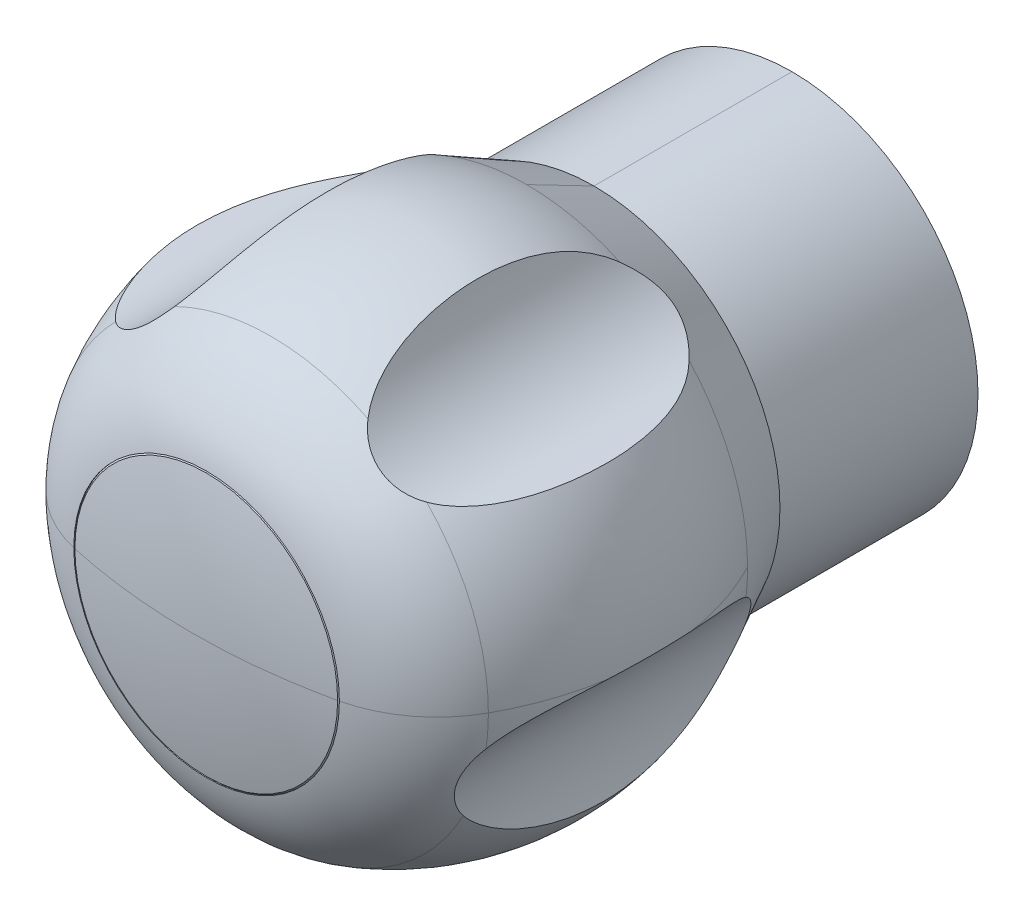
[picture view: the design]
ISO-10303-21;
HEADER;
FILE_DESCRIPTION(('STEP AP214'),'2;1');
FILE_NAME('part.step','',(''),(''),'','','');
FILE_SCHEMA(('AUTOMOTIVE_DESIGN { 1 0 10303 214 1 1 1 1 }'));
ENDSEC;
DATA;
#1=APPLICATION_CONTEXT('core data for automotive mechanical design processes');
#2=APPLICATION_PROTOCOL_DEFINITION('international standard','automotive_design',2000,#1);
#3=PRODUCT_CONTEXT('',#1,'mechanical');
#4=PRODUCT('Part','Part','',(#3));
#5=PRODUCT_RELATED_PRODUCT_CATEGORY('part','',(#4));
#6=PRODUCT_DEFINITION_FORMATION('','',#4);
#7=PRODUCT_DEFINITION_CONTEXT('part definition',#1,'design');
#8=PRODUCT_DEFINITION('design','',#6,#7);
#9=PRODUCT_DEFINITION_SHAPE('','',#8);
#10=(LENGTH_UNIT() NAMED_UNIT(*) SI_UNIT(.MILLI.,.METRE.));
#11=(NAMED_UNIT(*) PLANE_ANGLE_UNIT() SI_UNIT($,.RADIAN.));
#12=(NAMED_UNIT(*) SI_UNIT($,.STERADIAN.) SOLID_ANGLE_UNIT());
#13=UNCERTAINTY_MEASURE_WITH_UNIT(LENGTH_MEASURE(1.E-05),#10,'distance_accuracy_value','');
#14=(GEOMETRIC_REPRESENTATION_CONTEXT(3) GLOBAL_UNCERTAINTY_ASSIGNED_CONTEXT((#13)) GLOBAL_UNIT_ASSIGNED_CONTEXT((#10,
#11,#12)) REPRESENTATION_CONTEXT('',''));
#15=CARTESIAN_POINT('',(0.,0.,0.));
#16=DIRECTION('',(0.,0.,1.));
#17=DIRECTION('',(1.,0.,0.));
#18=AXIS2_PLACEMENT_3D('',#15,#16,#17);
#19=CARTESIAN_POINT('',(0.,0.,-0.499999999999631));
#20=DIRECTION('',(0.,0.,1.));
#21=DIRECTION('',(0.,1.,0.));
#22=AXIS2_PLACEMENT_3D('',#19,#20,#21);
#23=SPHERICAL_SURFACE('',#22,60.5);
#24=CARTESIAN_POINT('',(0.,0.,58.5716338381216));
#25=DIRECTION('',(0.,0.,-1.));
#26=DIRECTION('',(0.,1.,0.));
#27=AXIS2_PLACEMENT_3D('',#24,#25,#26);
#28=CIRCLE('',#27,13.068744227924);
#29=CARTESIAN_POINT('',(0.,-13.068744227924,58.5716338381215));
#30=VERTEX_POINT('',#29);
#31=CARTESIAN_POINT('',(-13.0687442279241,-5.9981704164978E-11,58.5716338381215));
#32=VERTEX_POINT('',#31);
#33=EDGE_CURVE('E421',#30,#32,#28,.T.);
#34=ORIENTED_EDGE('',*,*,#33,.F.);
#35=CARTESIAN_POINT('',(0.,0.,58.5716338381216));
#36=DIRECTION('',(0.,0.,-1.));
#37=DIRECTION('',(0.,1.,0.));
#38=AXIS2_PLACEMENT_3D('',#35,#36,#37);
#39=CIRCLE('',#38,13.068744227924);
#40=CARTESIAN_POINT('',(13.068744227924,-2.99962703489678E-11,58.5716338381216));
#41=VERTEX_POINT('',#40);
#42=EDGE_CURVE('E220',#41,#30,#39,.T.);
#43=ORIENTED_EDGE('',*,*,#42,.F.);
#44=CARTESIAN_POINT('',(0.,0.,60.0000000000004));
#45=CARTESIAN_POINT('',(0.548857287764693,-5.03823967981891E-12,60.0000019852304));
#46=CARTESIAN_POINT('',(1.09771448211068,-1.00764785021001E-11,59.9925312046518));
#47=CARTESIAN_POINT('',(2.1950223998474,-2.01492249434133E-11,59.9626583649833));
#48=CARTESIAN_POINT('',(2.74347312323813,-2.51837325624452E-11,59.9402563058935));
#49=CARTESIAN_POINT('',(3.83956181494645,-3.52452871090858E-11,59.8805351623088));
#50=CARTESIAN_POINT('',(4.38719978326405,-4.02723340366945E-11,59.8432160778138));
#51=CARTESIAN_POINT('',(5.48125736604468,-5.03152440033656E-11,59.7536891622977));
#52=CARTESIAN_POINT('',(6.0276769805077,-5.5331107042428E-11,59.7014813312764));
#53=CARTESIAN_POINT('',(7.11889312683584,-6.5347934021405E-11,59.5822153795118));
#54=CARTESIAN_POINT('',(7.66368965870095,-7.03488979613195E-11,59.5151572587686));
#55=CARTESIAN_POINT('',(8.75125615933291,-8.03322229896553E-11,59.3662406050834));
#56=CARTESIAN_POINT('',(9.29402612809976,-8.53145840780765E-11,59.2843820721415));
#57=CARTESIAN_POINT('',(10.3771373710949,-9.52570120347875E-11,59.1059245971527));
#58=CARTESIAN_POINT('',(10.9174786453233,-1.00217078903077E-10,59.0093256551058));
#59=CARTESIAN_POINT('',(11.9953327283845,-1.1011124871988E-10,58.8014612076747));
#60=CARTESIAN_POINT('',(12.5328455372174,-1.15045351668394E-10,58.6901957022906));
#61=CARTESIAN_POINT('',(13.0687442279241,-1.19964637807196E-10,58.5716338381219));
#62=B_SPLINE_CURVE_WITH_KNOTS('',3,(#44,#45,#46,#47,#48,#49,#50,#51,#52,#53,#54,#55,#56,#57,#58,
#59,#60,#61),.UNSPECIFIED.,.F.,.F.,(4,2,2,2,2,2,2,2,4),(0.,1.64652088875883,3.29304177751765,
4.93956266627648,6.5860835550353,8.23260444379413,9.87912533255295,11.5256462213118,
13.1721671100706),.UNSPECIFIED.);
#63=CARTESIAN_POINT('',(0.,0.,60.));
#64=VERTEX_POINT('',#63);
#65=EDGE_CURVE('E211',#64,#41,#62,.T.);
#66=ORIENTED_EDGE('',*,*,#65,.F.);
#67=CARTESIAN_POINT('',(0.,0.,-0.499999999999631));
#68=DIRECTION('',(9.17859660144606E-12,-1.,0.));
#69=DIRECTION('',(0.,0.,1.));
#70=AXIS2_PLACEMENT_3D('',#67,#68,#69);
#71=CIRCLE('',#70,60.5);
#72=EDGE_CURVE('E218',#32,#64,#71,.F.);
#73=ORIENTED_EDGE('',*,*,#72,.F.);
#74=EDGE_LOOP('',(#34,#43,#66,#73));
#75=FACE_BOUND('',#74,.T.);
#76=ADVANCED_FACE('F14',(#75),#23,.T.);
#77=CARTESIAN_POINT('',(0.,0.,-0.499999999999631));
#78=DIRECTION('',(0.,0.,1.));
#79=DIRECTION('',(0.,1.,0.));
#80=AXIS2_PLACEMENT_3D('',#77,#78,#79);
#81=SPHERICAL_SURFACE('',#80,60.5);
#82=CARTESIAN_POINT('',(0.,0.,58.5716338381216));
#83=DIRECTION('',(0.,0.,-1.));
#84=DIRECTION('',(0.,1.,0.));
#85=AXIS2_PLACEMENT_3D('',#82,#83,#84);
#86=CIRCLE('',#85,13.068744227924);
#87=CARTESIAN_POINT('',(0.,13.068744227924,58.5716338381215));
#88=VERTEX_POINT('',#87);
#89=EDGE_CURVE('E441',#88,#41,#86,.T.);
#90=ORIENTED_EDGE('',*,*,#89,.F.);
#91=CARTESIAN_POINT('',(0.,0.,58.5716338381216));
#92=DIRECTION('',(0.,0.,-1.));
#93=DIRECTION('',(0.,1.,0.));
#94=AXIS2_PLACEMENT_3D('',#91,#92,#93);
#95=CIRCLE('',#94,13.068744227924);
#96=EDGE_CURVE('E227',#32,#88,#95,.T.);
#97=ORIENTED_EDGE('',*,*,#96,.F.);
#98=ORIENTED_EDGE('',*,*,#72,.T.);
#99=ORIENTED_EDGE('',*,*,#65,.T.);
#100=EDGE_LOOP('',(#90,#97,#98,#99));
#101=FACE_BOUND('',#100,.T.);
#102=ADVANCED_FACE('F225',(#101),#81,.T.);
#103=CARTESIAN_POINT('',(0.,0.,58.4302124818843));
#104=DIRECTION('',(0.,0.,-1.));
#105=DIRECTION('',(-1.,0.,0.));
#106=AXIS2_PLACEMENT_3D('',#103,#104,#105);
#107=CONICAL_SURFACE('',#106,13.2101655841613,0.785398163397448);
#108=DIRECTION('',(0.,0.707106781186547,0.707106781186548));
#109=VECTOR('',#108,1.);
#110=CARTESIAN_POINT('',(0.,-13.1394549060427,58.5009231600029));
#111=LINE('',#110,#109);
#112=CARTESIAN_POINT('',(0.,-13.2101655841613,58.4302124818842));
#113=VERTEX_POINT('',#112);
#114=EDGE_CURVE('E418',#113,#30,#111,.T.);
#115=ORIENTED_EDGE('',*,*,#114,.F.);
#116=CARTESIAN_POINT('',(0.,0.,58.4302124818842));
#117=DIRECTION('',(0.,0.,1.));
#118=DIRECTION('',(1.,0.,0.));
#119=AXIS2_PLACEMENT_3D('',#116,#117,#118);
#120=CIRCLE('',#119,13.2101655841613);
#121=CARTESIAN_POINT('',(0.,13.2101655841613,58.4302124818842));
#122=VERTEX_POINT('',#121);
#123=EDGE_CURVE('E410',#113,#122,#120,.T.);
#124=ORIENTED_EDGE('',*,*,#123,.T.);
#125=DIRECTION('',(0.,-0.707106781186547,0.707106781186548));
#126=VECTOR('',#125,1.);
#127=CARTESIAN_POINT('',(0.,13.1394549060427,58.5009231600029));
#128=LINE('',#127,#126);
#129=EDGE_CURVE('E415',#88,#122,#128,.F.);
#130=ORIENTED_EDGE('',*,*,#129,.F.);
#131=ORIENTED_EDGE('',*,*,#89,.T.);
#132=ORIENTED_EDGE('',*,*,#42,.T.);
#133=EDGE_LOOP('',(#115,#124,#130,#131,#132));
#134=FACE_BOUND('',#133,.T.);
#135=ADVANCED_FACE('F429',(#134),#107,.T.);
#136=CARTESIAN_POINT('',(0.,0.,58.4302124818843));
#137=DIRECTION('',(0.,0.,-1.));
#138=DIRECTION('',(-1.,0.,0.));
#139=AXIS2_PLACEMENT_3D('',#136,#137,#138);
#140=CONICAL_SURFACE('',#139,13.2101655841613,0.785398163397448);
#141=ORIENTED_EDGE('',*,*,#33,.T.);
#142=ORIENTED_EDGE('',*,*,#96,.T.);
#143=ORIENTED_EDGE('',*,*,#129,.T.);
#144=CARTESIAN_POINT('',(0.,0.,58.4302124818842));
#145=DIRECTION('',(0.,0.,1.));
#146=DIRECTION('',(1.,0.,0.));
#147=AXIS2_PLACEMENT_3D('',#144,#145,#146);
#148=CIRCLE('',#147,13.2101655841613);
#149=EDGE_CURVE('E412',#122,#113,#148,.T.);
#150=ORIENTED_EDGE('',*,*,#149,.T.);
#151=ORIENTED_EDGE('',*,*,#114,.T.);
#152=EDGE_LOOP('',(#141,#142,#143,#150,#151));
#153=FACE_BOUND('',#152,.T.);
#154=ADVANCED_FACE('F882',(#153),#140,.T.);
#155=CARTESIAN_POINT('',(0.,0.,58.4848652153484));
#156=DIRECTION('',(0.,0.,1.));
#157=DIRECTION('',(1.,0.,0.));
#158=AXIS2_PLACEMENT_3D('',#155,#156,#157);
#159=CYLINDRICAL_SURFACE('',#158,13.2101655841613);
#160=ORIENTED_EDGE('',*,*,#123,.F.);
#161=DIRECTION('',(0.,0.,1.));
#162=VECTOR('',#161,1.);
#163=CARTESIAN_POINT('',(0.,-13.2101655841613,58.4848652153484));
#164=LINE('',#163,#162);
#165=CARTESIAN_POINT('',(0.,-13.2101655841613,58.5395179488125));
#166=VERTEX_POINT('',#165);
#167=EDGE_CURVE('E173',#113,#166,#164,.T.);
#168=ORIENTED_EDGE('',*,*,#167,.T.);
#169=CARTESIAN_POINT('',(0.,0.,58.5395179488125));
#170=DIRECTION('',(0.,0.,-1.));
#171=DIRECTION('',(-1.,0.,0.));
#172=AXIS2_PLACEMENT_3D('',#169,#170,#171);
#173=CIRCLE('',#172,13.2101655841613);
#174=CARTESIAN_POINT('',(13.2101655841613,0.,58.5395179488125));
#175=VERTEX_POINT('',#174);
#176=EDGE_CURVE('E390',#175,#166,#173,.T.);
#177=ORIENTED_EDGE('',*,*,#176,.F.);
#178=CARTESIAN_POINT('',(0.,0.,58.5395179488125));
#179=DIRECTION('',(0.,0.,-1.));
#180=DIRECTION('',(-1.,0.,0.));
#181=AXIS2_PLACEMENT_3D('',#178,#179,#180);
#182=CIRCLE('',#181,13.2101655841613);
#183=CARTESIAN_POINT('',(0.,13.2101655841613,58.5395179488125));
#184=VERTEX_POINT('',#183);
#185=EDGE_CURVE('E392',#184,#175,#182,.T.);
#186=ORIENTED_EDGE('',*,*,#185,.F.);
#187=DIRECTION('',(0.,0.,1.));
#188=VECTOR('',#187,1.);
#189=CARTESIAN_POINT('',(0.,13.2101655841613,58.4848652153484));
#190=LINE('',#189,#188);
#191=EDGE_CURVE('E404',#184,#122,#190,.F.);
#192=ORIENTED_EDGE('',*,*,#191,.T.);
#193=EDGE_LOOP('',(#160,#168,#177,#186,#192));
#194=FACE_BOUND('',#193,.T.);
#195=ADVANCED_FACE('F874',(#194),#159,.F.);
#196=CARTESIAN_POINT('',(0.,0.,58.4848652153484));
#197=DIRECTION('',(0.,0.,1.));
#198=DIRECTION('',(1.,0.,0.));
#199=AXIS2_PLACEMENT_3D('',#196,#197,#198);
#200=CYLINDRICAL_SURFACE('',#199,13.2101655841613);
#201=CARTESIAN_POINT('',(0.,0.,58.5395179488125));
#202=DIRECTION('',(0.,0.,-1.));
#203=DIRECTION('',(-1.,0.,0.));
#204=AXIS2_PLACEMENT_3D('',#201,#202,#203);
#205=CIRCLE('',#204,13.2101655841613);
#206=CARTESIAN_POINT('',(-13.2101655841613,0.,58.5395179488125));
#207=VERTEX_POINT('',#206);
#208=EDGE_CURVE('E395',#207,#184,#205,.T.);
#209=ORIENTED_EDGE('',*,*,#208,.F.);
#210=CARTESIAN_POINT('',(0.,0.,58.5395179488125));
#211=DIRECTION('',(0.,0.,-1.));
#212=DIRECTION('',(-1.,0.,0.));
#213=AXIS2_PLACEMENT_3D('',#210,#211,#212);
#214=CIRCLE('',#213,13.2101655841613);
#215=EDGE_CURVE('E398',#166,#207,#214,.T.);
#216=ORIENTED_EDGE('',*,*,#215,.F.);
#217=ORIENTED_EDGE('',*,*,#167,.F.);
#218=ORIENTED_EDGE('',*,*,#149,.F.);
#219=ORIENTED_EDGE('',*,*,#191,.F.);
#220=EDGE_LOOP('',(#209,#216,#217,#218,#219));
#221=FACE_BOUND('',#220,.T.);
#222=ADVANCED_FACE('F867',(#221),#200,.F.);
#223=CARTESIAN_POINT('',(2.,0.,39.12));
#224=DIRECTION('',(0.,1.,0.));
#225=DIRECTION('',(-1.,0.,0.));
#226=AXIS2_PLACEMENT_3D('',#223,#224,#225);
#227=CIRCLE('',#226,27.);
#228=TRIMMED_CURVE('',#227,(PARAMETER_VALUE(-1.49665434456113)),
(PARAMETER_VALUE(1.49665434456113)),.T.,.PARAMETER.);
#229=CARTESIAN_POINT('',(0.,0.,39.12));
#230=DIRECTION('',(0.,0.,-1.));
#231=AXIS1_PLACEMENT('',#229,#230);
#232=SURFACE_OF_REVOLUTION('',#228,#231);
#233=CARTESIAN_POINT('',(-24.4817349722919,0.,44.3847614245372));
#234=CARTESIAN_POINT('',(-24.4400037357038,-0.029552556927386,44.5946738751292));
#235=CARTESIAN_POINT('',(-24.3957791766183,-0.0612374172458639,44.8037990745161));
#236=CARTESIAN_POINT('',(-24.3021998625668,-0.129334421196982,45.2210940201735));
#237=CARTESIAN_POINT('',(-24.252823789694,-0.165766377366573,45.4292557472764));
#238=CARTESIAN_POINT('',(-24.1490113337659,-0.243681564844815,45.8440160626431));
#239=CARTESIAN_POINT('',(-24.0945609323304,-0.28517889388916,46.0506085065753));
#240=CARTESIAN_POINT('',(-23.9807066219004,-0.373591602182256,46.461617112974));
#241=CARTESIAN_POINT('',(-23.921295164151,-0.420515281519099,46.6660294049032));
#242=CARTESIAN_POINT('',(-23.797655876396,-0.520181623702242,47.0720679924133));
#243=CARTESIAN_POINT('',(-23.7334259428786,-0.572926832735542,47.2736930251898));
#244=CARTESIAN_POINT('',(-23.6030305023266,-0.682403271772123,47.6653886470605));
#245=CARTESIAN_POINT('',(-23.5370539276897,-0.738880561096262,47.8555929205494));
#246=CARTESIAN_POINT('',(-23.4009810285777,-0.858048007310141,48.2323524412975));
#247=CARTESIAN_POINT('',(-23.3308883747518,-0.920732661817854,48.418910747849));
#248=CARTESIAN_POINT('',(-23.1867626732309,-1.05281939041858,48.7878300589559));
#249=CARTESIAN_POINT('',(-23.1127341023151,-1.12221390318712,48.9701955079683));
#250=CARTESIAN_POINT('',(-22.9609317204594,-1.26829775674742,49.3301548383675));
#251=CARTESIAN_POINT('',(-22.8831617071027,-1.34497977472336,49.5077532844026));
#252=CARTESIAN_POINT('',(-22.7240724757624,-1.50632136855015,49.8575882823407));
#253=CARTESIAN_POINT('',(-22.6427546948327,-1.59097773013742,50.0298269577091));
#254=CARTESIAN_POINT('',(-22.5158209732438,-1.72718267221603,50.2886707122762));
#255=CARTESIAN_POINT('',(-22.4713732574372,-1.77560844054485,50.3775041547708));
#256=CARTESIAN_POINT('',(-22.3816155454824,-1.87502055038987,50.5532834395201));
#257=CARTESIAN_POINT('',(-22.3363055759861,-1.92600681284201,50.6402293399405));
#258=CARTESIAN_POINT('',(-22.2448970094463,-2.03064183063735,50.8120477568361));
#259=CARTESIAN_POINT('',(-22.1987986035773,-2.08428994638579,50.8969207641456));
#260=CARTESIAN_POINT('',(-22.1058883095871,-2.19436088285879,51.0644070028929));
#261=CARTESIAN_POINT('',(-22.0590766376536,-2.25078287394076,51.1470208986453));
#262=CARTESIAN_POINT('',(-21.9639864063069,-2.36754419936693,51.3112325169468));
#263=CARTESIAN_POINT('',(-21.915696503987,-2.42793471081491,51.3927873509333));
#264=CARTESIAN_POINT('',(-21.8185417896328,-2.55185887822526,51.5531504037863));
#265=CARTESIAN_POINT('',(-21.7696768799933,-2.61539307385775,51.6319581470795));
#266=CARTESIAN_POINT('',(-21.6714581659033,-2.74576322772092,51.7866078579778));
#267=CARTESIAN_POINT('',(-21.6221040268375,-2.81260159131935,51.8624475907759));
#268=CARTESIAN_POINT('',(-21.5230007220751,-2.9497548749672,52.0109198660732));
#269=CARTESIAN_POINT('',(-21.4732510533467,-3.02007514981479,52.083547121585));
#270=CARTESIAN_POINT('',(-21.4234114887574,-3.09213952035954,52.154357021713));
#271=B_SPLINE_CURVE_WITH_KNOTS('',3,(#233,#234,#235,#236,#237,#238,#239,#240,#241,#242,#243,
#244,#245,#246,#247,#248,#249,#250,#251,#252,#253,#254,#255,#256,#257,#258,#259,#260,#261,#262,
#263,#264,#265,#266,#267,#268,#269,#270),.UNSPECIFIED.,.F.,.F.,(4,2,2,2,2,2,2,2,2,2,2,2,2,2,2,2,
2,2,4),(0.,0.648139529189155,1.29907639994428,1.95186810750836,2.6056718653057,3.2597627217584,
3.88689053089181,4.51346732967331,5.13934609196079,5.76460246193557,6.38960787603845,
6.72109117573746,7.05256424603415,7.38395805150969,7.71525333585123,8.05232974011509,
8.38946421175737,8.72684783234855,9.06476748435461),.UNSPECIFIED.);
#272=CARTESIAN_POINT('',(-24.4817349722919,0.,44.3847614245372));
#273=VERTEX_POINT('',#272);
#274=CARTESIAN_POINT('',(-21.4234114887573,-3.09213952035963,52.154357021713));
#275=VERTEX_POINT('',#274);
#276=EDGE_CURVE('E164',#273,#275,#271,.T.);
#277=ORIENTED_EDGE('',*,*,#276,.T.);
#278=CARTESIAN_POINT('',(0.,0.,52.1543570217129));
#279=DIRECTION('',(0.,0.,-1.));
#280=DIRECTION('',(-1.,0.,0.));
#281=AXIS2_PLACEMENT_3D('',#278,#279,#280);
#282=CIRCLE('',#281,21.6454126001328);
#283=CARTESIAN_POINT('',(-21.6454126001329,0.,52.154357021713));
#284=VERTEX_POINT('',#283);
#285=EDGE_CURVE('E401',#284,#275,#282,.F.);
#286=ORIENTED_EDGE('',*,*,#285,.F.);
#287=CARTESIAN_POINT('',(2.,0.,39.12));
#288=DIRECTION('',(0.,1.,0.));
#289=DIRECTION('',(-1.,0.,0.));
#290=AXIS2_PLACEMENT_3D('',#287,#288,#289);
#291=CIRCLE('',#290,27.);
#292=EDGE_CURVE('E659',#273,#284,#291,.T.);
#293=ORIENTED_EDGE('',*,*,#292,.F.);
#294=EDGE_LOOP('',(#277,#286,#293));
#295=FACE_BOUND('',#294,.T.);
#296=ADVANCED_FACE('F373',(#295),#232,.F.);
#297=CARTESIAN_POINT('',(-10.2605843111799,0.,45.8785554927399));
#298=DIRECTION('',(0.,1.,0.));
#299=DIRECTION('',(-1.,0.,0.));
#300=AXIS2_PLACEMENT_3D('',#297,#298,#299);
#301=CIRCLE('',#300,13.);
#302=TRIMMED_CURVE('',#301,(PARAMETER_VALUE(-2.4804248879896)),
(PARAMETER_VALUE(2.4804248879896)),.T.,.PARAMETER.);
#303=CARTESIAN_POINT('',(0.,0.,45.8785554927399));
#304=DIRECTION('',(0.,0.,-1.));
#305=AXIS1_PLACEMENT('',#303,#304);
#306=SURFACE_OF_REVOLUTION('',#302,#305);
#307=CARTESIAN_POINT('',(-9.56099766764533,19.4193514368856,52.1543570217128));
#308=CARTESIAN_POINT('',(-9.63389189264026,19.3237676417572,52.251527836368));
#309=CARTESIAN_POINT('',(-9.7103478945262,19.2263967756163,52.3443214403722));
#310=CARTESIAN_POINT('',(-9.87044612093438,19.0289394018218,52.5204601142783));
#311=CARTESIAN_POINT('',(-9.9540919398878,18.9288515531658,52.6038004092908));
#312=CARTESIAN_POINT('',(-10.128754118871,18.7266910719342,52.760413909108));
#313=CARTESIAN_POINT('',(-10.2197865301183,18.6246145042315,52.8336642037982));
#314=CARTESIAN_POINT('',(-10.4088873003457,18.4197264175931,52.9691935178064));
#315=CARTESIAN_POINT('',(-10.5069544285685,18.3169150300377,53.0314744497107));
#316=CARTESIAN_POINT('',(-10.7101848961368,18.1112362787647,53.1446860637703));
#317=CARTESIAN_POINT('',(-10.8153715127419,18.0083699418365,53.1955769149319));
#318=CARTESIAN_POINT('',(-11.0320598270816,17.8040137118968,53.2852401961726));
#319=CARTESIAN_POINT('',(-11.1435613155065,17.7025237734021,53.3240130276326));
#320=CARTESIAN_POINT('',(-11.3720796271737,17.5021069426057,53.3890184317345));
#321=CARTESIAN_POINT('',(-11.4890882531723,17.4031765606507,53.4152690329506));
#322=CARTESIAN_POINT('',(-11.727978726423,17.2087078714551,53.4550569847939));
#323=CARTESIAN_POINT('',(-11.8498602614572,17.113169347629,53.4685951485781));
#324=CARTESIAN_POINT('',(-12.0910734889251,16.9312652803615,53.4824572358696));
#325=CARTESIAN_POINT('',(-12.2102034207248,16.844681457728,53.4834372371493));
#326=CARTESIAN_POINT('',(-12.451137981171,16.6759906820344,53.4738618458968));
#327=CARTESIAN_POINT('',(-12.5729425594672,16.5938836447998,53.4633066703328));
#328=CARTESIAN_POINT('',(-12.818331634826,16.4346456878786,53.4307457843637));
#329=CARTESIAN_POINT('',(-12.9419168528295,16.3575168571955,53.4087353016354));
#330=CARTESIAN_POINT('',(-13.1898238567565,16.2086803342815,53.3534531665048));
#331=CARTESIAN_POINT('',(-13.3141456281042,16.1369725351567,53.3201817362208));
#332=CARTESIAN_POINT('',(-13.5607644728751,16.0002234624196,53.2432150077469));
#333=CARTESIAN_POINT('',(-13.6830653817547,15.9351024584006,53.1996732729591));
#334=CARTESIAN_POINT('',(-13.9264477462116,15.8105314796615,53.1022925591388));
#335=CARTESIAN_POINT('',(-14.0475291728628,15.751081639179,53.0484533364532));
#336=CARTESIAN_POINT('',(-14.2874880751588,15.6379001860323,52.9309569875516));
#337=CARTESIAN_POINT('',(-14.4063665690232,15.5841658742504,52.8673045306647));
#338=CARTESIAN_POINT('',(-14.6410872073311,15.4823035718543,52.7307008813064));
#339=CARTESIAN_POINT('',(-14.7569302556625,15.4341738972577,52.6577524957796));
#340=CARTESIAN_POINT('',(-14.9668946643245,15.3504659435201,52.5152911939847));
#341=CARTESIAN_POINT('',(-15.0615666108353,15.3141041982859,52.4470427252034));
#342=CARTESIAN_POINT('',(-15.2476007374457,15.2451315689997,52.3048798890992));
#343=CARTESIAN_POINT('',(-15.3389701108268,15.2125121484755,52.2309790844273));
#344=CARTESIAN_POINT('',(-15.4286041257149,15.1816356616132,52.1543570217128));
#345=B_SPLINE_CURVE_WITH_KNOTS('',3,(#307,#308,#309,#310,#311,#312,#313,#314,#315,#316,#317,
#318,#319,#320,#321,#322,#323,#324,#325,#326,#327,#328,#329,#330,#331,#332,#333,#334,#335,#336,
#337,#338,#339,#340,#341,#342,#343,#344),.UNSPECIFIED.,.F.,.F.,(4,2,2,2,2,2,2,2,2,2,2,2,2,2,2,2,
2,2,4),(0.,0.463648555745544,0.92753026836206,1.39244848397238,1.85728555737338,
2.32372360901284,2.79014620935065,3.25589524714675,3.72161449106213,4.16289750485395,
4.60417221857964,5.04563091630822,5.48708090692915,5.92230753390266,6.35754446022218,
6.79257492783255,7.22747434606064,7.59396712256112,7.95960654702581),.UNSPECIFIED.);
#346=CARTESIAN_POINT('',(-9.56099766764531,19.4193514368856,52.1543570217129));
#347=VERTEX_POINT('',#346);
#348=CARTESIAN_POINT('',(-15.4286041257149,15.1816356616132,52.1543570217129));
#349=VERTEX_POINT('',#348);
#350=EDGE_CURVE('E742',#347,#349,#345,.T.);
#351=ORIENTED_EDGE('',*,*,#350,.T.);
#352=CARTESIAN_POINT('',(0.,0.,52.154357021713));
#353=DIRECTION('',(0.,0.,-1.));
#354=DIRECTION('',(-1.,0.,0.));
#355=AXIS2_PLACEMENT_3D('',#352,#353,#354);
#356=CIRCLE('',#355,21.6454126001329);
#357=EDGE_CURVE('E662',#284,#349,#356,.T.);
#358=ORIENTED_EDGE('',*,*,#357,.F.);
#359=CARTESIAN_POINT('',(-10.2605843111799,0.,45.8785554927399));
#360=DIRECTION('',(0.,1.,0.));
#361=DIRECTION('',(-1.,0.,0.));
#362=AXIS2_PLACEMENT_3D('',#359,#360,#361);
#363=CIRCLE('',#362,13.);
#364=EDGE_CURVE('E394',#207,#284,#363,.F.);
#365=ORIENTED_EDGE('',*,*,#364,.F.);
#366=ORIENTED_EDGE('',*,*,#208,.T.);
#367=ORIENTED_EDGE('',*,*,#185,.T.);
#368=CARTESIAN_POINT('',(10.2605843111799,0.,45.8785554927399));
#369=DIRECTION('',(0.,-1.,0.));
#370=DIRECTION('',(1.,0.,0.));
#371=AXIS2_PLACEMENT_3D('',#368,#369,#370);
#372=CIRCLE('',#371,13.);
#373=CARTESIAN_POINT('',(21.6454126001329,0.,52.154357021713));
#374=VERTEX_POINT('',#373);
#375=EDGE_CURVE('E387',#374,#175,#372,.T.);
#376=ORIENTED_EDGE('',*,*,#375,.F.);
#377=CARTESIAN_POINT('',(0.,0.,52.154357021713));
#378=DIRECTION('',(0.,0.,-1.));
#379=DIRECTION('',(-1.,0.,0.));
#380=AXIS2_PLACEMENT_3D('',#377,#378,#379);
#381=CIRCLE('',#380,21.6454126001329);
#382=CARTESIAN_POINT('',(15.5143899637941,15.093958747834,52.1543570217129));
#383=VERTEX_POINT('',#382);
#384=EDGE_CURVE('E762',#383,#374,#381,.T.);
#385=ORIENTED_EDGE('',*,*,#384,.F.);
#386=CARTESIAN_POINT('',(15.5143899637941,15.093958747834,52.1543570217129));
#387=CARTESIAN_POINT('',(15.4009588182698,15.1337482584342,52.251527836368));
#388=CARTESIAN_POINT('',(15.2847274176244,15.1763729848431,52.3443214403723));
#389=CARTESIAN_POINT('',(15.0474612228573,15.2676177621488,52.5204601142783));
#390=CARTESIAN_POINT('',(14.926424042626,15.3162408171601,52.6038004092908));
#391=CARTESIAN_POINT('',(14.680184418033,15.4198833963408,52.7604139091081));
#392=CARTESIAN_POINT('',(14.554973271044,15.474916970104,52.8336642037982));
#393=CARTESIAN_POINT('',(14.3016777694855,15.591448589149,52.9691935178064));
#394=CARTESIAN_POINT('',(14.1735939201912,15.6529455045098,53.0314744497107));
#395=CARTESIAN_POINT('',(13.9151801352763,15.7826709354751,53.1446860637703));
#396=CARTESIAN_POINT('',(13.7848439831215,15.8509219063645,53.1955769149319));
#397=CARTESIAN_POINT('',(13.5235292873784,15.9938551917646,53.2852401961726));
#398=CARTESIAN_POINT('',(13.3925507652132,16.0685372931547,53.3240130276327));
#399=CARTESIAN_POINT('',(13.131326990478,16.2239389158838,53.3890184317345));
#400=CARTESIAN_POINT('',(13.0010809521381,16.3046495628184,53.4152690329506));
#401=CARTESIAN_POINT('',(12.7423090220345,16.471753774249,53.455056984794));
#402=CARTESIAN_POINT('',(12.6137830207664,16.5581469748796,53.4685951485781));
#403=CARTESIAN_POINT('',(12.3662429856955,16.7313429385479,53.4824572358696));
#404=CARTESIAN_POINT('',(12.2470837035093,16.8178863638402,53.4834372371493));
#405=CARTESIAN_POINT('',(12.0121963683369,16.9949004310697,53.4738618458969));
#406=CARTESIAN_POINT('',(11.896468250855,17.0853709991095,53.4633066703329));
#407=CARTESIAN_POINT('',(11.6691945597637,17.2695426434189,53.4307457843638));
#408=CARTESIAN_POINT('',(11.5576507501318,17.3632450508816,53.4087353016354));
#409=CARTESIAN_POINT('',(11.3394913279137,17.5530256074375,53.3534531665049));
#410=CARTESIAN_POINT('',(11.2328756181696,17.6491037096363,53.3201817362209));
#411=CARTESIAN_POINT('',(11.0266101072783,17.841394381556,53.243215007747));
#412=CARTESIAN_POINT('',(10.9268832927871,17.9375859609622,53.1996732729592));
#413=CARTESIAN_POINT('',(10.7331999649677,18.1305617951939,53.1022925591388));
#414=CARTESIAN_POINT('',(10.6392435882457,18.2273460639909,53.0484533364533));
#415=CARTESIAN_POINT('',(10.4574502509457,18.4205855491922,52.9309569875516));
#416=CARTESIAN_POINT('',(10.3696104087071,18.5170408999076,52.8673045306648));
#417=CARTESIAN_POINT('',(10.2002009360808,18.7087963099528,52.7307008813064));
#418=CARTESIAN_POINT('',(10.1186294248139,18.8040967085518,52.6577524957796));
#419=CARTESIAN_POINT('',(9.97413585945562,18.9779175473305,52.5152911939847));
#420=CARTESIAN_POINT('',(9.91029854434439,19.0567195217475,52.4470427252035));
#421=CARTESIAN_POINT('',(9.78721396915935,19.2123347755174,52.3048798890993));
#422=CARTESIAN_POINT('',(9.72795636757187,19.2891522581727,52.2309790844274));
#423=CARTESIAN_POINT('',(9.6708926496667,19.3648579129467,52.1543570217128));
#424=B_SPLINE_CURVE_WITH_KNOTS('',3,(#386,#387,#388,#389,#390,#391,#392,#393,#394,#395,#396,
#397,#398,#399,#400,#401,#402,#403,#404,#405,#406,#407,#408,#409,#410,#411,#412,#413,#414,#415,
#416,#417,#418,#419,#420,#421,#422,#423),.UNSPECIFIED.,.F.,.F.,(4,2,2,2,2,2,2,2,2,2,2,2,2,2,2,2,
2,2,4),(0.,0.463648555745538,0.927530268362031,1.39244848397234,1.85728555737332,
2.3237236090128,2.79014620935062,3.25589524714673,3.72161449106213,4.16289750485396,
4.60417221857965,5.04563091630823,5.48708090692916,5.92230753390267,6.3575444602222,
6.79257492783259,7.22747434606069,7.5939671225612,7.95960654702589),.UNSPECIFIED.);
#425=CARTESIAN_POINT('',(9.67089264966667,19.3648579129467,52.1543570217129));
#426=VERTEX_POINT('',#425);
#427=EDGE_CURVE('E351',#383,#426,#424,.T.);
#428=ORIENTED_EDGE('',*,*,#427,.T.);
#429=CARTESIAN_POINT('',(0.,0.,52.154357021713));
#430=DIRECTION('',(0.,0.,-1.));
#431=DIRECTION('',(-1.,0.,0.));
#432=AXIS2_PLACEMENT_3D('',#429,#430,#431);
#433=CIRCLE('',#432,21.6454126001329);
#434=EDGE_CURVE('E358',#347,#426,#433,.T.);
#435=ORIENTED_EDGE('',*,*,#434,.F.);
#436=EDGE_LOOP('',(#351,#358,#365,#366,#367,#376,#385,#428,#435));
#437=FACE_BOUND('',#436,.T.);
#438=ADVANCED_FACE('F366',(#437),#306,.F.);
#439=CARTESIAN_POINT('',(2.,0.,39.12));
#440=DIRECTION('',(0.,1.,0.));
#441=DIRECTION('',(-1.,0.,0.));
#442=AXIS2_PLACEMENT_3D('',#439,#440,#441);
#443=CIRCLE('',#442,27.);
#444=TRIMMED_CURVE('',#443,(PARAMETER_VALUE(-1.49665434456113)),
(PARAMETER_VALUE(1.49665434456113)),.T.,.PARAMETER.);
#445=CARTESIAN_POINT('',(0.,0.,39.12));
#446=DIRECTION('',(0.,0.,-1.));
#447=AXIS1_PLACEMENT('',#445,#446);
#448=SURFACE_OF_REVOLUTION('',#444,#447);
#449=CARTESIAN_POINT('',(0.,0.,52.154357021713));
#450=DIRECTION('',(0.,0.,-1.));
#451=DIRECTION('',(-1.,0.,0.));
#452=AXIS2_PLACEMENT_3D('',#449,#450,#451);
#453=CIRCLE('',#452,21.6454126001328);
#454=CARTESIAN_POINT('',(21.4055444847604,-3.21349528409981,52.1543570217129));
#455=VERTEX_POINT('',#454);
#456=EDGE_CURVE('E391',#455,#374,#453,.F.);
#457=ORIENTED_EDGE('',*,*,#456,.F.);
#458=CARTESIAN_POINT('',(21.4055444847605,-3.21349528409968,52.154357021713));
#459=CARTESIAN_POINT('',(21.4821786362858,-3.10403098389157,52.0463597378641));
#460=CARTESIAN_POINT('',(21.5585603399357,-2.99863182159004,51.9341684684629));
#461=CARTESIAN_POINT('',(21.7100645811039,-2.79596733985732,51.7028673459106));
#462=CARTESIAN_POINT('',(21.785191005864,-2.69867034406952,51.5837878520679));
#463=CARTESIAN_POINT('',(21.933933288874,-2.51148979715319,51.3394962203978));
#464=CARTESIAN_POINT('',(22.0075516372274,-2.42159313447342,51.2142955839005));
#465=CARTESIAN_POINT('',(22.1530624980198,-2.24861008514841,50.9584090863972));
#466=CARTESIAN_POINT('',(22.2249556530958,-2.16552113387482,50.8277253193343));
#467=CARTESIAN_POINT('',(22.3650680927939,-2.00760574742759,50.5647215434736));
#468=CARTESIAN_POINT('',(22.4333341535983,-1.93262860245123,50.4325165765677));
#469=CARTESIAN_POINT('',(22.5678429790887,-1.78826507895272,50.16393768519));
#470=CARTESIAN_POINT('',(22.6340841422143,-1.71888305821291,50.0275606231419));
#471=CARTESIAN_POINT('',(22.7643627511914,-1.58536111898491,49.7511188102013));
#472=CARTESIAN_POINT('',(22.8283988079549,-1.52122447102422,49.6110518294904));
#473=CARTESIAN_POINT('',(22.954095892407,-1.39788449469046,49.3276989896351));
#474=CARTESIAN_POINT('',(23.0157566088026,-1.33868181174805,49.184412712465));
#475=CARTESIAN_POINT('',(23.1494004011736,-1.21282128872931,48.8642842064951));
#476=CARTESIAN_POINT('',(23.220798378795,-1.14724616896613,48.6867716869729));
#477=CARTESIAN_POINT('',(23.3597515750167,-1.02235910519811,48.3281258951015));
#478=CARTESIAN_POINT('',(23.4273074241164,-0.963046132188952,48.1469932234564));
#479=CARTESIAN_POINT('',(23.5584775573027,-0.850175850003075,47.7814822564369));
#480=CARTESIAN_POINT('',(23.6220907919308,-0.796620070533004,47.5971031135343));
#481=CARTESIAN_POINT('',(23.7452765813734,-0.694829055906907,47.2254585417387));
#482=CARTESIAN_POINT('',(23.8048473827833,-0.646596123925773,47.0381919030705));
#483=CARTESIAN_POINT('',(23.9198543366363,-0.555072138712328,46.6611165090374));
#484=CARTESIAN_POINT('',(23.9752888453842,-0.511783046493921,46.4713067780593));
#485=CARTESIAN_POINT('',(24.0839985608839,-0.428229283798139,46.0820959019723));
#486=CARTESIAN_POINT('',(24.1371060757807,-0.388147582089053,45.8826087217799));
#487=CARTESIAN_POINT('',(24.2386798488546,-0.312628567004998,45.481619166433));
#488=CARTESIAN_POINT('',(24.2871467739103,-0.277190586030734,45.2801170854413));
#489=CARTESIAN_POINT('',(24.3793626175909,-0.210671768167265,44.8754700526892));
#490=CARTESIAN_POINT('',(24.4231146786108,-0.179588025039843,44.6723262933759));
#491=CARTESIAN_POINT('',(24.5058384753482,-0.121520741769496,44.2647686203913));
#492=CARTESIAN_POINT('',(24.5448163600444,-0.0945319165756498,44.0603567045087));
#493=CARTESIAN_POINT('',(24.617948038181,-0.0444348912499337,43.6506305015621));
#494=CARTESIAN_POINT('',(24.6521114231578,-0.0213189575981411,43.445318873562));
#495=CARTESIAN_POINT('',(24.6838914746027,0.,43.2394581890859));
#496=B_SPLINE_CURVE_WITH_KNOTS('',3,(#458,#459,#460,#461,#462,#463,#464,#465,#466,#467,#468,
#469,#470,#471,#472,#473,#474,#475,#476,#477,#478,#479,#480,#481,#482,#483,#484,#485,#486,#487,
#488,#489,#490,#491,#492,#493,#494,#495),.UNSPECIFIED.,.F.,.F.,(4,2,2,2,2,2,2,2,2,2,2,2,2,2,2,2,
2,2,4),(0.,0.51523408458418,1.02834866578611,1.54053363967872,2.05252476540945,2.55219588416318,
3.05225248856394,3.55261854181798,4.05304994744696,4.65964107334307,5.26613236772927,
5.87278441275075,6.47969793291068,7.08685136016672,7.71760531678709,8.34826849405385,
8.97850870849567,9.60792846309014,10.2360759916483),.UNSPECIFIED.);
#497=CARTESIAN_POINT('',(24.6838914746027,0.,43.2394581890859));
#498=VERTEX_POINT('',#497);
#499=EDGE_CURVE('E550',#455,#498,#496,.T.);
#500=ORIENTED_EDGE('',*,*,#499,.T.);
#501=CARTESIAN_POINT('',(-2.,0.,39.12));
#502=DIRECTION('',(0.,-1.,0.));
#503=DIRECTION('',(1.,0.,0.));
#504=AXIS2_PLACEMENT_3D('',#501,#502,#503);
#505=CIRCLE('',#504,27.);
#506=EDGE_CURVE('E765',#374,#498,#505,.F.);
#507=ORIENTED_EDGE('',*,*,#506,.F.);
#508=EDGE_LOOP('',(#457,#500,#507));
#509=FACE_BOUND('',#508,.T.);
#510=ADVANCED_FACE('F372',(#509),#448,.F.);
#511=CARTESIAN_POINT('',(-10.2605843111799,0.,45.8785554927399));
#512=DIRECTION('',(0.,1.,0.));
#513=DIRECTION('',(-1.,0.,0.));
#514=AXIS2_PLACEMENT_3D('',#511,#512,#513);
#515=CIRCLE('',#514,13.);
#516=TRIMMED_CURVE('',#515,(PARAMETER_VALUE(-2.4804248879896)),
(PARAMETER_VALUE(2.4804248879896)),.T.,.PARAMETER.);
#517=CARTESIAN_POINT('',(0.,0.,45.8785554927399));
#518=DIRECTION('',(0.,0.,-1.));
#519=AXIS1_PLACEMENT('',#517,#518);
#520=SURFACE_OF_REVOLUTION('',#516,#519);
#521=ORIENTED_EDGE('',*,*,#176,.T.);
#522=ORIENTED_EDGE('',*,*,#215,.T.);
#523=ORIENTED_EDGE('',*,*,#364,.T.);
#524=ORIENTED_EDGE('',*,*,#285,.T.);
#525=CARTESIAN_POINT('',(-21.4234114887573,-3.09213952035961,52.1543570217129));
#526=CARTESIAN_POINT('',(-21.3550314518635,-3.19100306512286,52.251527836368));
#527=CARTESIAN_POINT('',(-21.2860524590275,-3.29380629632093,52.3443214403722));
#528=CARTESIAN_POINT('',(-21.1477324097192,-3.50708644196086,52.5204601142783));
#529=CARTESIAN_POINT('',(-21.078391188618,-3.61756718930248,52.6038004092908));
#530=CARTESIAN_POINT('',(-20.9400987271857,-3.84615181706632,52.760413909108));
#531=CARTESIAN_POINT('',(-20.8711487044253,-3.96427217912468,52.8336642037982));
#532=CARTESIAN_POINT('',(-20.7347239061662,-4.20743159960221,52.9691935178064));
#533=CARTESIAN_POINT('',(-20.6672488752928,-4.33246944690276,53.0314744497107));
#534=CARTESIAN_POINT('',(-20.5344384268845,-4.58931133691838,53.1446860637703));
#535=CARTESIAN_POINT('',(-20.4691111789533,-4.72113720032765,53.1955769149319));
#536=CARTESIAN_POINT('',(-20.3417172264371,-4.99036958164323,53.2852401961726));
#537=CARTESIAN_POINT('',(-20.2796504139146,-5.12777591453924,53.3240130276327));
#538=CARTESIAN_POINT('',(-20.1596587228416,-5.407041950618,53.3890184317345));
#539=CARTESIAN_POINT('',(-20.1017279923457,-5.54889493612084,53.4152690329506));
#540=CARTESIAN_POINT('',(-19.9905984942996,-5.836187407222,53.455056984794));
#541=CARTESIAN_POINT('',(-19.9373994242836,-5.98162666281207,53.4685951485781));
#542=CARTESIAN_POINT('',(-19.8389373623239,-6.26724552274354,53.4824572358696));
#543=CARTESIAN_POINT('',(-19.7934044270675,-6.4073006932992,53.4834372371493));
#544=CARTESIAN_POINT('',(-19.7074228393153,-6.68857139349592,53.4738618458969));
#545=CARTESIAN_POINT('',(-19.6669740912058,-6.8297869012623,53.4633066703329));
#546=CARTESIAN_POINT('',(-19.5913591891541,-7.11237301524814,53.4307457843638));
#547=CARTESIAN_POINT('',(-19.5561952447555,-7.2537436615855,53.4087353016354));
#548=CARTESIAN_POINT('',(-19.4912507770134,-7.53551024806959,53.3534531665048));
#549=CARTESIAN_POINT('',(-19.4614701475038,-7.67590620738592,53.3201817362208));
#550=CARTESIAN_POINT('',(-19.4076234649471,-7.95271245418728,53.2432150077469));
#551=CARTESIAN_POINT('',(-19.3834827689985,-8.08915102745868,53.1996732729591));
#552=CARTESIAN_POINT('',(-19.3402180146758,-8.35911596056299,53.1022925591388));
#553=CARTESIAN_POINT('',(-19.3210940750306,-8.49264225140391,53.0484533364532));
#554=CARTESIAN_POINT('',(-19.2876034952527,-8.75583172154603,52.9309569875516));
#555=CARTESIAN_POINT('',(-19.2732346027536,-8.88549670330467,52.8673045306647));
#556=CARTESIAN_POINT('',(-19.2488904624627,-9.140206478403,52.7307008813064));
#557=CARTESIAN_POINT('',(-19.238913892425,-9.26525265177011,52.6577524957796));
#558=CARTESIAN_POINT('',(-19.2241854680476,-9.49080785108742,52.5152911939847));
#559=CARTESIAN_POINT('',(-19.2188586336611,-9.59208261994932,52.4470427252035));
#560=CARTESIAN_POINT('',(-19.2107494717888,-9.79032530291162,52.3048798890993));
#561=CARTESIAN_POINT('',(-19.2079612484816,-9.88730269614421,52.2309790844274));
#562=CARTESIAN_POINT('',(-19.2062943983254,-9.98209106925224,52.1543570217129));
#563=B_SPLINE_CURVE_WITH_KNOTS('',3,(#525,#526,#527,#528,#529,#530,#531,#532,#533,#534,#535,
#536,#537,#538,#539,#540,#541,#542,#543,#544,#545,#546,#547,#548,#549,#550,#551,#552,#553,#554,
#555,#556,#557,#558,#559,#560,#561,#562),.UNSPECIFIED.,.F.,.F.,(4,2,2,2,2,2,2,2,2,2,2,2,2,2,2,2,
2,2,4),(0.,0.463648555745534,0.927530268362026,1.39244848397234,1.85728555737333,
2.3237236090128,2.79014620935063,3.25589524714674,3.72161449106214,4.16289750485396,
4.60417221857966,5.04563091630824,5.48708090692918,5.92230753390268,6.3575444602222,
6.79257492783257,7.22747434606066,7.59396712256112,7.95960654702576),.UNSPECIFIED.);
#564=CARTESIAN_POINT('',(-19.2062943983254,-9.98209106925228,52.1543570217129));
#565=VERTEX_POINT('',#564);
#566=EDGE_CURVE('E584',#275,#565,#563,.T.);
#567=ORIENTED_EDGE('',*,*,#566,.T.);
#568=CARTESIAN_POINT('',(0.,0.,52.154357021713));
#569=DIRECTION('',(0.,0.,-1.));
#570=DIRECTION('',(-1.,0.,0.));
#571=AXIS2_PLACEMENT_3D('',#568,#569,#570);
#572=CIRCLE('',#571,21.6454126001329);
#573=CARTESIAN_POINT('',(-3.6793987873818,-21.3303987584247,52.154357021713));
#574=VERTEX_POINT('',#573);
#575=EDGE_CURVE('E407',#574,#565,#572,.T.);
#576=ORIENTED_EDGE('',*,*,#575,.F.);
#577=CARTESIAN_POINT('',(-3.67939878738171,-21.3303987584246,52.1543570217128));
#578=CARTESIAN_POINT('',(-3.56424337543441,-21.2959159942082,52.251527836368));
#579=CARTESIAN_POINT('',(-3.44515601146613,-21.262081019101,52.3443214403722));
#580=CARTESIAN_POINT('',(-3.19957129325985,-21.1964380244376,52.5204601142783));
#581=CARTESIAN_POINT('',(-3.07307024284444,-21.1646310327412,52.6038004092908));
#582=CARTESIAN_POINT('',(-2.81293862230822,-21.1037436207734,52.760413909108));
#583=CARTESIAN_POINT('',(-2.67929275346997,-21.0746694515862,52.8336642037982));
#584=CARTESIAN_POINT('',(-2.40587682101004,-21.0200621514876,52.9691935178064));
#585=CARTESIAN_POINT('',(-2.26610783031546,-20.994528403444,53.0314744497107));
#586=CARTESIAN_POINT('',(-1.98079599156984,-20.9475866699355,53.1446860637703));
#587=CARTESIAN_POINT('',(-1.83523491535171,-20.9261931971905,53.1955769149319));
#588=CARTESIAN_POINT('',(-1.53981280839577,-20.888231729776,53.2852401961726));
#589=CARTESIAN_POINT('',(-1.38995192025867,-20.8716635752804,53.3240130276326));
#590=CARTESIAN_POINT('',(-1.0872746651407,-20.8438426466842,53.3890184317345));
#591=CARTESIAN_POINT('',(-0.934462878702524,-20.8325822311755,53.4152690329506));
#592=CARTESIAN_POINT('',(-0.626890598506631,-20.8156700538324,53.4550569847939));
#593=CARTESIAN_POINT('',(-0.47213023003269,-20.8100179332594,53.4685951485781));
#594=CARTESIAN_POINT('',(-0.170064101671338,-20.8046360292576,53.4824572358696));
#595=CARTESIAN_POINT('',(-0.0227932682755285,-20.8046110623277,53.4834372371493));
#596=CARTESIAN_POINT('',(0.271280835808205,-20.8097551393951,53.4738618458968));
#597=CARTESIAN_POINT('',(0.418084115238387,-20.8149240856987,53.4633066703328));
#598=CARTESIAN_POINT('',(0.710205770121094,-20.8303339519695,53.4307457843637));
#599=CARTESIAN_POINT('',(0.855523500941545,-20.8405769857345,53.4087353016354));
#600=CARTESIAN_POINT('',(1.14356839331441,-20.8658817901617,53.3534531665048));
#601=CARTESIAN_POINT('',(1.28629560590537,-20.8809434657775,53.3201817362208));
#602=CARTESIAN_POINT('',(1.56619353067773,-20.9152700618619,53.2432150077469));
#603=CARTESIAN_POINT('',(1.70341421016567,-20.9344727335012,53.1996732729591));
#604=CARTESIAN_POINT('',(1.97353566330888,-20.9767492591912,53.1022925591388));
#605=CARTESIAN_POINT('',(2.10643633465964,-20.99982320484,53.0484533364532));
#606=CARTESIAN_POINT('',(2.36709355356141,-21.0493017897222,52.9309569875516));
#607=CARTESIAN_POINT('',(2.49485251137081,-21.0757048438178,52.8673045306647));
#608=CARTESIAN_POINT('',(2.7446186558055,-21.1312618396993,52.7307008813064));
#609=CARTESIAN_POINT('',(2.86662756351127,-21.1604149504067,52.6577524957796));
#610=CARTESIAN_POINT('',(3.08569463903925,-21.2161077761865,52.5152911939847));
#611=CARTESIAN_POINT('',(3.18365875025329,-21.2423372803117,52.4470427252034));
#612=CARTESIAN_POINT('',(3.37470461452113,-21.2958853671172,52.3048798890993));
#613=CARTESIAN_POINT('',(3.46779720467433,-21.323201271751,52.2309790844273));
#614=CARTESIAN_POINT('',(3.55846138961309,-21.3509072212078,52.1543570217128));
#615=B_SPLINE_CURVE_WITH_KNOTS('',3,(#577,#578,#579,#580,#581,#582,#583,#584,#585,#586,#587,
#588,#589,#590,#591,#592,#593,#594,#595,#596,#597,#598,#599,#600,#601,#602,#603,#604,#605,#606,
#607,#608,#609,#610,#611,#612,#613,#614),.UNSPECIFIED.,.F.,.F.,(4,2,2,2,2,2,2,2,2,2,2,2,2,2,2,2,
2,2,4),(0.,0.463648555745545,0.927530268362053,1.39244848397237,1.85728555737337,
2.32372360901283,2.79014620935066,3.25589524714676,3.72161449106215,4.16289750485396,
4.60417221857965,5.04563091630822,5.48708090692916,5.92230753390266,6.35754446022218,
6.79257492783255,7.22747434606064,7.59396712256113,7.95960654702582),.UNSPECIFIED.);
#616=CARTESIAN_POINT('',(3.55846138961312,-21.3509072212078,52.1543570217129));
#617=VERTEX_POINT('',#616);
#618=EDGE_CURVE('E526',#574,#617,#615,.T.);
#619=ORIENTED_EDGE('',*,*,#618,.T.);
#620=CARTESIAN_POINT('',(0.,0.,52.154357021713));
#621=DIRECTION('',(0.,0.,-1.));
#622=DIRECTION('',(-1.,0.,0.));
#623=AXIS2_PLACEMENT_3D('',#620,#621,#622);
#624=CIRCLE('',#623,21.6454126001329);
#625=CARTESIAN_POINT('',(19.1494179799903,-10.0907719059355,52.1543570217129));
#626=VERTEX_POINT('',#625);
#627=EDGE_CURVE('E492',#626,#617,#624,.T.);
#628=ORIENTED_EDGE('',*,*,#627,.F.);
#629=CARTESIAN_POINT('',(19.1494179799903,-10.0907719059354,52.1543570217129));
#630=CARTESIAN_POINT('',(19.1522079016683,-9.97059684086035,52.251527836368));
#631=CARTESIAN_POINT('',(19.1568289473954,-9.8468824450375,52.3443214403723));
#632=CARTESIAN_POINT('',(19.1702886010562,-9.59303269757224,52.5204601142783));
#633=CARTESIAN_POINT('',(19.1791293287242,-9.46289414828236,52.6038004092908));
#634=CARTESIAN_POINT('',(19.2016070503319,-9.19667903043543,52.760413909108));
#635=CARTESIAN_POINT('',(19.2152547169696,-9.06058984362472,52.8336642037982));
#636=CARTESIAN_POINT('',(19.2478102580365,-8.78368125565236,52.9691935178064));
#637=CARTESIAN_POINT('',(19.2667172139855,-8.64286268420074,53.0314744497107));
#638=CARTESIAN_POINT('',(19.3102391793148,-8.35700920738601,53.1446860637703));
#639=CARTESIAN_POINT('',(19.3348736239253,-8.21196145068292,53.1955769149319));
#640=CARTESIAN_POINT('',(19.3900605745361,-7.91926759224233,53.2852401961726));
#641=CARTESIAN_POINT('',(19.4206128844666,-7.7716215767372,53.3240130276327));
#642=CARTESIAN_POINT('',(19.487686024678,-7.47516126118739,53.3890184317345));
#643=CARTESIAN_POINT('',(19.5241981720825,-7.32634895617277,53.4152690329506));
#644=CARTESIAN_POINT('',(19.6031587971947,-7.0286041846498,53.455056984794));
#645=CARTESIAN_POINT('',(19.6456068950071,-6.87967172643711,53.4685951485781));
#646=CARTESIAN_POINT('',(19.7338319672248,-6.59072666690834,53.4824572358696));
#647=CARTESIAN_POINT('',(19.7793174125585,-6.45065606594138,53.4834372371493));
#648=CARTESIAN_POINT('',(19.8750836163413,-6.1725645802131,53.4738618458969));
#649=CARTESIAN_POINT('',(19.9253642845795,-6.03454365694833,53.4633066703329));
#650=CARTESIAN_POINT('',(20.0302904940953,-5.76148136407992,53.4307457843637));
#651=CARTESIAN_POINT('',(20.0849378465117,-5.62644126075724,53.4087353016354));
#652=CARTESIAN_POINT('',(20.1980149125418,-5.36031390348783,53.3534531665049));
#653=CARTESIAN_POINT('',(20.256444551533,-5.22922657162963,53.3201817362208));
#654=CARTESIAN_POINT('',(20.3755842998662,-4.97363532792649,53.2432150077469));
#655=CARTESIAN_POINT('',(20.4362506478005,-4.84906465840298,53.1996732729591));
#656=CARTESIAN_POINT('',(20.5599301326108,-4.60522805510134,53.1022925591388));
#657=CARTESIAN_POINT('',(20.622943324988,-4.48596224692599,53.0484533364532));
#658=CARTESIAN_POINT('',(20.7505477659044,-4.2533522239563,52.9309569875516));
#659=CARTESIAN_POINT('',(20.8151382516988,-4.14000522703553,52.8673045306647));
#660=CARTESIAN_POINT('',(20.9451580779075,-3.91963156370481,52.7307008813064));
#661=CARTESIAN_POINT('',(21.0105871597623,-3.81260300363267,52.6577524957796));
#662=CARTESIAN_POINT('',(21.1312496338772,-3.62146786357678,52.5152911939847));
#663=CARTESIAN_POINT('',(21.1864679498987,-3.53640381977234,52.4470427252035));
#664=CARTESIAN_POINT('',(21.2964316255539,-3.37125567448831,52.3048798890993));
#665=CARTESIAN_POINT('',(21.3511777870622,-3.29116043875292,52.2309790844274));
#666=CARTESIAN_POINT('',(21.4055444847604,-3.21349528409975,52.1543570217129));
#667=B_SPLINE_CURVE_WITH_KNOTS('',3,(#629,#630,#631,#632,#633,#634,#635,#636,#637,#638,#639,
#640,#641,#642,#643,#644,#645,#646,#647,#648,#649,#650,#651,#652,#653,#654,#655,#656,#657,#658,
#659,#660,#661,#662,#663,#664,#665,#666),.UNSPECIFIED.,.F.,.F.,(4,2,2,2,2,2,2,2,2,2,2,2,2,2,2,2,
2,2,4),(0.,0.463648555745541,0.927530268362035,1.39244848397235,1.85728555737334,
2.32372360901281,2.79014620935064,3.25589524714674,3.72161449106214,4.16289750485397,
4.60417221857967,5.04563091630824,5.48708090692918,5.92230753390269,6.35754446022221,
6.79257492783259,7.22747434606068,7.59396712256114,7.95960654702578),.UNSPECIFIED.);
#668=EDGE_CURVE('E556',#626,#455,#667,.T.);
#669=ORIENTED_EDGE('',*,*,#668,.T.);
#670=ORIENTED_EDGE('',*,*,#456,.T.);
#671=ORIENTED_EDGE('',*,*,#375,.T.);
#672=EDGE_LOOP('',(#521,#522,#523,#524,#567,#576,#619,#628,#669,#670,#671));
#673=FACE_BOUND('',#672,.T.);
#674=ADVANCED_FACE('F567',(#673),#520,.F.);
#675=CARTESIAN_POINT('',(2.,0.,39.12));
#676=DIRECTION('',(0.,1.,0.));
#677=DIRECTION('',(-1.,0.,0.));
#678=AXIS2_PLACEMENT_3D('',#675,#676,#677);
#679=CIRCLE('',#678,27.);
#680=TRIMMED_CURVE('',#679,(PARAMETER_VALUE(-1.49665434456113)),
(PARAMETER_VALUE(1.49665434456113)),.T.,.PARAMETER.);
#681=CARTESIAN_POINT('',(0.,0.,39.12));
#682=DIRECTION('',(0.,0.,-1.));
#683=AXIS1_PLACEMENT('',#681,#682);
#684=SURFACE_OF_REVOLUTION('',#680,#683);
#685=CARTESIAN_POINT('',(0.,0.,26.6921745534));
#686=DIRECTION('',(0.,0.,1.));
#687=DIRECTION('',(0.,1.,0.));
#688=AXIS2_PLACEMENT_3D('',#685,#686,#687);
#689=CIRCLE('',#688,21.9697549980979);
#690=CARTESIAN_POINT('',(-4.31940637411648,-21.5409578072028,26.6921745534));
#691=VERTEX_POINT('',#690);
#692=CARTESIAN_POINT('',(-19.212592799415,-10.655815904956,26.6921745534));
#693=VERTEX_POINT('',#692);
#694=EDGE_CURVE('E676',#691,#693,#689,.F.);
#695=ORIENTED_EDGE('',*,*,#694,.F.);
#696=CARTESIAN_POINT('',(-4.31940637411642,-21.5409578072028,26.6921745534));
#697=CARTESIAN_POINT('',(-4.4043912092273,-21.5714818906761,26.7821243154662));
#698=CARTESIAN_POINT('',(-4.48732109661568,-21.6023021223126,26.8738806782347));
#699=CARTESIAN_POINT('',(-4.64919539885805,-21.6643480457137,27.0606740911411));
#700=CARTESIAN_POINT('',(-4.72814075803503,-21.6955736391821,27.1557103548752));
#701=CARTESIAN_POINT('',(-4.9586411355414,-21.789354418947,27.4445484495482));
#702=CARTESIAN_POINT('',(-5.10452494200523,-21.8522559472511,27.6427903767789));
#703=CARTESIAN_POINT('',(-5.38200898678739,-21.9776927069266,28.0487629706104));
#704=CARTESIAN_POINT('',(-5.51362240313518,-22.0402282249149,28.2564846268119));
#705=CARTESIAN_POINT('',(-5.76262409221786,-22.1634577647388,28.6779738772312));
#706=CARTESIAN_POINT('',(-5.88013488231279,-22.2241635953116,28.89166592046));
#707=CARTESIAN_POINT('',(-6.10341694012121,-22.3436378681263,29.3258636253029));
#708=CARTESIAN_POINT('',(-6.20917722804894,-22.4024044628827,29.5463754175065));
#709=CARTESIAN_POINT('',(-6.40974874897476,-22.5173451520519,29.9930811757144));
#710=CARTESIAN_POINT('',(-6.50455511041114,-22.5735180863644,30.2192776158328));
#711=CARTESIAN_POINT('',(-6.72107527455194,-22.7053243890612,30.7709959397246));
#712=CARTESIAN_POINT('',(-6.83769557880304,-22.779395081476,31.0988970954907));
#713=CARTESIAN_POINT('',(-7.05243026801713,-22.9200965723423,31.7622021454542));
#714=CARTESIAN_POINT('',(-7.1505449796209,-22.9867275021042,32.0976059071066));
#715=CARTESIAN_POINT('',(-7.32987058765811,-23.1116714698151,32.7744623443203));
#716=CARTESIAN_POINT('',(-7.41107901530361,-23.1699832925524,33.1159158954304));
#717=CARTESIAN_POINT('',(-7.55821254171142,-23.2778381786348,33.8052091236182));
#718=CARTESIAN_POINT('',(-7.62406219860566,-23.3273376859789,34.1530716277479));
#719=CARTESIAN_POINT('',(-7.74100254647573,-23.4166703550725,34.8524215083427));
#720=CARTESIAN_POINT('',(-7.79209601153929,-23.456505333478,35.2039081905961));
#721=CARTESIAN_POINT('',(-7.88032025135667,-23.526103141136,35.9094862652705));
#722=CARTESIAN_POINT('',(-7.91745550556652,-23.5558692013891,36.263576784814));
#723=CARTESIAN_POINT('',(-7.9836401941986,-23.6093149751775,37.0351158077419));
#724=CARTESIAN_POINT('',(-8.01017697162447,-23.6310490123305,37.4529209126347));
#725=CARTESIAN_POINT('',(-8.03655485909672,-23.6527166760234,38.0792235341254));
#726=CARTESIAN_POINT('',(-8.04310984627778,-23.6581170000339,38.2872875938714));
#727=CARTESIAN_POINT('',(-8.05184281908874,-23.6653203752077,38.7035637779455));
#728=CARTESIAN_POINT('',(-8.05402093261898,-23.6671235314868,38.911775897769));
#729=CARTESIAN_POINT('',(-8.0540243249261,-23.6671226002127,39.12));
#730=B_SPLINE_CURVE_WITH_KNOTS('',3,(#696,#697,#698,#699,#700,#701,#702,#703,#704,#705,#706,
#707,#708,#709,#710,#711,#712,#713,#714,#715,#716,#717,#718,#719,#720,#721,#722,#723,#724,#725,
#726,#727,#728,#729),.UNSPECIFIED.,.F.,.F.,(4,2,2,2,2,2,2,2,2,2,2,2,2,2,2,2,4),(0.,
0.382298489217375,0.764505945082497,1.52592099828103,2.28662682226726,3.04015413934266,
3.79437974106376,4.54893949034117,5.61564914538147,6.68233997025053,7.74918645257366,
8.82116780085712,9.89294749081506,10.96438293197,12.2212989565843,12.8459461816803,
13.4705751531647),.UNSPECIFIED.);
#731=CARTESIAN_POINT('',(-8.0540243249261,-23.6671226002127,39.12));
#732=VERTEX_POINT('',#731);
#733=EDGE_CURVE('E686',#691,#732,#730,.T.);
#734=ORIENTED_EDGE('',*,*,#733,.T.);
#735=CARTESIAN_POINT('',(-8.0540243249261,-23.6671226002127,39.12));
#736=CARTESIAN_POINT('',(-8.05401415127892,-23.6671276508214,39.3814510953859));
#737=CARTESIAN_POINT('',(-8.05058400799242,-23.6642819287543,39.6429036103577));
#738=CARTESIAN_POINT('',(-8.03680567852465,-23.6529206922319,40.1657037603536));
#739=CARTESIAN_POINT('',(-8.02645218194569,-23.644400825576,40.4270511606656));
#740=CARTESIAN_POINT('',(-7.99874254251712,-23.6217180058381,40.9492493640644));
#741=CARTESIAN_POINT('',(-7.98138322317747,-23.6075524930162,41.2100998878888));
#742=CARTESIAN_POINT('',(-7.9395120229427,-23.5736483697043,41.7309098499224));
#743=CARTESIAN_POINT('',(-7.91499890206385,-23.5539087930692,41.9908691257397));
#744=CARTESIAN_POINT('',(-7.85813899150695,-23.5085758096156,42.5139352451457));
#745=CARTESIAN_POINT('',(-7.82566584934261,-23.4828883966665,42.7770202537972));
#746=CARTESIAN_POINT('',(-7.75284057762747,-23.4260015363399,43.3014519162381));
#747=CARTESIAN_POINT('',(-7.71248987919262,-23.3948030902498,43.5627988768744));
#748=CARTESIAN_POINT('',(-7.6235666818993,-23.3270786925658,44.0833343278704));
#749=CARTESIAN_POINT('',(-7.57499612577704,-23.290554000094,44.3425233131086));
#750=CARTESIAN_POINT('',(-7.46921061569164,-23.21239959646,44.8583166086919));
#751=CARTESIAN_POINT('',(-7.4119970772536,-23.1707707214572,45.1149213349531));
#752=CARTESIAN_POINT('',(-7.29354774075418,-23.0863337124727,45.6038935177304));
#753=CARTESIAN_POINT('',(-7.23304065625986,-23.0439106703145,45.8365039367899));
#754=CARTESIAN_POINT('',(-7.10388036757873,-22.9552515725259,46.2986990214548));
#755=CARTESIAN_POINT('',(-7.03522796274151,-22.9090158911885,46.528283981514));
#756=CARTESIAN_POINT('',(-6.88925242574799,-22.8130260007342,46.9839413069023));
#757=CARTESIAN_POINT('',(-6.81192934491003,-22.7632718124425,47.2100136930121));
#758=CARTESIAN_POINT('',(-6.64871738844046,-22.6610366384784,47.656145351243));
#759=CARTESIAN_POINT('',(-6.56290713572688,-22.6085825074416,47.8762394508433));
#760=CARTESIAN_POINT('',(-6.38152298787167,-22.5009742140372,48.31171737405));
#761=CARTESIAN_POINT('',(-6.28594868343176,-22.445819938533,48.5271009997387));
#762=CARTESIAN_POINT('',(-6.08428484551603,-22.3332948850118,48.9523754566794));
#763=CARTESIAN_POINT('',(-5.9781932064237,-22.2759236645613,49.1622651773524));
#764=CARTESIAN_POINT('',(-5.77290259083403,-22.1690516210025,49.5418451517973));
#765=CARTESIAN_POINT('',(-5.67539372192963,-22.1197902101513,49.7125165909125));
#766=CARTESIAN_POINT('',(-5.47196859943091,-22.0205806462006,50.0485027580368));
#767=CARTESIAN_POINT('',(-5.36605520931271,-21.9706327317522,50.2138192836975));
#768=CARTESIAN_POINT('',(-5.14534214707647,-21.8705715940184,50.5381701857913));
#769=CARTESIAN_POINT('',(-5.03054978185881,-21.8204585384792,50.697209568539));
#770=CARTESIAN_POINT('',(-4.7898711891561,-21.7199574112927,51.0101766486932));
#771=CARTESIAN_POINT('',(-4.66385836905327,-21.6695744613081,51.1640089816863));
#772=CARTESIAN_POINT('',(-4.40138832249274,-21.5698824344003,51.4631714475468));
#773=CARTESIAN_POINT('',(-4.26492226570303,-21.5205743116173,51.6084942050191));
#774=CARTESIAN_POINT('',(-3.98068758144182,-21.423813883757,51.8893521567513));
#775=CARTESIAN_POINT('',(-3.83288148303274,-21.376368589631,52.0248517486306));
#776=CARTESIAN_POINT('',(-3.67939878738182,-21.3303987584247,52.154357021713));
#777=B_SPLINE_CURVE_WITH_KNOTS('',3,(#735,#736,#737,#738,#739,#740,#741,#742,#743,#744,#745,
#746,#747,#748,#749,#750,#751,#752,#753,#754,#755,#756,#757,#758,#759,#760,#761,#762,#763,#764,
#765,#766,#767,#768,#769,#770,#771,#772,#773,#774,#775,#776),.UNSPECIFIED.,.F.,.F.,(4,2,2,2,2,2,
2,2,2,2,2,2,2,2,2,2,2,2,2,2,4),(0.,0.784317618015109,1.56923751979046,2.3545137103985,
3.13992609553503,3.93872016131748,4.73736924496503,5.53582983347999,6.33415979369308,
7.06618574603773,7.79813991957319,8.53008976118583,9.25580121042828,9.98154309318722,
10.7074305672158,11.3151331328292,11.922629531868,12.529631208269,13.1446569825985,
13.7602081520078,14.3778889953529),.UNSPECIFIED.);
#778=EDGE_CURVE('E683',#732,#574,#777,.T.);
#779=ORIENTED_EDGE('',*,*,#778,.T.);
#780=ORIENTED_EDGE('',*,*,#575,.T.);
#781=CARTESIAN_POINT('',(-19.2062943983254,-9.98209106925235,52.154357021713));
#782=CARTESIAN_POINT('',(-19.203205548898,-10.1591956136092,52.0111692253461));
#783=CARTESIAN_POINT('',(-19.2039304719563,-10.3302216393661,51.8606855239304));
#784=CARTESIAN_POINT('',(-19.2116434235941,-10.6596530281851,51.5479752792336));
#785=CARTESIAN_POINT('',(-19.2186041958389,-10.8181100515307,51.385802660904));
#786=CARTESIAN_POINT('',(-19.2374109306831,-11.1233120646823,51.051459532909));
#787=CARTESIAN_POINT('',(-19.2492516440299,-11.2700694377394,50.8792999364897));
#788=CARTESIAN_POINT('',(-19.2765126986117,-11.5505752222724,50.5288764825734));
#789=CARTESIAN_POINT('',(-19.2918815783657,-11.6844747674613,50.3507291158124));
#790=CARTESIAN_POINT('',(-19.3253684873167,-11.942121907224,49.9872342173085));
#791=CARTESIAN_POINT('',(-19.3434893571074,-12.0658588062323,49.801879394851));
#792=CARTESIAN_POINT('',(-19.3816753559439,-12.3035710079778,49.4251071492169));
#793=CARTESIAN_POINT('',(-19.4017414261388,-12.4175415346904,49.2336868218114));
#794=CARTESIAN_POINT('',(-19.4515144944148,-12.6805181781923,48.7669664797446));
#795=CARTESIAN_POINT('',(-19.481828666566,-12.8249672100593,48.4891581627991));
#796=CARTESIAN_POINT('',(-19.5432949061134,-13.0966089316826,47.9253991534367));
#797=CARTESIAN_POINT('',(-19.574446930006,-13.2238025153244,47.6394488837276));
#798=CARTESIAN_POINT('',(-19.6362959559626,-13.4620571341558,47.0608511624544));
#799=CARTESIAN_POINT('',(-19.6669929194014,-13.5731168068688,46.7682031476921));
#800=CARTESIAN_POINT('',(-19.7271434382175,-13.7809919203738,46.1747261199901));
#801=CARTESIAN_POINT('',(-19.7565829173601,-13.8776665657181,45.8738465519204));
#802=CARTESIAN_POINT('',(-19.8130231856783,-14.0563544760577,45.2676000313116));
#803=CARTESIAN_POINT('',(-19.8400243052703,-14.1383697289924,44.9622336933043));
#804=CARTESIAN_POINT('',(-19.8908727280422,-14.2884445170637,44.347863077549));
#805=CARTESIAN_POINT('',(-19.9147202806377,-14.3565051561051,44.0388590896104));
#806=CARTESIAN_POINT('',(-19.9547050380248,-14.468113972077,43.4742558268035));
#807=CARTESIAN_POINT('',(-19.9714562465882,-14.513869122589,43.2191324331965));
#808=CARTESIAN_POINT('',(-20.0022127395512,-14.5966584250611,42.7073361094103));
#809=CARTESIAN_POINT('',(-20.0162183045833,-14.6336934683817,42.4506633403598));
#810=CARTESIAN_POINT('',(-20.0412850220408,-14.6992507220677,41.936096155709));
#811=CARTESIAN_POINT('',(-20.0523462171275,-14.7277730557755,41.678201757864));
#812=CARTESIAN_POINT('',(-20.0712389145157,-14.7761146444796,41.1651789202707));
#813=CARTESIAN_POINT('',(-20.0791140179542,-14.7960516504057,40.9100631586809));
#814=CARTESIAN_POINT('',(-20.0917526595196,-14.8279105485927,40.3992576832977));
#815=CARTESIAN_POINT('',(-20.0965162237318,-14.8398325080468,40.1435679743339));
#816=CARTESIAN_POINT('',(-20.1028797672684,-14.85571471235,39.6319183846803));
#817=CARTESIAN_POINT('',(-20.104479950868,-14.8596754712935,39.3759585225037));
#818=CARTESIAN_POINT('',(-20.1044726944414,-14.8596829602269,39.12));
#819=B_SPLINE_CURVE_WITH_KNOTS('',3,(#781,#782,#783,#784,#785,#786,#787,#788,#789,#790,#791,
#792,#793,#794,#795,#796,#797,#798,#799,#800,#801,#802,#803,#804,#805,#806,#807,#808,#809,#810,
#811,#812,#813,#814,#815,#816,#817,#818),.UNSPECIFIED.,.F.,.F.,(4,2,2,2,2,2,2,2,2,2,2,2,2,2,2,2,
2,2,4),(0.,0.682797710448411,1.36262545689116,2.04172382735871,2.71148408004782,
3.38194041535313,4.05272277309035,4.99578547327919,5.93879930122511,6.88189271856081,
7.83368276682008,8.78534364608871,9.73692921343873,10.515971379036,11.2949338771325,
12.0738850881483,12.8417832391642,13.609674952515,14.377517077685),.UNSPECIFIED.);
#820=CARTESIAN_POINT('',(-20.1044726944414,-14.8596829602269,39.12));
#821=VERTEX_POINT('',#820);
#822=EDGE_CURVE('E594',#565,#821,#819,.T.);
#823=ORIENTED_EDGE('',*,*,#822,.T.);
#824=CARTESIAN_POINT('',(-20.1044726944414,-14.8596829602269,39.12));
#825=CARTESIAN_POINT('',(-20.1044805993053,-14.8596747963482,38.8585181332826));
#826=CARTESIAN_POINT('',(-20.1028102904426,-14.8555415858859,38.5970348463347));
#827=CARTESIAN_POINT('',(-20.0961672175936,-14.8389602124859,38.0741715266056));
#828=CARTESIAN_POINT('',(-20.0911918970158,-14.8265056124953,37.8127917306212));
#829=CARTESIAN_POINT('',(-20.0779899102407,-14.7932088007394,37.2905278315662));
#830=CARTESIAN_POINT('',(-20.0697617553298,-14.772362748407,37.0296440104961));
#831=CARTESIAN_POINT('',(-20.0501663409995,-14.7221613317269,36.5087672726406));
#832=CARTESIAN_POINT('',(-20.0387985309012,-14.6928044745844,36.2487745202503));
#833=CARTESIAN_POINT('',(-20.0128663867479,-14.6248554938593,35.725706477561));
#834=CARTESIAN_POINT('',(-19.9982515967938,-14.5861166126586,35.4626527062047));
#835=CARTESIAN_POINT('',(-19.9661632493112,-14.4994604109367,34.9382840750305));
#836=CARTESIAN_POINT('',(-19.948690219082,-14.4515447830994,34.6769689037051));
#837=CARTESIAN_POINT('',(-19.9111652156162,-14.3462647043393,34.1564977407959));
#838=CARTESIAN_POINT('',(-19.89111386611,-14.288902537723,33.897341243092));
#839=CARTESIAN_POINT('',(-19.8487727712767,-14.1643950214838,33.3816156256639));
#840=CARTESIAN_POINT('',(-19.8264834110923,-14.0972513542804,33.1250460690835));
#841=CARTESIAN_POINT('',(-19.7805086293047,-13.9541261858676,32.6197243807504));
#842=CARTESIAN_POINT('',(-19.7568571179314,-13.8783334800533,32.3709157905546));
#843=CARTESIAN_POINT('',(-19.7082565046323,-13.716500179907,31.8767835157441));
#844=CARTESIAN_POINT('',(-19.6833074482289,-13.6304599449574,31.6314597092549));
#845=CARTESIAN_POINT('',(-19.6326566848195,-13.4476089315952,31.1448750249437));
#846=CARTESIAN_POINT('',(-19.6069548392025,-13.3507961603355,30.9036149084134));
#847=CARTESIAN_POINT('',(-19.5556594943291,-13.1466519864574,30.4278433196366));
#848=CARTESIAN_POINT('',(-19.5300667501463,-13.0394100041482,30.1932935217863));
#849=CARTESIAN_POINT('',(-19.4795467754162,-12.8131664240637,29.7298883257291));
#850=CARTESIAN_POINT('',(-19.4546194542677,-12.6941664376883,29.5010321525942));
#851=CARTESIAN_POINT('',(-19.4063287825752,-12.4437405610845,29.0501184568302));
#852=CARTESIAN_POINT('',(-19.3829648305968,-12.3123194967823,28.8280583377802));
#853=CARTESIAN_POINT('',(-19.3493340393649,-12.1018209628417,28.4955302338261));
#854=CARTESIAN_POINT('',(-19.3381144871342,-12.0275076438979,28.382124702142));
#855=CARTESIAN_POINT('',(-19.3165814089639,-11.8751434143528,28.1577918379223));
#856=CARTESIAN_POINT('',(-19.3062676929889,-11.7970932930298,28.0468639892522));
#857=CARTESIAN_POINT('',(-19.2867397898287,-11.6371563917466,27.827755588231));
#858=CARTESIAN_POINT('',(-19.2775252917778,-11.555270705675,27.7195742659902));
#859=CARTESIAN_POINT('',(-19.2603509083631,-11.3870059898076,27.5055474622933));
#860=CARTESIAN_POINT('',(-19.2523992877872,-11.3006019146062,27.3997209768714));
#861=CARTESIAN_POINT('',(-19.2380540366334,-11.123647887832,27.1914185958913));
#862=CARTESIAN_POINT('',(-19.2316608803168,-11.0330966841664,27.0889437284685));
#863=CARTESIAN_POINT('',(-19.2206928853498,-10.8476892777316,26.8876702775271));
#864=CARTESIAN_POINT('',(-19.2161199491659,-10.7528286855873,26.7888756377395));
#865=CARTESIAN_POINT('',(-19.212592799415,-10.655815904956,26.6921745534));
#866=B_SPLINE_CURVE_WITH_KNOTS('',3,(#824,#825,#826,#827,#828,#829,#830,#831,#832,#833,#834,
#835,#836,#837,#838,#839,#840,#841,#842,#843,#844,#845,#846,#847,#848,#849,#850,#851,#852,#853,
#854,#855,#856,#857,#858,#859,#860,#861,#862,#863,#864,#865),.UNSPECIFIED.,.F.,.F.,(4,2,2,2,2,2,
2,2,2,2,2,2,2,2,2,2,2,2,2,2,4),(0.,0.784409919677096,1.56942732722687,2.35480442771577,
3.14031936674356,3.93902056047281,4.73757457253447,5.53593576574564,6.33415980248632,
7.11745364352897,7.9007200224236,8.68413154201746,9.46133584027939,10.2384337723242,
11.0152310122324,11.4233124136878,11.831307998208,12.2391879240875,12.6496360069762,
13.0602088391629,13.471209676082),.UNSPECIFIED.);
#867=EDGE_CURVE('E596',#821,#693,#866,.T.);
#868=ORIENTED_EDGE('',*,*,#867,.T.);
#869=EDGE_LOOP('',(#695,#734,#779,#780,#823,#868));
#870=FACE_BOUND('',#869,.T.);
#871=ADVANCED_FACE('F572',(#870),#684,.F.);
#872=CARTESIAN_POINT('',(-31.7043573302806,-10.2021432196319,0.));
#873=DIRECTION('',(0.,0.,-1.));
#874=DIRECTION('',(-1.,0.,0.));
#875=AXIS2_PLACEMENT_3D('',#872,#873,#874);
#876=CYLINDRICAL_SURFACE('',#875,12.5);
#877=CARTESIAN_POINT('',(-24.4817349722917,-1.34004471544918E-13,33.8552385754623));
#878=CARTESIAN_POINT('',(-24.5160685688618,0.0243030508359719,34.0279348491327));
#879=CARTESIAN_POINT('',(-24.5487159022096,0.047158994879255,34.2011674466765));
#880=CARTESIAN_POINT('',(-24.6105453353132,0.0900510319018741,34.5481747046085));
#881=CARTESIAN_POINT('',(-24.6397353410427,0.110093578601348,34.721947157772));
#882=CARTESIAN_POINT('',(-24.6946709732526,0.147513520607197,35.0700139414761));
#883=CARTESIAN_POINT('',(-24.7204223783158,0.164895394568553,35.244306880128));
#884=CARTESIAN_POINT('',(-24.7684962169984,0.197119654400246,35.5934002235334));
#885=CARTESIAN_POINT('',(-24.7908224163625,0.211964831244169,35.7681998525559));
#886=CARTESIAN_POINT('',(-24.8320550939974,0.239220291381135,36.118294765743));
#887=CARTESIAN_POINT('',(-24.850963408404,0.251631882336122,36.2935897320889));
#888=CARTESIAN_POINT('',(-24.8853622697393,0.27410268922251,36.6446485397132));
#889=CARTESIAN_POINT('',(-24.9008531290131,0.284162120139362,36.8204123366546));
#890=CARTESIAN_POINT('',(-24.9284184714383,0.301995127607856,37.1724287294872));
#891=CARTESIAN_POINT('',(-24.9404909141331,0.309767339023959,37.3486815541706));
#892=CARTESIAN_POINT('',(-24.9612121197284,0.323071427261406,37.7016751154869));
#893=CARTESIAN_POINT('',(-24.9698569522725,0.328600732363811,37.8784161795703));
#894=CARTESIAN_POINT('',(-24.9837099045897,0.337447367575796,38.2323862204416));
#895=CARTESIAN_POINT('',(-24.9889122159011,0.340760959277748,38.4096155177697));
#896=CARTESIAN_POINT('',(-24.9958620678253,0.34518315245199,38.7645631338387));
#897=CARTESIAN_POINT('',(-24.9976019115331,0.346286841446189,38.9422816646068));
#898=CARTESIAN_POINT('',(-24.9976015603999,0.346289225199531,39.12));
#899=B_SPLINE_CURVE_WITH_KNOTS('',3,(#877,#878,#879,#880,#881,#882,#883,#884,#885,#886,#887,
#888,#889,#890,#891,#892,#893,#894,#895,#896,#897,#898),.UNSPECIFIED.,.F.,.F.,(4,2,2,2,2,2,2,2,
2,2,4),(0.,0.533217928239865,1.0651919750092,1.59626047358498,2.12674085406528,2.65693540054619,
3.18708146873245,3.71754331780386,4.24861168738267,4.78057384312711,5.31371721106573),.UNSPECIFIED.);
#900=CARTESIAN_POINT('',(-24.4817349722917,-1.19946775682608E-13,33.8552385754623));
#901=VERTEX_POINT('',#900);
#902=CARTESIAN_POINT('',(-24.9976015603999,0.346289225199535,39.12));
#903=VERTEX_POINT('',#902);
#904=EDGE_CURVE('E640',#901,#903,#899,.T.);
#905=ORIENTED_EDGE('',*,*,#904,.F.);
#906=CARTESIAN_POINT('',(-21.8214382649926,-2.54852245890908,26.6921745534));
#907=CARTESIAN_POINT('',(-21.9048210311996,-2.44087682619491,26.8278248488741));
#908=CARTESIAN_POINT('',(-21.9873875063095,-2.33787041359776,26.9675597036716));
#909=CARTESIAN_POINT('',(-22.1501967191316,-2.14085382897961,27.253680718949));
#910=CARTESIAN_POINT('',(-22.2304464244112,-2.04681416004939,27.4000425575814));
#911=CARTESIAN_POINT('',(-22.3883922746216,-1.86685187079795,27.6986253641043));
#912=CARTESIAN_POINT('',(-22.4660919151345,-1.78091780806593,27.8508376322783));
#913=CARTESIAN_POINT('',(-22.618740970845,-1.61644778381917,28.1604758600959));
#914=CARTESIAN_POINT('',(-22.6936910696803,-1.53790997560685,28.3179005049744));
#915=CARTESIAN_POINT('',(-22.8392039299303,-1.3891033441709,28.6342376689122));
#916=CARTESIAN_POINT('',(-22.9098233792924,-1.31870442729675,28.7930631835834));
#917=CARTESIAN_POINT('',(-23.0480646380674,-1.18394383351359,29.1146607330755));
#918=CARTESIAN_POINT('',(-23.1156845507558,-1.11958594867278,29.2774351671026));
#919=CARTESIAN_POINT('',(-23.2477600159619,-0.99648659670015,29.6064399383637));
#920=CARTESIAN_POINT('',(-23.3122142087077,-0.937747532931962,29.7726717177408));
#921=CARTESIAN_POINT('',(-23.4378028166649,-0.825514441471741,30.1081138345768));
#922=CARTESIAN_POINT('',(-23.4989374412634,-0.772020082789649,30.2773239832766));
#923=CARTESIAN_POINT('',(-23.6213738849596,-0.666825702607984,30.6286655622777));
#924=CARTESIAN_POINT('',(-23.6824638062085,-0.615428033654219,30.8109612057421));
#925=CARTESIAN_POINT('',(-23.8006840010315,-0.517731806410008,31.1780915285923));
#926=CARTESIAN_POINT('',(-23.8578158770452,-0.471431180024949,31.3629251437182));
#927=CARTESIAN_POINT('',(-23.9680619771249,-0.383553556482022,31.7348738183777));
#928=CARTESIAN_POINT('',(-24.0211766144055,-0.341976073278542,31.9219886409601));
#929=CARTESIAN_POINT('',(-24.1241429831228,-0.262593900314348,32.3012434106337));
#930=CARTESIAN_POINT('',(-24.1739291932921,-0.224859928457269,32.4934159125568));
#931=CARTESIAN_POINT('',(-24.269239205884,-0.153632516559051,32.8796107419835));
#932=CARTESIAN_POINT('',(-24.3147626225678,-0.120139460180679,33.0736332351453));
#933=CARTESIAN_POINT('',(-24.4014958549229,-0.0571419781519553,33.4632867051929));
#934=CARTESIAN_POINT('',(-24.4427056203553,-0.0276375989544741,33.6589177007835));
#935=CARTESIAN_POINT('',(-24.4817349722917,-1.03057416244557E-13,33.8552385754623));
#936=B_SPLINE_CURVE_WITH_KNOTS('',3,(#906,#907,#908,#909,#910,#911,#912,#913,#914,#915,#916,
#917,#918,#919,#920,#921,#922,#923,#924,#925,#926,#927,#928,#929,#930,#931,#932,#933,#934,#935),
.UNSPECIFIED.,.F.,.F.,(4,2,2,2,2,2,2,2,2,2,2,2,2,2,4),(0.,0.57640128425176,1.15083582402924,
1.7244469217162,2.29791441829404,2.86034060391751,3.42311750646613,3.98613406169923,
4.54911506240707,5.14601948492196,5.7426808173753,6.33928069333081,6.94539217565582,
7.55155845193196,8.15773178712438),.UNSPECIFIED.);
#937=CARTESIAN_POINT('',(-21.8214382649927,-2.54852245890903,26.6921745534));
#938=VERTEX_POINT('',#937);
#939=EDGE_CURVE('E647',#938,#901,#936,.T.);
#940=ORIENTED_EDGE('',*,*,#939,.F.);
#941=CARTESIAN_POINT('',(-19.212592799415,-10.6558159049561,26.6921745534));
#942=CARTESIAN_POINT('',(-19.2070889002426,-10.5033070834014,26.540275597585));
#943=CARTESIAN_POINT('',(-19.2041857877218,-10.3472684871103,26.391610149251));
#944=CARTESIAN_POINT('',(-19.2045472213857,-10.0266901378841,26.1024499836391));
#945=CARTESIAN_POINT('',(-19.2078367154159,-9.86211860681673,25.9619906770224));
#946=CARTESIAN_POINT('',(-19.2217496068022,-9.52081730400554,25.6894683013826));
#947=CARTESIAN_POINT('',(-19.2325207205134,-9.34390839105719,25.5576339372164));
#948=CARTESIAN_POINT('',(-19.2628488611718,-8.98065761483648,25.3093271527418));
#949=CARTESIAN_POINT('',(-19.2823909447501,-8.79433227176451,25.1928290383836));
#950=CARTESIAN_POINT('',(-19.3348925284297,-8.38729174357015,24.9657889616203));
#951=CARTESIAN_POINT('',(-19.3692506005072,-8.16522950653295,24.8579237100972));
#952=CARTESIAN_POINT('',(-19.4528909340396,-7.71131718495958,24.6759106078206));
#953=CARTESIAN_POINT('',(-19.5020870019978,-7.47953011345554,24.6015740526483));
#954=CARTESIAN_POINT('',(-19.588084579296,-7.12627121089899,24.5204308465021));
#955=CARTESIAN_POINT('',(-19.6190357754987,-7.00676194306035,24.4983999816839));
#956=CARTESIAN_POINT('',(-19.6849000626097,-6.7673180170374,24.4655517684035));
#957=CARTESIAN_POINT('',(-19.7198112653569,-6.64738358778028,24.4547291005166));
#958=CARTESIAN_POINT('',(-19.7934024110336,-6.40809119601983,24.4447055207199));
#959=CARTESIAN_POINT('',(-19.8320849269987,-6.28873368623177,24.4455125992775));
#960=CARTESIAN_POINT('',(-19.9128044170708,-6.05184570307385,24.4587107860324));
#961=CARTESIAN_POINT('',(-19.9548412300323,-5.93431514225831,24.4711013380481));
#962=CARTESIAN_POINT('',(-20.0747991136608,-5.61403793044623,24.5207084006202));
#963=CARTESIAN_POINT('',(-20.1557881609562,-5.41415769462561,24.5696193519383));
#964=CARTESIAN_POINT('',(-20.3239279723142,-5.02714591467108,24.6971774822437));
#965=CARTESIAN_POINT('',(-20.411082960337,-4.84002328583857,24.7758452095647));
#966=CARTESIAN_POINT('',(-20.6455326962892,-4.36605906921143,25.0141503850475));
#967=CARTESIAN_POINT('',(-20.7960851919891,-4.09076888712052,25.1935614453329));
#968=CARTESIAN_POINT('',(-21.0248955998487,-3.70432198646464,25.4934960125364));
#969=CARTESIAN_POINT('',(-21.1018285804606,-3.57968571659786,25.5988662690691));
#970=CARTESIAN_POINT('',(-21.256362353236,-3.33848004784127,25.8180348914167));
#971=CARTESIAN_POINT('',(-21.3339629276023,-3.22190812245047,25.9318305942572));
#972=CARTESIAN_POINT('',(-21.4800267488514,-3.00995522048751,26.1518782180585));
#973=CARTESIAN_POINT('',(-21.5484477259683,-2.91372550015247,26.257352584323));
#974=CARTESIAN_POINT('',(-21.6850427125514,-2.72708136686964,26.4720318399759));
#975=CARTESIAN_POINT('',(-21.753215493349,-2.63663362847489,26.581208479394));
#976=CARTESIAN_POINT('',(-21.8214382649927,-2.54852245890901,26.6921745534));
#977=B_SPLINE_CURVE_WITH_KNOTS('',3,(#941,#942,#943,#944,#945,#946,#947,#948,#949,#950,#951,
#952,#953,#954,#955,#956,#957,#958,#959,#960,#961,#962,#963,#964,#965,#966,#967,#968,#969,#970,
#971,#972,#973,#974,#975,#976),.UNSPECIFIED.,.F.,.F.,(4,2,2,2,2,2,2,2,2,2,2,2,2,2,2,2,2,4),(0.,
0.646116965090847,1.29484248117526,1.95675457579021,2.6175432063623,3.36301648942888,
4.10424012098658,4.47996302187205,4.85550752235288,5.23131006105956,5.60709455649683,
6.26744605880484,6.92825439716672,8.00588325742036,8.54699156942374,9.0879295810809,
9.56276198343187,10.034550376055),.UNSPECIFIED.);
#978=EDGE_CURVE('E623',#693,#938,#977,.T.);
#979=ORIENTED_EDGE('',*,*,#978,.F.);
#980=ORIENTED_EDGE('',*,*,#867,.F.);
#981=ORIENTED_EDGE('',*,*,#822,.F.);
#982=ORIENTED_EDGE('',*,*,#566,.F.);
#983=ORIENTED_EDGE('',*,*,#276,.F.);
#984=CARTESIAN_POINT('',(-24.9976015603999,0.346289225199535,39.12));
#985=CARTESIAN_POINT('',(-24.9976019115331,0.346286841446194,39.2977183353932));
#986=CARTESIAN_POINT('',(-24.9958620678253,0.345183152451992,39.4754368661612));
#987=CARTESIAN_POINT('',(-24.9889122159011,0.340760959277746,39.8303844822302));
#988=CARTESIAN_POINT('',(-24.9837099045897,0.337447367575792,40.0076137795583));
#989=CARTESIAN_POINT('',(-24.9698569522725,0.328600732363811,40.3615838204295));
#990=CARTESIAN_POINT('',(-24.9612121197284,0.323071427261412,40.538324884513));
#991=CARTESIAN_POINT('',(-24.9404909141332,0.309767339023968,40.8913184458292));
#992=CARTESIAN_POINT('',(-24.9284184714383,0.301995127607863,41.0675712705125));
#993=CARTESIAN_POINT('',(-24.9008531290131,0.284162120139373,41.4195876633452));
#994=CARTESIAN_POINT('',(-24.8853622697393,0.274102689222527,41.5953514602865));
#995=CARTESIAN_POINT('',(-24.8509634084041,0.251631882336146,41.9464102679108));
#996=CARTESIAN_POINT('',(-24.8320550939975,0.239220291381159,42.1217052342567));
#997=CARTESIAN_POINT('',(-24.7908224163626,0.2119648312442,42.4718001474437));
#998=CARTESIAN_POINT('',(-24.7684962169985,0.197119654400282,42.6465997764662));
#999=CARTESIAN_POINT('',(-24.7204223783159,0.164895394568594,42.9956931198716));
#1000=CARTESIAN_POINT('',(-24.6946709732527,0.147513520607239,43.1699860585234));
#1001=CARTESIAN_POINT('',(-24.6397353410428,0.110093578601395,43.5180528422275));
#1002=CARTESIAN_POINT('',(-24.6105453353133,0.0900510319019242,43.691825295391));
#1003=CARTESIAN_POINT('',(-24.5487159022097,0.0471589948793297,44.038832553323));
#1004=CARTESIAN_POINT('',(-24.5160685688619,0.0243030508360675,44.2120651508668));
#1005=CARTESIAN_POINT('',(-24.4817349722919,0.,44.3847614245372));
#1006=B_SPLINE_CURVE_WITH_KNOTS('',3,(#984,#985,#986,#987,#988,#989,#990,#991,#992,#993,#994,
#995,#996,#997,#998,#999,#1000,#1001,#1002,#1003,#1004,#1005),.UNSPECIFIED.,.F.,.F.,(4,2,2,2,2,
2,2,2,2,2,4),(0.,0.533143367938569,1.06510552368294,1.59617389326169,2.12663574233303,
2.65678181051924,3.1869763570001,3.71745673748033,4.24852523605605,4.78049928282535,
5.31371721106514),.UNSPECIFIED.);
#1007=EDGE_CURVE('E632',#903,#273,#1006,.T.);
#1008=ORIENTED_EDGE('',*,*,#1007,.F.);
#1009=EDGE_LOOP('',(#905,#940,#979,#980,#981,#982,#983,#1008));
#1010=FACE_BOUND('',#1009,.T.);
#1011=ADVANCED_FACE('F591',(#1010),#876,.F.);
#1012=CARTESIAN_POINT('',(2.,0.,39.12));
#1013=DIRECTION('',(0.,1.,0.));
#1014=DIRECTION('',(-1.,0.,0.));
#1015=AXIS2_PLACEMENT_3D('',#1012,#1013,#1014);
#1016=CIRCLE('',#1015,27.);
#1017=TRIMMED_CURVE('',#1016,(PARAMETER_VALUE(-1.49665434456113)),
(PARAMETER_VALUE(1.49665434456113)),.T.,.PARAMETER.);
#1018=CARTESIAN_POINT('',(0.,0.,39.12));
#1019=DIRECTION('',(0.,0.,-1.));
#1020=AXIS1_PLACEMENT('',#1018,#1019);
#1021=SURFACE_OF_REVOLUTION('',#1017,#1020);
#1022=CARTESIAN_POINT('',(0.,0.,26.6921745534));
#1023=DIRECTION('',(0.,0.,1.));
#1024=DIRECTION('',(0.,1.,0.));
#1025=AXIS2_PLACEMENT_3D('',#1022,#1023,#1024);
#1026=CIRCLE('',#1025,21.9697549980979);
#1027=CARTESIAN_POINT('',(-21.9697549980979,0.,26.6921745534));
#1028=VERTEX_POINT('',#1027);
#1029=EDGE_CURVE('E671',#938,#1028,#1026,.F.);
#1030=ORIENTED_EDGE('',*,*,#1029,.F.);
#1031=ORIENTED_EDGE('',*,*,#939,.T.);
#1032=CARTESIAN_POINT('',(2.,0.,39.12));
#1033=DIRECTION('',(0.,1.,0.));
#1034=DIRECTION('',(-1.,0.,0.));
#1035=AXIS2_PLACEMENT_3D('',#1032,#1033,#1034);
#1036=CIRCLE('',#1035,27.);
#1037=EDGE_CURVE('E667',#1028,#901,#1036,.T.);
#1038=ORIENTED_EDGE('',*,*,#1037,.F.);
#1039=EDGE_LOOP('',(#1030,#1031,#1038));
#1040=FACE_BOUND('',#1039,.T.);
#1041=ADVANCED_FACE('F614',(#1040),#1021,.F.);
#1042=CARTESIAN_POINT('',(2.,0.,39.12));
#1043=DIRECTION('',(0.,1.,0.));
#1044=DIRECTION('',(-1.,0.,0.));
#1045=AXIS2_PLACEMENT_3D('',#1042,#1043,#1044);
#1046=CIRCLE('',#1045,27.);
#1047=TRIMMED_CURVE('',#1046,(PARAMETER_VALUE(-1.49665434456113)),
(PARAMETER_VALUE(1.49665434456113)),.T.,.PARAMETER.);
#1048=CARTESIAN_POINT('',(0.,0.,39.12));
#1049=DIRECTION('',(0.,0.,-1.));
#1050=AXIS1_PLACEMENT('',#1048,#1049);
#1051=SURFACE_OF_REVOLUTION('',#1047,#1050);
#1052=ORIENTED_EDGE('',*,*,#904,.T.);
#1053=ORIENTED_EDGE('',*,*,#1007,.T.);
#1054=ORIENTED_EDGE('',*,*,#292,.T.);
#1055=ORIENTED_EDGE('',*,*,#357,.T.);
#1056=CARTESIAN_POINT('',(-15.4286041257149,15.1816356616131,52.154357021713));
#1057=CARTESIAN_POINT('',(-15.5960860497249,15.1239696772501,52.0111692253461));
#1058=CARTESIAN_POINT('',(-15.7589654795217,15.0718091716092,51.8606855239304));
#1059=CARTESIAN_POINT('',(-16.0746567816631,14.9773447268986,51.5479752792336));
#1060=CARTESIAN_POINT('',(-16.2275093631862,14.9349989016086,51.385802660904));
#1061=CARTESIAN_POINT('',(-16.523585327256,14.8585725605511,51.051459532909));
#1062=CARTESIAN_POINT('',(-16.666818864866,14.8244832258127,50.8792999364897));
#1063=CARTESIAN_POINT('',(-16.942019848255,14.7637289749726,50.5288764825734));
#1064=CARTESIAN_POINT('',(-17.0741151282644,14.7369684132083,50.3507291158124));
#1065=CARTESIAN_POINT('',(-17.3295001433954,14.6891990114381,49.9872342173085));
#1066=CARTESIAN_POINT('',(-17.4527805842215,14.6681961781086,49.801879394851));
#1067=CARTESIAN_POINT('',(-17.6906584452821,14.6310561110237,49.4251071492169));
#1068=CARTESIAN_POINT('',(-17.8052516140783,14.6149212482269,49.2336868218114));
#1069=CARTESIAN_POINT('',(-18.0707379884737,14.580993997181,48.7669664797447));
#1070=CARTESIAN_POINT('',(-18.2174847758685,14.5651872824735,48.4891581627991));
#1071=CARTESIAN_POINT('',(-18.4948255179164,14.5397032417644,47.9253991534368));
#1072=CARTESIAN_POINT('',(-18.6254203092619,14.5300255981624,47.6394488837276));
#1073=CARTESIAN_POINT('',(-18.871126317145,14.5152227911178,47.0608511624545));
#1074=CARTESIAN_POINT('',(-18.9862362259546,14.5100980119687,46.7682031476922));
#1075=CARTESIAN_POINT('',(-19.2025247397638,14.5030676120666,46.1747261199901));
#1076=CARTESIAN_POINT('',(-19.3035650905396,14.501192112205,45.8738465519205));
#1077=CARTESIAN_POINT('',(-19.4909483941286,14.4996523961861,45.2676000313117));
#1078=CARTESIAN_POINT('',(-19.5772933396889,14.4999878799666,44.9622336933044));
#1079=CARTESIAN_POINT('',(-19.7357359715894,14.5019719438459,44.3478630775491));
#1080=CARTESIAN_POINT('',(-19.8078347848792,14.5036204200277,44.0388590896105));
#1081=CARTESIAN_POINT('',(-19.9263370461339,14.5071591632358,43.4742558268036));
#1082=CARTESIAN_POINT('',(-19.9750291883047,14.5089513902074,43.2191324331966));
#1083=CARTESIAN_POINT('',(-20.0632707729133,14.512619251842,42.7073361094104));
#1084=CARTESIAN_POINT('',(-20.1028211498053,14.5144948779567,42.4506633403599));
#1085=CARTESIAN_POINT('',(-20.1729158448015,14.5180764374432,41.9360961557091));
#1086=CARTESIAN_POINT('',(-20.203460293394,14.5197823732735,41.6782017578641));
#1087=CARTESIAN_POINT('',(-20.2552740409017,14.5228120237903,41.1651789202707));
#1088=CARTESIAN_POINT('',(-20.2766688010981,14.5241408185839,40.910063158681));
#1089=CARTESIAN_POINT('',(-20.3108739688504,14.5263159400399,40.3992576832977));
#1090=CARTESIAN_POINT('',(-20.3236844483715,14.5271622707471,40.1435679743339));
#1091=CARTESIAN_POINT('',(-20.3407557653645,14.5283064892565,39.6319183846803));
#1092=CARTESIAN_POINT('',(-20.3450171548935,14.528604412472,39.3759585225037));
#1093=CARTESIAN_POINT('',(-20.3450220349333,14.5285951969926,39.12));
#1094=B_SPLINE_CURVE_WITH_KNOTS('',3,(#1056,#1057,#1058,#1059,#1060,#1061,#1062,#1063,#1064,
#1065,#1066,#1067,#1068,#1069,#1070,#1071,#1072,#1073,#1074,#1075,#1076,#1077,#1078,#1079,#1080,
#1081,#1082,#1083,#1084,#1085,#1086,#1087,#1088,#1089,#1090,#1091,#1092,#1093),.UNSPECIFIED.,
.F.,.F.,(4,2,2,2,2,2,2,2,2,2,2,2,2,2,2,2,2,2,4),(0.,0.682797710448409,1.36262545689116,
2.04172382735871,2.71148408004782,3.38194041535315,4.05272277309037,4.99578547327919,
5.93879930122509,6.88189271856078,7.83368276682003,8.78534364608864,9.73692921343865,
10.515971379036,11.2949338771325,12.0738850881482,12.8417832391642,13.609674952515,
14.377517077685),.UNSPECIFIED.);
#1095=CARTESIAN_POINT('',(-20.3450220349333,14.5285951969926,39.12));
#1096=VERTEX_POINT('',#1095);
#1097=EDGE_CURVE('E719',#349,#1096,#1094,.T.);
#1098=ORIENTED_EDGE('',*,*,#1097,.T.);
#1099=CARTESIAN_POINT('',(-20.3450220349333,14.5285951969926,39.12));
#1100=CARTESIAN_POINT('',(-20.3450167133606,14.5286052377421,38.8585181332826));
#1101=CARTESIAN_POINT('',(-20.3405696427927,14.5282939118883,38.5970348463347));
#1102=CARTESIAN_POINT('',(-20.3227469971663,14.5270999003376,38.0741715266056));
#1103=CARTESIAN_POINT('',(-20.3093645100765,14.5262167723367,37.8127917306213));
#1104=CARTESIAN_POINT('',(-20.2736177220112,14.5239502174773,37.2905278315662));
#1105=CARTESIAN_POINT('',(-20.2512493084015,14.5225665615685,37.0296440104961));
#1106=CARTESIAN_POINT('',(-20.1974496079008,14.519443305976,36.5087672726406));
#1107=CARTESIAN_POINT('',(-20.1660167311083,14.5177036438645,36.2487745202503));
#1108=CARTESIAN_POINT('',(-20.0933799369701,14.5140380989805,35.725706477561));
#1109=CARTESIAN_POINT('',(-20.0520208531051,14.5121095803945,35.4626527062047));
#1110=CARTESIAN_POINT('',(-19.9596900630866,14.5083699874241,34.9382840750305));
#1111=CARTESIAN_POINT('',(-19.9087201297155,14.506558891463,34.6769689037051));
#1112=CARTESIAN_POINT('',(-19.7969969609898,14.5034038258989,34.1564977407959));
#1113=CARTESIAN_POINT('',(-19.736246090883,14.5020597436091,33.897341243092));
#1114=CARTESIAN_POINT('',(-19.604748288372,14.5002659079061,33.3816156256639));
#1115=CARTESIAN_POINT('',(-19.5340030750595,14.4998160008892,33.1250460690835));
#1116=CARTESIAN_POINT('',(-19.3836759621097,14.5003194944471,32.6197243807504));
#1117=CARTESIAN_POINT('',(-19.3042840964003,14.5012468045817,32.3709157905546));
#1118=CARTESIAN_POINT('',(-19.1353530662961,14.5050341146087,31.8767835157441));
#1119=CARTESIAN_POINT('',(-19.0458142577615,14.5078940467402,31.6314597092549));
#1120=CARTESIAN_POINT('',(-18.8562606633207,14.5162263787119,31.1448750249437));
#1121=CARTESIAN_POINT('',(-18.756243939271,14.5216992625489,30.9036149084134));
#1122=CARTESIAN_POINT('',(-18.5462401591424,14.5359985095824,30.4278433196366));
#1123=CARTESIAN_POINT('',(-18.4363383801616,14.5447979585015,30.1932935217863));
#1124=CARTESIAN_POINT('',(-18.2055564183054,14.5666637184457,29.7298883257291));
#1125=CARTESIAN_POINT('',(-18.0846777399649,14.5797294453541,29.5010321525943));
#1126=CARTESIAN_POINT('',(-17.8315859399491,14.6111881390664,29.0501184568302));
#1127=CARTESIAN_POINT('',(-17.6993772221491,14.6295790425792,28.8280583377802));
#1128=CARTESIAN_POINT('',(-17.4887887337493,14.6626418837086,28.4955302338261));
#1129=CARTESIAN_POINT('',(-17.4146455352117,14.6749355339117,28.3821247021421));
#1130=CARTESIAN_POINT('',(-17.2630844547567,14.7015394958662,28.1577918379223));
#1131=CARTESIAN_POINT('',(-17.1856672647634,14.7158493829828,28.0468639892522));
#1132=CARTESIAN_POINT('',(-17.0275237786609,14.7467004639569,27.827755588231));
#1133=CARTESIAN_POINT('',(-16.9467984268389,14.7632410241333,27.7195742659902));
#1134=CARTESIAN_POINT('',(-16.7814619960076,14.7989038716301,27.5055474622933));
#1135=CARTESIAN_POINT('',(-16.6968296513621,14.8180417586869,27.3997209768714));
#1136=CARTESIAN_POINT('',(-16.5241034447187,14.8590804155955,27.1914185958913));
#1137=CARTESIAN_POINT('',(-16.4360085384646,14.8809820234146,27.0889437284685));
#1138=CARTESIAN_POINT('',(-16.2562863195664,14.9278448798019,26.8876702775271));
#1139=CARTESIAN_POINT('',(-16.164655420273,14.9528092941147,26.7888756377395));
#1140=CARTESIAN_POINT('',(-16.0713008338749,14.9794333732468,26.6921745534));
#1141=B_SPLINE_CURVE_WITH_KNOTS('',3,(#1099,#1100,#1101,#1102,#1103,#1104,#1105,#1106,#1107,
#1108,#1109,#1110,#1111,#1112,#1113,#1114,#1115,#1116,#1117,#1118,#1119,#1120,#1121,#1122,#1123,
#1124,#1125,#1126,#1127,#1128,#1129,#1130,#1131,#1132,#1133,#1134,#1135,#1136,#1137,#1138,#1139,
#1140),.UNSPECIFIED.,.F.,.F.,(4,2,2,2,2,2,2,2,2,2,2,2,2,2,2,2,2,2,2,2,4),(0.,0.784409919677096,
1.56942732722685,2.35480442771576,3.14031936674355,3.93902056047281,4.73757457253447,
5.53593576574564,6.33415980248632,7.11745364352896,7.9007200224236,8.68413154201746,
9.46133584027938,10.2384337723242,11.0152310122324,11.4233124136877,11.831307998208,
12.2391879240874,12.6496360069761,13.0602088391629,13.471209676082),.UNSPECIFIED.);
#1142=CARTESIAN_POINT('',(-16.0713008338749,14.9794333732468,26.6921745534));
#1143=VERTEX_POINT('',#1142);
#1144=EDGE_CURVE('E733',#1096,#1143,#1141,.T.);
#1145=ORIENTED_EDGE('',*,*,#1144,.T.);
#1146=CARTESIAN_POINT('',(0.,0.,26.6921745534));
#1147=DIRECTION('',(0.,0.,1.));
#1148=DIRECTION('',(0.,1.,0.));
#1149=AXIS2_PLACEMENT_3D('',#1146,#1147,#1148);
#1150=CIRCLE('',#1149,21.9697549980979);
#1151=EDGE_CURVE('E673',#1028,#1143,#1150,.F.);
#1152=ORIENTED_EDGE('',*,*,#1151,.F.);
#1153=ORIENTED_EDGE('',*,*,#1037,.T.);
#1154=EDGE_LOOP('',(#1052,#1053,#1054,#1055,#1098,#1145,#1152,#1153));
#1155=FACE_BOUND('',#1154,.T.);
#1156=ADVANCED_FACE('F712',(#1155),#1051,.F.);
#1157=CARTESIAN_POINT('',(-19.5,27.,0.));
#1158=DIRECTION('',(0.,0.,-1.));
#1159=DIRECTION('',(-1.,0.,0.));
#1160=AXIS2_PLACEMENT_3D('',#1157,#1158,#1159);
#1161=CYLINDRICAL_SURFACE('',#1160,12.5);
#1162=CARTESIAN_POINT('',(-9.16698415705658,19.9658843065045,26.6921745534));
#1163=CARTESIAN_POINT('',(-9.11617158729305,20.0405316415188,26.7821243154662));
#1164=CARTESIAN_POINT('',(-9.06719557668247,20.1142106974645,26.8738806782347));
#1165=CARTESIAN_POINT('',(-8.97270619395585,20.2595542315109,27.0606740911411));
#1166=CARTESIAN_POINT('',(-8.9271920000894,20.3312191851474,27.1557103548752));
#1167=CARTESIAN_POINT('',(-8.79583623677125,20.542574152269,27.4445484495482));
#1168=CARTESIAN_POINT('',(-8.71478634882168,20.6792109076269,27.6427903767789));
#1169=CARTESIAN_POINT('',(-8.56402691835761,20.9437924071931,28.0487629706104));
#1170=CARTESIAN_POINT('',(-8.49430688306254,21.0717451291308,28.2564846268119));
#1171=CARTESIAN_POINT('',(-8.36529279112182,21.317799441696,28.6779738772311));
#1172=CARTESIAN_POINT('',(-8.30590655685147,21.4359825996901,28.89166592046));
#1173=CARTESIAN_POINT('',(-8.19549279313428,21.6638812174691,29.3258636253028));
#1174=CARTESIAN_POINT('',(-8.14447306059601,21.7735887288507,29.5463754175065));
#1175=CARTESIAN_POINT('',(-8.0497677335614,21.9844706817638,29.9930811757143));
#1176=CARTESIAN_POINT('',(-8.00608539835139,22.0856413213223,30.2192776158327));
#1177=CARTESIAN_POINT('',(-7.90839070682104,22.3195422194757,30.7709959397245));
#1178=CARTESIAN_POINT('',(-7.8575805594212,22.448014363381,31.0988970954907));
#1179=CARTESIAN_POINT('',(-7.76655880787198,22.6880621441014,31.7622021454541));
#1180=CARTESIAN_POINT('',(-7.72634701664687,22.7996380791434,32.0976059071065));
#1181=CARTESIAN_POINT('',(-7.65470977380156,23.0061248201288,32.7744623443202));
#1182=CARTESIAN_POINT('',(-7.62328560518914,23.1010331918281,33.1159158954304));
#1183=CARTESIAN_POINT('',(-7.56764759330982,23.2747725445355,33.8052091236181));
#1184=CARTESIAN_POINT('',(-7.54346918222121,23.353523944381,34.1530716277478));
#1185=CARTESIAN_POINT('',(-7.50137087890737,23.4945314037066,34.8524215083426));
#1186=CARTESIAN_POINT('',(-7.48344981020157,23.55679056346,35.2039081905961));
#1187=CARTESIAN_POINT('',(-7.45298346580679,23.664953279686,35.9094862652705));
#1188=CARTESIAN_POINT('',(-7.4404364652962,23.7108620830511,36.2635767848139));
#1189=CARTESIAN_POINT('',(-7.41830656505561,23.7930030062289,37.0351158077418));
#1190=CARTESIAN_POINT('',(-7.40961280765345,23.8261841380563,37.4529209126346));
#1191=CARTESIAN_POINT('',(-7.40100858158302,23.8592181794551,38.0792235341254));
#1192=CARTESIAN_POINT('',(-7.39887971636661,23.8674400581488,38.2872875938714));
#1193=CARTESIAN_POINT('',(-7.39604863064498,23.8784008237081,38.7035637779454));
#1194=CARTESIAN_POINT('',(-7.39534636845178,23.8811398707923,38.911775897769));
#1195=CARTESIAN_POINT('',(-7.3953430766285,23.8811411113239,39.12));
#1196=B_SPLINE_CURVE_WITH_KNOTS('',3,(#1162,#1163,#1164,#1165,#1166,#1167,#1168,#1169,#1170,
#1171,#1172,#1173,#1174,#1175,#1176,#1177,#1178,#1179,#1180,#1181,#1182,#1183,#1184,#1185,#1186,
#1187,#1188,#1189,#1190,#1191,#1192,#1193,#1194,#1195),.UNSPECIFIED.,.F.,.F.,(4,2,2,2,2,2,2,2,2,
2,2,2,2,2,2,2,4),(0.,0.382298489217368,0.764505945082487,1.52592099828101,2.28662682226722,
3.04015413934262,3.79437974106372,4.54893949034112,5.61564914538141,6.68233997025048,
7.74918645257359,8.82116780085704,9.89294749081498,10.9643829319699,12.2212989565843,
12.8459461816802,13.4705751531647),.UNSPECIFIED.);
#1197=CARTESIAN_POINT('',(-9.16698415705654,19.9658843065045,26.6921745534));
#1198=VERTEX_POINT('',#1197);
#1199=CARTESIAN_POINT('',(-7.3953430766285,23.8811411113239,39.12));
#1200=VERTEX_POINT('',#1199);
#1201=EDGE_CURVE('E728',#1198,#1200,#1196,.T.);
#1202=ORIENTED_EDGE('',*,*,#1201,.F.);
#1203=CARTESIAN_POINT('',(-16.071300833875,14.9794333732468,26.6921745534));
#1204=CARTESIAN_POINT('',(-15.9245555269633,15.0213266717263,26.5402755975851));
#1205=CARTESIAN_POINT('',(-15.7752568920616,15.0667842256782,26.3916101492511));
#1206=CARTESIAN_POINT('',(-15.4704804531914,15.166192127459,26.1024499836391));
#1207=CARTESIAN_POINT('',(-15.3149801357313,15.2201760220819,25.9619906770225));
#1208=CARTESIAN_POINT('',(-14.994682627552,15.3388758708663,25.6894683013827));
#1209=CARTESIAN_POINT('',(-14.8297607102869,15.4037876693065,25.5576339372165));
#1210=CARTESIAN_POINT('',(-14.4936606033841,15.5448821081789,25.3093271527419));
#1211=CARTESIAN_POINT('',(-14.3224935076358,15.6210454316,25.1928290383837));
#1212=CARTESIAN_POINT('',(-13.9515988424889,15.7967598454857,24.9657889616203));
#1213=CARTESIAN_POINT('',(-13.7510223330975,15.8980573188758,24.8579237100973));
#1214=CARTESIAN_POINT('',(-13.3451723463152,16.1178706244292,24.6759106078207));
#1215=CARTESIAN_POINT('',(-13.1399321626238,16.2362850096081,24.6015740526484));
#1216=CARTESIAN_POINT('',(-12.8305376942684,16.4272365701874,24.5204308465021));
#1217=CARTESIAN_POINT('',(-12.7264420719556,16.4936033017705,24.498399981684));
#1218=CARTESIAN_POINT('',(-12.5190705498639,16.6302362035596,24.4655517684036));
#1219=CARTESIAN_POINT('',(-12.4157942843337,16.700500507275,24.4547291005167));
#1220=CARTESIAN_POINT('',(-12.2109546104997,16.8444352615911,24.4447055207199));
#1221=CARTESIAN_POINT('',(-12.1093924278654,16.9181080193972,24.4455125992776));
#1222=CARTESIAN_POINT('',(-11.9090422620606,17.0680792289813,24.4587107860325));
#1223=CARTESIAN_POINT('',(-11.8102541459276,17.144377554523,24.4711013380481));
#1224=CARTESIAN_POINT('',(-11.5427214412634,17.3574353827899,24.5207084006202));
#1225=CARTESIAN_POINT('',(-11.3776510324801,17.4962269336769,24.5696193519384));
#1226=CARTESIAN_POINT('',(-11.061539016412,17.7757306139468,24.6971774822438));
#1227=CARTESIAN_POINT('',(-10.9105071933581,17.9164440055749,24.7758452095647));
#1228=CARTESIAN_POINT('',(-10.5321893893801,18.2858819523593,25.0141503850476));
#1229=CARTESIAN_POINT('',(-10.3168961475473,18.5141352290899,25.193561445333));
#1230=CARTESIAN_POINT('',(-10.0200696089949,18.8511655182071,25.4934960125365));
#1231=CARTESIAN_POINT('',(-9.92530707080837,18.9628478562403,25.5988662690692));
#1232=CARTESIAN_POINT('',(-9.74366040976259,19.1843548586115,25.8180348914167));
#1233=CARTESIAN_POINT('',(-9.65677381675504,19.2941800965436,25.9318305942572));
#1234=CARTESIAN_POINT('',(-9.50033083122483,19.4985920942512,26.1518782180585));
#1235=CARTESIAN_POINT('',(-9.4299541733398,19.593400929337,26.2573525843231));
#1236=CARTESIAN_POINT('',(-9.29465522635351,19.7809866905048,26.4720318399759));
#1237=CARTESIAN_POINT('',(-9.22970086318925,19.873772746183,26.581208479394));
#1238=CARTESIAN_POINT('',(-9.16698415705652,19.9658843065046,26.6921745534));
#1239=B_SPLINE_CURVE_WITH_KNOTS('',3,(#1203,#1204,#1205,#1206,#1207,#1208,#1209,#1210,#1211,
#1212,#1213,#1214,#1215,#1216,#1217,#1218,#1219,#1220,#1221,#1222,#1223,#1224,#1225,#1226,#1227,
#1228,#1229,#1230,#1231,#1232,#1233,#1234,#1235,#1236,#1237,#1238),.UNSPECIFIED.,.F.,.F.,(4,2,2,
2,2,2,2,2,2,2,2,2,2,2,2,2,2,4),(0.,0.646116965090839,1.29484248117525,1.9567545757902,
2.61754320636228,3.36301648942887,4.10424012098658,4.47996302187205,4.85550752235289,
5.23131006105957,5.60709455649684,6.26744605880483,6.92825439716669,8.00588325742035,
8.54699156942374,9.08792958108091,9.56276198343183,10.0345503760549),.UNSPECIFIED.);
#1240=EDGE_CURVE('E701',#1143,#1198,#1239,.T.);
#1241=ORIENTED_EDGE('',*,*,#1240,.F.);
#1242=ORIENTED_EDGE('',*,*,#1144,.F.);
#1243=ORIENTED_EDGE('',*,*,#1097,.F.);
#1244=ORIENTED_EDGE('',*,*,#350,.F.);
#1245=CARTESIAN_POINT('',(-7.39534307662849,23.8811411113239,39.12));
#1246=CARTESIAN_POINT('',(-7.3953542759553,23.8811392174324,39.3814510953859));
#1247=CARTESIAN_POINT('',(-7.396456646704,23.8768207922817,39.6429036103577));
#1248=CARTESIAN_POINT('',(-7.40092558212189,23.8595306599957,40.1657037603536));
#1249=CARTESIAN_POINT('',(-7.40429388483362,23.8465523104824,40.4270511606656));
#1250=CARTESIAN_POINT('',(-7.41337882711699,23.8119142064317,40.9492493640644));
#1251=CARTESIAN_POINT('',(-7.41909653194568,23.7902505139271,41.2100998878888));
#1252=CARTESIAN_POINT('',(-7.43304270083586,23.7382102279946,41.7309098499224));
#1253=CARTESIAN_POINT('',(-7.44127160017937,23.7078321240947,41.9908691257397));
#1254=CARTESIAN_POINT('',(-7.46062617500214,23.6377355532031,42.5139352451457));
#1255=CARTESIAN_POINT('',(-7.47179881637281,23.5978667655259,42.7770202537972));
#1256=CARTESIAN_POINT('',(-7.4972784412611,23.5090387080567,43.3014519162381));
#1257=CARTESIAN_POINT('',(-7.5115848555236,23.460081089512,43.5627988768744));
#1258=CARTESIAN_POINT('',(-7.54371783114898,23.3530231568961,44.0833343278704));
#1259=CARTESIAN_POINT('',(-7.56154356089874,23.2949250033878,44.3425233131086));
#1260=CARTESIAN_POINT('',(-7.60118783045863,23.1695175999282,44.8583166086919));
#1261=CARTESIAN_POINT('',(-7.62300571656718,23.1022098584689,45.1149213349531));
#1262=CARTESIAN_POINT('',(-7.6692024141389,22.9642761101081,45.6038935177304));
#1263=CARTESIAN_POINT('',(-7.69321803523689,22.894389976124,45.8365039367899));
#1264=CARTESIAN_POINT('',(-7.74559839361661,22.7467447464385,46.2986990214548));
#1265=CARTESIAN_POINT('',(-7.77396270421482,22.6689864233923,46.528283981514));
#1266=CARTESIAN_POINT('',(-7.83563795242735,22.5055267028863,46.9839413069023));
#1267=CARTESIAN_POINT('',(-7.86894886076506,22.4198253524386,47.2100136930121));
#1268=CARTESIAN_POINT('',(-7.94089777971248,22.2411817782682,47.656145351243));
#1269=CARTESIAN_POINT('',(-7.97948796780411,22.1483074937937,47.8762394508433));
#1270=CARTESIAN_POINT('',(-8.06298025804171,21.9546356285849,48.31171737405));
#1271=CARTESIAN_POINT('',(-8.10788262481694,21.8538377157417,48.5271009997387));
#1272=CARTESIAN_POINT('',(-8.20489152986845,21.6442680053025,48.9523754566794));
#1273=CARTESIAN_POINT('',(-8.2569995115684,21.53549461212,49.1622651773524));
#1274=CARTESIAN_POINT('',(-8.36026529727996,21.3283665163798,49.5418451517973));
#1275=CARTESIAN_POINT('',(-8.4101964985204,21.2311989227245,49.7125165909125));
#1276=CARTESIAN_POINT('',(-8.51645696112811,21.0313664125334,50.0485027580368));
#1277=CARTESIAN_POINT('',(-8.57278404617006,20.9287033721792,50.2138192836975));
#1278=CARTESIAN_POINT('',(-8.69253020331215,20.7180203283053,50.5381701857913));
#1279=CARTESIAN_POINT('',(-8.75594346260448,20.6100047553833,50.697209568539));
#1280=CARTESIAN_POINT('',(-8.89158345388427,20.3872303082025,51.0101766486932));
#1281=CARTESIAN_POINT('',(-8.96391561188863,20.272401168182,51.1640089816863));
#1282=CARTESIAN_POINT('',(-9.11766083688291,20.0374726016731,51.4631714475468));
#1283=CARTESIAN_POINT('',(-9.19908160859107,19.9173687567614,51.6084942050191));
#1284=CARTESIAN_POINT('',(-9.3721579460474,19.6720189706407,51.8893521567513));
#1285=CARTESIAN_POINT('',(-9.46384794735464,19.5467566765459,52.0248517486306));
#1286=CARTESIAN_POINT('',(-9.56099766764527,19.4193514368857,52.154357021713));
#1287=B_SPLINE_CURVE_WITH_KNOTS('',3,(#1245,#1246,#1247,#1248,#1249,#1250,#1251,#1252,#1253,
#1254,#1255,#1256,#1257,#1258,#1259,#1260,#1261,#1262,#1263,#1264,#1265,#1266,#1267,#1268,#1269,
#1270,#1271,#1272,#1273,#1274,#1275,#1276,#1277,#1278,#1279,#1280,#1281,#1282,#1283,#1284,#1285,
#1286),.UNSPECIFIED.,.F.,.F.,(4,2,2,2,2,2,2,2,2,2,2,2,2,2,2,2,2,2,2,2,4),(0.,0.784317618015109,
1.56923751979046,2.35451371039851,3.13992609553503,3.93872016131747,4.73736924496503,
5.53582983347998,6.33415979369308,7.06618574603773,7.79813991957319,8.53008976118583,
9.25580121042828,9.98154309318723,10.7074305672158,11.3151331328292,11.922629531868,
12.529631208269,13.1446569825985,13.7602081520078,14.3778889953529),.UNSPECIFIED.);
#1288=EDGE_CURVE('E359',#1200,#347,#1287,.T.);
#1289=ORIENTED_EDGE('',*,*,#1288,.F.);
#1290=EDGE_LOOP('',(#1202,#1241,#1242,#1243,#1244,#1289));
#1291=FACE_BOUND('',#1290,.T.);
#1292=ADVANCED_FACE('F708',(#1291),#1161,.F.);
#1293=CARTESIAN_POINT('',(0.,3.875,0.));
#1294=DIRECTION('',(0.,0.,-1.));
#1295=DIRECTION('',(-1.,0.,0.));
#1296=AXIS2_PLACEMENT_3D('',#1293,#1294,#1295);
#1297=PLANE('',#1296);
#1298=CARTESIAN_POINT('',(0.,0.,0.));
#1299=DIRECTION('',(0.,0.,-1.));
#1300=DIRECTION('',(-1.,0.,0.));
#1301=AXIS2_PLACEMENT_3D('',#1298,#1299,#1300);
#1302=CIRCLE('',#1301,4.5000000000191);
#1303=CARTESIAN_POINT('',(-4.5000000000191,0.,0.));
#1304=VERTEX_POINT('',#1303);
#1305=EDGE_CURVE('E23',#1304,#1304,#1302,.F.);
#1306=ORIENTED_EDGE('',*,*,#1305,.T.);
#1307=EDGE_LOOP('',(#1306));
#1308=FACE_BOUND('',#1307,.T.);
#1309=CARTESIAN_POINT('',(0.,0.,0.));
#1310=DIRECTION('',(0.,0.,1.));
#1311=DIRECTION('',(1.,0.,0.));
#1312=AXIS2_PLACEMENT_3D('',#1309,#1310,#1311);
#1313=CIRCLE('',#1312,7.75);
#1314=CARTESIAN_POINT('',(0.,-7.75,0.));
#1315=VERTEX_POINT('',#1314);
#1316=CARTESIAN_POINT('',(0.,7.75,0.));
#1317=VERTEX_POINT('',#1316);
#1318=EDGE_CURVE('E487',#1315,#1317,#1313,.T.);
#1319=ORIENTED_EDGE('',*,*,#1318,.F.);
#1320=CARTESIAN_POINT('',(0.,0.,0.));
#1321=DIRECTION('',(0.,0.,1.));
#1322=DIRECTION('',(1.,0.,0.));
#1323=AXIS2_PLACEMENT_3D('',#1320,#1321,#1322);
#1324=CIRCLE('',#1323,7.75);
#1325=EDGE_CURVE('E304',#1317,#1315,#1324,.T.);
#1326=ORIENTED_EDGE('',*,*,#1325,.F.);
#1327=EDGE_LOOP('',(#1319,#1326));
#1328=FACE_BOUND('',#1327,.T.);
#1329=ADVANCED_FACE('F711',(#1308,#1328),#1297,.T.);
#1330=CARTESIAN_POINT('',(2.,0.,39.12));
#1331=DIRECTION('',(0.,1.,0.));
#1332=DIRECTION('',(-1.,0.,0.));
#1333=AXIS2_PLACEMENT_3D('',#1330,#1331,#1332);
#1334=CIRCLE('',#1333,27.);
#1335=TRIMMED_CURVE('',#1334,(PARAMETER_VALUE(-1.49665434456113)),
(PARAMETER_VALUE(1.49665434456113)),.T.,.PARAMETER.);
#1336=CARTESIAN_POINT('',(0.,0.,39.12));
#1337=DIRECTION('',(0.,0.,-1.));
#1338=AXIS1_PLACEMENT('',#1336,#1337);
#1339=SURFACE_OF_REVOLUTION('',#1335,#1338);
#1340=ORIENTED_EDGE('',*,*,#1288,.T.);
#1341=ORIENTED_EDGE('',*,*,#434,.T.);
#1342=CARTESIAN_POINT('',(9.67089264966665,19.3648579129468,52.154357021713));
#1343=CARTESIAN_POINT('',(9.5642942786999,19.5063229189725,52.011169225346));
#1344=CARTESIAN_POINT('',(9.46435417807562,19.645111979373,51.8606855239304));
#1345=CARTESIAN_POINT('',(9.2769591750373,19.9161611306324,51.5479752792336));
#1346=CARTESIAN_POINT('',(9.18945185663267,20.0484469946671,51.385802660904));
#1347=CARTESIAN_POINT('',(9.02527358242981,20.3064149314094,51.0514595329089));
#1348=CARTESIAN_POINT('',(8.94859110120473,20.4321039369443,50.8792999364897));
#1349=CARTESIAN_POINT('',(8.80576859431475,20.6750615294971,50.5288764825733));
#1350=CARTESIAN_POINT('',(8.7394981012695,20.7924221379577,50.3507291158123));
#1351=CARTESIAN_POINT('',(8.6151483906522,21.020546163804,49.9872342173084));
#1352=CARTESIAN_POINT('',(8.55707775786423,21.1313025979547,49.8018793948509));
#1353=CARTESIAN_POINT('',(8.44824715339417,21.3460609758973,49.4251071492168));
#1354=CARTESIAN_POINT('',(8.39749075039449,21.4500596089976,49.2336868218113));
#1355=CARTESIAN_POINT('',(8.28318421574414,21.6920680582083,48.7669664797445));
#1356=CARTESIAN_POINT('',(8.22280388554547,21.8267480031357,48.489158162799));
#1357=CARTESIAN_POINT('',(8.11286412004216,22.08263972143,47.9253991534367));
#1358=CARTESIAN_POINT('',(8.06330412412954,22.2038521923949,47.6394488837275));
#1359=CARTESIAN_POINT('',(7.97329848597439,22.4329581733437,47.0608511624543));
#1360=CARTESIAN_POINT('',(7.93285361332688,22.5408505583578,46.768203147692));
#1361=CARTESIAN_POINT('',(7.85933047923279,22.7443806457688,46.17472611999));
#1362=CARTESIAN_POINT('',(7.82632358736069,22.8398961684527,45.8738465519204));
#1363=CARTESIAN_POINT('',(7.76695460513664,23.0176324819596,45.2676000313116));
#1364=CARTESIAN_POINT('',(7.74059161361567,23.0998550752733,44.9622336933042));
#1365=CARTESIAN_POINT('',(7.69351710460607,23.2511560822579,44.347863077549));
#1366=CARTESIAN_POINT('',(7.67280514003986,23.3202355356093,44.0388590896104));
#1367=CARTESIAN_POINT('',(7.63955147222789,23.4340314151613,43.4742558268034));
#1368=CARTESIAN_POINT('',(7.62620928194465,23.4808942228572,43.2191324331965));
#1369=CARTESIAN_POINT('',(7.60242947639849,23.5659503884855,42.7073361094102));
#1370=CARTESIAN_POINT('',(7.5919915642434,23.6041446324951,42.4506633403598));
#1371=CARTESIAN_POINT('',(7.57373737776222,23.6719154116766,41.936096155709));
#1372=CARTESIAN_POINT('',(7.56592106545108,23.7014920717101,41.678201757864));
#1373=CARTESIAN_POINT('',(7.55279110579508,23.7517060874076,41.1651789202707));
#1374=CARTESIAN_POINT('',(7.54744352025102,23.7724643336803,40.9100631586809));
#1375=CARTESIAN_POINT('',(7.53894220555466,23.8056675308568,40.3992576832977));
#1376=CARTESIAN_POINT('',(7.53578845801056,23.8181125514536,40.1435679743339));
#1377=CARTESIAN_POINT('',(7.5316013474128,23.8347019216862,39.6319183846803));
#1378=CARTESIAN_POINT('',(7.53056784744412,23.8388468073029,39.3759585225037));
#1379=CARTESIAN_POINT('',(7.53055757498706,23.8388486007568,39.12));
#1380=B_SPLINE_CURVE_WITH_KNOTS('',3,(#1342,#1343,#1344,#1345,#1346,#1347,#1348,#1349,#1350,
#1351,#1352,#1353,#1354,#1355,#1356,#1357,#1358,#1359,#1360,#1361,#1362,#1363,#1364,#1365,#1366,
#1367,#1368,#1369,#1370,#1371,#1372,#1373,#1374,#1375,#1376,#1377,#1378,#1379),.UNSPECIFIED.,
.F.,.F.,(4,2,2,2,2,2,2,2,2,2,2,2,2,2,2,2,2,2,4),(0.,0.682797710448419,1.36262545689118,
2.04172382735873,2.71148408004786,3.38194041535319,4.05272277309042,4.99578547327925,
5.93879930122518,6.88189271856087,7.83368276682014,8.78534364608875,9.73692921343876,
10.5159713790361,11.2949338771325,12.0738850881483,12.8417832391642,13.6096749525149,
14.377517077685),.UNSPECIFIED.);
#1381=CARTESIAN_POINT('',(7.53055757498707,23.8388486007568,39.12));
#1382=VERTEX_POINT('',#1381);
#1383=EDGE_CURVE('E346',#426,#1382,#1380,.T.);
#1384=ORIENTED_EDGE('',*,*,#1383,.T.);
#1385=CARTESIAN_POINT('',(7.53055757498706,23.8388486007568,39.12));
#1386=CARTESIAN_POINT('',(7.53056876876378,23.8388466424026,38.8585181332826));
#1387=CARTESIAN_POINT('',(7.53164690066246,23.834521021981,38.5970348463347));
#1388=CARTESIAN_POINT('',(7.53601882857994,23.8172017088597,38.0741715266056));
#1389=CARTESIAN_POINT('',(7.53931433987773,23.8042013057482,37.8127917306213));
#1390=CARTESIAN_POINT('',(7.54820508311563,23.7695036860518,37.2905278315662));
#1391=CARTESIAN_POINT('',(7.55380136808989,23.747802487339,37.0296440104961));
#1392=CARTESIAN_POINT('',(7.56745599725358,23.6956707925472,36.5087672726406));
#1393=CARTESIAN_POINT('',(7.57551477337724,23.6652387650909,36.2487745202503));
#1394=CARTESIAN_POINT('',(7.59447463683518,23.5950243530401,35.725706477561));
#1395=CARTESIAN_POINT('',(7.60542116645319,23.5550935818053,35.4626527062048));
#1396=CARTESIAN_POINT('',(7.63039638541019,23.4661261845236,34.9382840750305));
#1397=CARTESIAN_POINT('',(7.64442450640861,23.4170912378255,34.6769689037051));
#1398=CARTESIAN_POINT('',(7.67594821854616,23.3098612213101,34.1564977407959));
#1399=CARTESIAN_POINT('',(7.69344297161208,23.251668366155,33.897341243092));
#1400=CARTESIAN_POINT('',(7.73237198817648,23.1260521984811,33.3816156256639));
#1401=CARTESIAN_POINT('',(7.7538055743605,23.0586304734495,33.1250460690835));
#1402=CARTESIAN_POINT('',(7.80073805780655,22.9158164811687,32.6197243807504));
#1403=CARTESIAN_POINT('',(7.82615341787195,22.8405968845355,32.3709157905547));
#1404=CARTESIAN_POINT('',(7.88195792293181,22.6811042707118,31.8767835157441));
#1405=CARTESIAN_POINT('',(7.91234689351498,22.5968315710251,31.6314597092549));
#1406=CARTESIAN_POINT('',(7.97884669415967,22.419130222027,31.1448750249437));
#1407=CARTESIAN_POINT('',(8.01495858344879,22.3256998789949,30.9036149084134));
#1408=CARTESIAN_POINT('',(8.09345271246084,22.1303931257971,30.4278433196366));
#1409=CARTESIAN_POINT('',(8.13578300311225,22.0285895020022,30.1932935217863));
#1410=CARTESIAN_POINT('',(8.22789412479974,21.815859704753,29.7298883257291));
#1411=CARTESIAN_POINT('',(8.27767393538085,21.7049347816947,29.5010321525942));
#1412=CARTESIAN_POINT('',(8.38580259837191,21.4739514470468,29.0501184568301));
#1413=CARTESIAN_POINT('',(8.44414812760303,21.3538965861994,28.8280583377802));
#1414=CARTESIAN_POINT('',(8.54066817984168,21.1638320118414,28.4955302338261));
#1415=CARTESIAN_POINT('',(8.57527164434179,21.0971165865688,28.382124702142));
#1416=CARTESIAN_POINT('',(8.6474084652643,20.9611945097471,28.1577918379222));
#1417=CARTESIAN_POINT('',(8.68494120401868,20.8919883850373,28.0468639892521));
#1418=CARTESIAN_POINT('',(8.76315135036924,20.7511185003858,27.8277555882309));
#1419=CARTESIAN_POINT('',(8.80382786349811,20.6794554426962,27.7195742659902));
#1420=CARTESIAN_POINT('',(8.88883701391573,20.5332315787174,27.5055474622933));
#1421=CARTESIAN_POINT('',(8.93319105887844,20.4586553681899,27.3997209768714));
#1422=CARTESIAN_POINT('',(9.02559647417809,20.3070646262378,27.1914185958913));
#1423=CARTESIAN_POINT('',(9.0736489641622,20.2300493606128,27.0889437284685));
#1424=CARTESIAN_POINT('',(9.17375540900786,20.0736047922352,26.8876702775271));
#1425=CARTESIAN_POINT('',(9.22581348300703,19.9941730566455,26.7888756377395));
#1426=CARTESIAN_POINT('',(9.27998264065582,19.913614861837,26.6921745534));
#1427=B_SPLINE_CURVE_WITH_KNOTS('',3,(#1385,#1386,#1387,#1388,#1389,#1390,#1391,#1392,#1393,
#1394,#1395,#1396,#1397,#1398,#1399,#1400,#1401,#1402,#1403,#1404,#1405,#1406,#1407,#1408,#1409,
#1410,#1411,#1412,#1413,#1414,#1415,#1416,#1417,#1418,#1419,#1420,#1421,#1422,#1423,#1424,#1425,
#1426),.UNSPECIFIED.,.F.,.F.,(4,2,2,2,2,2,2,2,2,2,2,2,2,2,2,2,2,2,2,2,4),(0.,0.784409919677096,
1.56942732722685,2.35480442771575,3.14031936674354,3.9390205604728,4.73757457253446,
5.53593576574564,6.33415980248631,7.11745364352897,7.90072002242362,8.68413154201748,
9.46133584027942,10.2384337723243,11.0152310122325,11.4233124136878,11.831307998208,
12.2391879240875,12.6496360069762,13.0602088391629,13.471209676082),.UNSPECIFIED.);
#1428=CARTESIAN_POINT('',(9.27998264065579,19.913614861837,26.6921745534));
#1429=VERTEX_POINT('',#1428);
#1430=EDGE_CURVE('E340',#1382,#1429,#1427,.T.);
#1431=ORIENTED_EDGE('',*,*,#1430,.T.);
#1432=CARTESIAN_POINT('',(0.,0.,26.6921745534));
#1433=DIRECTION('',(0.,0.,1.));
#1434=DIRECTION('',(0.,1.,0.));
#1435=AXIS2_PLACEMENT_3D('',#1432,#1433,#1434);
#1436=CIRCLE('',#1435,21.9697549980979);
#1437=CARTESIAN_POINT('',(0.,21.9697549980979,26.6921745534));
#1438=VERTEX_POINT('',#1437);
#1439=EDGE_CURVE('E303',#1438,#1429,#1436,.F.);
#1440=ORIENTED_EDGE('',*,*,#1439,.F.);
#1441=CARTESIAN_POINT('',(0.,0.,26.6921745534));
#1442=DIRECTION('',(0.,0.,1.));
#1443=DIRECTION('',(0.,1.,0.));
#1444=AXIS2_PLACEMENT_3D('',#1441,#1442,#1443);
#1445=CIRCLE('',#1444,21.9697549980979);
#1446=EDGE_CURVE('E707',#1198,#1438,#1445,.F.);
#1447=ORIENTED_EDGE('',*,*,#1446,.F.);
#1448=ORIENTED_EDGE('',*,*,#1201,.T.);
#1449=EDGE_LOOP('',(#1340,#1341,#1384,#1431,#1440,#1447,#1448));
#1450=FACE_BOUND('',#1449,.T.);
#1451=ADVANCED_FACE('F312',(#1450),#1339,.F.);
#1452=CARTESIAN_POINT('',(19.6526945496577,26.889060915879,0.));
#1453=DIRECTION('',(0.,0.,-1.));
#1454=DIRECTION('',(-1.,0.,0.));
#1455=AXIS2_PLACEMENT_3D('',#1452,#1453,#1454);
#1456=CYLINDRICAL_SURFACE('',#1455,12.5);
#1457=ORIENTED_EDGE('',*,*,#1383,.F.);
#1458=ORIENTED_EDGE('',*,*,#427,.F.);
#1459=CARTESIAN_POINT('',(20.4270281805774,14.413067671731,39.12));
#1460=CARTESIAN_POINT('',(20.4270229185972,14.4130777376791,39.3814510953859));
#1461=CARTESIAN_POINT('',(20.4225752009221,14.4127916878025,39.6429036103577));
#1462=CARTESIAN_POINT('',(20.404750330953,14.4116989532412,40.1657037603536));
#1463=CARTESIAN_POINT('',(20.3913663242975,14.4108918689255,40.4270511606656));
#1464=CARTESIAN_POINT('',(20.3556161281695,14.4088283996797,40.9492493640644));
#1465=CARTESIAN_POINT('',(20.3332458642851,14.4075718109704,41.2100998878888));
#1466=CARTESIAN_POINT('',(20.2794430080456,14.4047540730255,41.7309098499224));
#1467=CARTESIAN_POINT('',(20.2480088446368,14.4031928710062,41.9908691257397));
#1468=CARTESIAN_POINT('',(20.1753621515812,14.3999391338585,42.5139352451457));
#1469=CARTESIAN_POINT('',(20.1339921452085,14.398244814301,42.7770202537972));
#1470=CARTESIAN_POINT('',(20.0416380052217,14.3950279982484,43.3014519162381));
#1471=CARTESIAN_POINT('',(19.9906556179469,14.3935054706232,43.5627988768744));
#1472=CARTESIAN_POINT('',(19.8789078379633,14.3909830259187,44.0833343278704));
#1473=CARTESIAN_POINT('',(19.8181447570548,14.3899829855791,44.3425233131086));
#1474=CARTESIAN_POINT('',(19.6866244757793,14.3889339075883,44.8583166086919));
#1475=CARTESIAN_POINT('',(19.6158689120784,14.3888847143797,45.1149213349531));
#1476=CARTESIAN_POINT('',(19.4704105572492,14.3901965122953,45.6038935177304));
#1477=CARTESIAN_POINT('',(19.3965236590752,14.3914407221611,45.8365039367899));
#1478=CARTESIAN_POINT('',(19.2399182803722,14.3956325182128,46.2986990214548));
#1479=CARTESIAN_POINT('',(19.1572006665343,14.3985799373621,46.528283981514));
#1480=CARTESIAN_POINT('',(18.9826825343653,14.4067247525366,46.9839413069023));
#1481=CARTESIAN_POINT('',(18.8908820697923,14.4119221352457,47.2100136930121));
#1482=CARTESIAN_POINT('',(18.6987484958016,14.4251457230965,47.656145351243));
#1483=CARTESIAN_POINT('',(18.5984947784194,14.433147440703,47.8762394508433));
#1484=CARTESIAN_POINT('',(18.3885013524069,14.4527054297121,48.31171737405));
#1485=CARTESIAN_POINT('',(18.2787612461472,14.4642618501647,48.5271009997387));
#1486=CARTESIAN_POINT('',(18.0494712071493,14.4917621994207,48.9523754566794));
#1487=CARTESIAN_POINT('',(17.9299193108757,14.5077070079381,49.1622651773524));
#1488=CARTESIAN_POINT('',(17.7010179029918,14.5419125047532,49.5418451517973));
#1489=CARTESIAN_POINT('',(17.5931764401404,14.5593734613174,49.7125165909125));
#1490=CARTESIAN_POINT('',(17.3702881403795,14.5986815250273,50.0485027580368));
#1491=CARTESIAN_POINT('',(17.2552437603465,14.6205271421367,50.2138192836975));
#1492=CARTESIAN_POINT('',(17.0178686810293,14.6693078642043,50.5381701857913));
#1493=CARTESIAN_POINT('',(16.8955439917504,14.6962388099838,50.697209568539));
#1494=CARTESIAN_POINT('',(16.6417578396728,14.7563990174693,51.0101766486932));
#1495=CARTESIAN_POINT('',(16.5101969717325,14.7897068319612,51.1640089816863));
#1496=CARTESIAN_POINT('',(16.2392567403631,14.8633303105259,51.4631714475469));
#1497=CARTESIAN_POINT('',(16.0998707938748,14.9036519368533,51.6084942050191));
#1498=CARTESIAN_POINT('',(15.8130457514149,14.99244006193,51.8893521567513));
#1499=CARTESIAN_POINT('',(15.6655804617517,15.0409342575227,52.0248517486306));
#1500=CARTESIAN_POINT('',(15.5143899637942,15.093958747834,52.154357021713));
#1501=B_SPLINE_CURVE_WITH_KNOTS('',3,(#1459,#1460,#1461,#1462,#1463,#1464,#1465,#1466,#1467,
#1468,#1469,#1470,#1471,#1472,#1473,#1474,#1475,#1476,#1477,#1478,#1479,#1480,#1481,#1482,#1483,
#1484,#1485,#1486,#1487,#1488,#1489,#1490,#1491,#1492,#1493,#1494,#1495,#1496,#1497,#1498,#1499,
#1500),.UNSPECIFIED.,.F.,.F.,(4,2,2,2,2,2,2,2,2,2,2,2,2,2,2,2,2,2,2,2,4),(0.,0.784317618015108,
1.56923751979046,2.35451371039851,3.13992609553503,3.93872016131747,4.73736924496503,
5.53582983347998,6.33415979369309,7.06618574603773,7.7981399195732,8.53008976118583,
9.25580121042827,9.98154309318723,10.7074305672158,11.3151331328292,11.922629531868,
12.529631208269,13.1446569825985,13.7602081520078,14.3778889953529),.UNSPECIFIED.);
#1502=CARTESIAN_POINT('',(20.4270281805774,14.413067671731,39.12));
#1503=VERTEX_POINT('',#1502);
#1504=EDGE_CURVE('E334',#1503,#383,#1501,.T.);
#1505=ORIENTED_EDGE('',*,*,#1504,.F.);
#1506=CARTESIAN_POINT('',(16.1559304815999,14.888117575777,26.6921745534));
#1507=CARTESIAN_POINT('',(16.2426262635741,14.8628592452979,26.7821243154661));
#1508=CARTESIAN_POINT('',(16.3278336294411,14.8390483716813,26.8738806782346));
#1509=CARTESIAN_POINT('',(16.4952623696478,14.7940972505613,27.060674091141));
#1510=CARTESIAN_POINT('',(16.5774844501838,14.7729563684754,27.1557103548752));
#1511=CARTESIAN_POINT('',(16.8190861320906,14.7133418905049,27.4445484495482));
#1512=CARTESIAN_POINT('',(16.9740812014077,14.6784819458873,27.6427903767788));
#1513=CARTESIAN_POINT('',(17.272300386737,14.6168613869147,28.0487629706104));
#1514=CARTESIAN_POINT('',(17.4155353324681,14.5900932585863,28.2564846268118));
#1515=CARTESIAN_POINT('',(17.6894144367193,14.543428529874,28.6779738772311));
#1516=CARTESIAN_POINT('',(17.8201646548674,14.5234694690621,28.89166592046));
#1517=CARTESIAN_POINT('',(18.0710288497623,14.4888842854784,29.3258636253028));
#1518=CARTESIAN_POINT('',(18.1911328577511,14.4742631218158,29.5463754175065));
#1519=CARTESIAN_POINT('',(18.4209590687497,14.4493591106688,29.9930811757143));
#1520=CARTESIAN_POINT('',(18.5306766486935,14.4390781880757,30.2192776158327));
#1521=CARTESIAN_POINT('',(18.7833189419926,14.4184443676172,30.7709959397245));
#1522=CARTESIAN_POINT('',(18.9212044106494,14.4098211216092,31.0988970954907));
#1523=CARTESIAN_POINT('',(19.1776306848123,14.3974331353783,31.7622021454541));
#1524=CARTESIAN_POINT('',(19.2961718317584,14.393668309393,32.0976059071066));
#1525=CARTESIAN_POINT('',(19.5146895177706,14.3893451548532,32.7744623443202));
#1526=CARTESIAN_POINT('',(19.6146633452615,14.3887872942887,33.1159158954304));
#1527=CARTESIAN_POINT('',(19.7970923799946,14.3895608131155,33.8052091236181));
#1528=CARTESIAN_POINT('',(19.8794609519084,14.3909012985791,34.1530716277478));
#1529=CARTESIAN_POINT('',(20.0265761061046,14.3944371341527,34.8524215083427));
#1530=CARTESIAN_POINT('',(20.0913260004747,14.3966323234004,35.2039081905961));
#1531=CARTESIAN_POINT('',(20.203609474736,14.4010812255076,35.9094862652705));
#1532=CARTESIAN_POINT('',(20.2511485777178,14.4033349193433,36.2635767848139));
#1533=CARTESIAN_POINT('',(20.3361077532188,14.4076710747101,37.0351158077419));
#1534=CARTESIAN_POINT('',(20.3703514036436,14.409656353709,37.4529209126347));
#1535=CARTESIAN_POINT('',(20.4044274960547,14.4116813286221,38.0792235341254));
#1536=CARTESIAN_POINT('',(20.412904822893,14.4121973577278,38.2872875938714));
#1537=CARTESIAN_POINT('',(20.4242039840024,14.4128918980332,38.7035637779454));
#1538=CARTESIAN_POINT('',(20.4270259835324,14.4130704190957,38.911775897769));
#1539=CARTESIAN_POINT('',(20.4270281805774,14.413067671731,39.12));
#1540=B_SPLINE_CURVE_WITH_KNOTS('',3,(#1506,#1507,#1508,#1509,#1510,#1511,#1512,#1513,#1514,
#1515,#1516,#1517,#1518,#1519,#1520,#1521,#1522,#1523,#1524,#1525,#1526,#1527,#1528,#1529,#1530,
#1531,#1532,#1533,#1534,#1535,#1536,#1537,#1538,#1539),.UNSPECIFIED.,.F.,.F.,(4,2,2,2,2,2,2,2,2,
2,2,2,2,2,2,2,4),(0.,0.382298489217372,0.764505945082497,1.52592099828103,2.28662682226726,
3.04015413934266,3.79437974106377,4.54893949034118,5.61564914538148,6.68233997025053,
7.74918645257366,8.82116780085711,9.89294749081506,10.96438293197,12.2212989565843,
12.8459461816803,13.4705751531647),.UNSPECIFIED.);
#1541=CARTESIAN_POINT('',(16.1559304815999,14.8881175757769,26.6921745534));
#1542=VERTEX_POINT('',#1541);
#1543=EDGE_CURVE('E323',#1542,#1503,#1540,.T.);
#1544=ORIENTED_EDGE('',*,*,#1543,.F.);
#1545=CARTESIAN_POINT('',(9.27998264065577,19.9136148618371,26.6921745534));
#1546=CARTESIAN_POINT('',(9.36517232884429,19.7869975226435,26.540275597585));
#1547=CARTESIAN_POINT('',(9.4545408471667,19.6590532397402,26.391610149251));
#1548=CARTESIAN_POINT('',(9.64326447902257,19.3999123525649,26.1024499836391));
#1549=CARTESIAN_POINT('',(9.74265845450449,19.2687047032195,25.9619906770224));
#1550=CARTESIAN_POINT('',(9.9545260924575,19.0007639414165,25.6894683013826));
#1551=CARTESIAN_POINT('',(10.0672245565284,18.8639727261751,25.5576339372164));
#1552=CARTESIAN_POINT('',(10.3052739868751,18.5879231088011,25.3093271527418));
#1553=CARTESIAN_POINT('',(10.4306031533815,18.4486692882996,25.1928290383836));
#1554=CARTESIAN_POINT('',(10.7123302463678,18.1502262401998,24.9657889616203));
#1555=CARTESIAN_POINT('',(10.8706514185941,17.9907692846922,24.8579237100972));
#1556=CARTESIAN_POINT('',(11.2051208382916,17.6727090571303,24.6759106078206));
#1557=CARTESIAN_POINT('',(11.3811623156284,17.5141061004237,24.6015740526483));
#1558=CARTESIAN_POINT('',(11.6583761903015,17.27886175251,24.520430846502));
#1559=CARTESIAN_POINT('',(11.7536620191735,17.200369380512,24.4983999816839));
#1560=CARTESIAN_POINT('',(11.947688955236,17.0453692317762,24.4655517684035));
#1561=CARTESIAN_POINT('',(12.046428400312,16.9688605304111,24.4547291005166));
#1562=CARTESIAN_POINT('',(12.2466174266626,16.8185247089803,24.4447055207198));
#1563=CARTESIAN_POINT('',(12.3480688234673,16.7446994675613,24.4455125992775));
#1564=CARTESIAN_POINT('',(12.5526115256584,16.6004987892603,24.4587107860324));
#1565=CARTESIAN_POINT('',(12.6557027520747,16.5301231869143,24.471101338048));
#1566=CARTESIAN_POINT('',(12.9410049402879,16.3415229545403,24.5207084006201));
#1567=CARTESIAN_POINT('',(13.1240131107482,16.2274206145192,24.5696193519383));
#1568=CARTESIAN_POINT('',(13.4875208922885,16.0131516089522,24.6971774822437));
#1569=CARTESIAN_POINT('',(13.6680186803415,15.9129946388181,24.7758452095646));
#1570=CARTESIAN_POINT('',(14.1362816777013,15.6673556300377,25.0141503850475));
#1571=CARTESIAN_POINT('',(14.419892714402,15.5331337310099,25.1935614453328));
#1572=CARTESIAN_POINT('',(14.83215201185,15.3549830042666,25.4934960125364));
#1573=CARTESIAN_POINT('',(14.9676514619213,15.2993702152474,25.5988662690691));
#1574=CARTESIAN_POINT('',(15.234449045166,15.1950634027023,25.8180348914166));
#1575=CARTESIAN_POINT('',(15.3657484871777,15.1463672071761,25.9318305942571));
#1576=CARTESIAN_POINT('',(15.608499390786,15.0607478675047,26.1518782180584));
#1577=CARTESIAN_POINT('',(15.7204155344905,15.0231132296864,26.257352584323));
#1578=CARTESIAN_POINT('',(15.9406298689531,14.9524034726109,26.4720318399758));
#1579=CARTESIAN_POINT('',(16.0489466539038,14.9193006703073,26.581208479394));
#1580=CARTESIAN_POINT('',(16.1559304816,14.8881175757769,26.6921745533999));
#1581=B_SPLINE_CURVE_WITH_KNOTS('',3,(#1545,#1546,#1547,#1548,#1549,#1550,#1551,#1552,#1553,
#1554,#1555,#1556,#1557,#1558,#1559,#1560,#1561,#1562,#1563,#1564,#1565,#1566,#1567,#1568,#1569,
#1570,#1571,#1572,#1573,#1574,#1575,#1576,#1577,#1578,#1579,#1580),.UNSPECIFIED.,.F.,.F.,(4,2,2,
2,2,2,2,2,2,2,2,2,2,2,2,2,2,4),(0.,0.646116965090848,1.29484248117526,1.95675457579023,
2.61754320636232,3.36301648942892,4.10424012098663,4.4799630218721,4.85550752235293,
5.23131006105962,5.60709455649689,6.26744605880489,6.92825439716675,8.00588325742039,
8.54699156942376,9.08792958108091,9.56276198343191,10.0345503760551),.UNSPECIFIED.);
#1582=EDGE_CURVE('E294',#1429,#1542,#1581,.T.);
#1583=ORIENTED_EDGE('',*,*,#1582,.F.);
#1584=ORIENTED_EDGE('',*,*,#1430,.F.);
#1585=EDGE_LOOP('',(#1457,#1458,#1505,#1544,#1583,#1584));
#1586=FACE_BOUND('',#1585,.T.);
#1587=ADVANCED_FACE('F306',(#1586),#1456,.F.);
#1588=CARTESIAN_POINT('',(2.,0.,39.12));
#1589=DIRECTION('',(0.,1.,0.));
#1590=DIRECTION('',(-1.,0.,0.));
#1591=AXIS2_PLACEMENT_3D('',#1588,#1589,#1590);
#1592=CIRCLE('',#1591,27.);
#1593=TRIMMED_CURVE('',#1592,(PARAMETER_VALUE(-1.49665434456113)),
(PARAMETER_VALUE(1.49665434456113)),.T.,.PARAMETER.);
#1594=CARTESIAN_POINT('',(0.,0.,39.12));
#1595=DIRECTION('',(0.,0.,-1.));
#1596=AXIS1_PLACEMENT('',#1594,#1595);
#1597=SURFACE_OF_REVOLUTION('',#1593,#1596);
#1598=CARTESIAN_POINT('',(24.6838914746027,0.,43.2394581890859));
#1599=CARTESIAN_POINT('',(24.7048921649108,0.0140823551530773,43.1034264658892));
#1600=CARTESIAN_POINT('',(24.7248528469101,0.0273771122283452,42.9671532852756));
#1601=CARTESIAN_POINT('',(24.7626616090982,0.0524187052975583,42.6943637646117));
#1602=CARTESIAN_POINT('',(24.780512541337,0.0641676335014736,42.5578480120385));
#1603=CARTESIAN_POINT('',(24.8141097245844,0.0861720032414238,42.2845787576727));
#1604=CARTESIAN_POINT('',(24.8298580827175,0.0964289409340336,42.1478256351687));
#1605=CARTESIAN_POINT('',(24.8592560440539,0.115494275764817,41.8740855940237));
#1606=CARTESIAN_POINT('',(24.872907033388,0.124303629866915,41.7370988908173));
#1607=CARTESIAN_POINT('',(24.8981139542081,0.14051162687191,41.4628949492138));
#1608=CARTESIAN_POINT('',(24.9096705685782,0.147910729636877,41.3256778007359));
#1609=CARTESIAN_POINT('',(24.9306899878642,0.161328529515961,41.0510203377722));
#1610=CARTESIAN_POINT('',(24.9401528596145,0.167347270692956,40.913580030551));
#1611=CARTESIAN_POINT('',(24.9569850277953,0.178028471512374,40.6384708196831));
#1612=CARTESIAN_POINT('',(24.9643535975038,0.182690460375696,40.5008018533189));
#1613=CARTESIAN_POINT('',(24.9769946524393,0.190674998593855,40.2252355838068));
#1614=CARTESIAN_POINT('',(24.9822657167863,0.193996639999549,40.0873381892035));
#1615=CARTESIAN_POINT('',(24.9907071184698,0.199311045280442,39.8113150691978));
#1616=CARTESIAN_POINT('',(24.9938753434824,0.201302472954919,39.6731892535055));
#1617=CARTESIAN_POINT('',(24.9981045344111,0.203959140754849,39.3967089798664));
#1618=CARTESIAN_POINT('',(24.9991626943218,0.204622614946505,39.2583544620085));
#1619=CARTESIAN_POINT('',(24.9991625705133,0.204623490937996,39.12));
#1620=B_SPLINE_CURVE_WITH_KNOTS('',3,(#1598,#1599,#1600,#1601,#1602,#1603,#1604,#1605,#1606,
#1607,#1608,#1609,#1610,#1611,#1612,#1613,#1614,#1615,#1616,#1617,#1618,#1619),.UNSPECIFIED.,
.F.,.F.,(4,2,2,2,2,2,2,2,2,2,4),(0.,0.415077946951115,0.829588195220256,1.24367986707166,
1.65749668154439,2.07117832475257,2.48484676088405,2.89865856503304,3.31275021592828,
3.7272571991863,4.14231503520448),.UNSPECIFIED.);
#1621=CARTESIAN_POINT('',(24.9991625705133,0.204623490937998,39.12));
#1622=VERTEX_POINT('',#1621);
#1623=EDGE_CURVE('E544',#498,#1622,#1620,.T.);
#1624=ORIENTED_EDGE('',*,*,#1623,.T.);
#1625=CARTESIAN_POINT('',(24.9991625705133,0.204623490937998,39.12));
#1626=CARTESIAN_POINT('',(24.9991626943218,0.204622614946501,38.9816455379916));
#1627=CARTESIAN_POINT('',(24.9981045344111,0.203959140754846,38.8432910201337));
#1628=CARTESIAN_POINT('',(24.9938753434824,0.201302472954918,38.5668107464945));
#1629=CARTESIAN_POINT('',(24.9907071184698,0.199311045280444,38.4286849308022));
#1630=CARTESIAN_POINT('',(24.9822657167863,0.193996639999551,38.1526618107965));
#1631=CARTESIAN_POINT('',(24.9769946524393,0.190674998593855,38.0147644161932));
#1632=CARTESIAN_POINT('',(24.9643535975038,0.182690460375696,37.7391981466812));
#1633=CARTESIAN_POINT('',(24.9569850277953,0.178028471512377,37.601529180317));
#1634=CARTESIAN_POINT('',(24.9401528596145,0.167347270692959,37.3264199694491));
#1635=CARTESIAN_POINT('',(24.9306899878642,0.161328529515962,37.1889796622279));
#1636=CARTESIAN_POINT('',(24.9096705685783,0.147910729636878,36.9143221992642));
#1637=CARTESIAN_POINT('',(24.8981139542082,0.140511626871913,36.7771050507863));
#1638=CARTESIAN_POINT('',(24.872907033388,0.124303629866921,36.5029011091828));
#1639=CARTESIAN_POINT('',(24.8592560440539,0.115494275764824,36.3659144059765));
#1640=CARTESIAN_POINT('',(24.8298580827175,0.0964289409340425,36.0921743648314));
#1641=CARTESIAN_POINT('',(24.8141097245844,0.0861720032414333,35.9554212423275));
#1642=CARTESIAN_POINT('',(24.780512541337,0.0641676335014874,35.6821519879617));
#1643=CARTESIAN_POINT('',(24.7626616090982,0.0524187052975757,35.5456362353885));
#1644=CARTESIAN_POINT('',(24.7248528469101,0.027377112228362,35.2728467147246));
#1645=CARTESIAN_POINT('',(24.7048921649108,0.0140823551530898,35.136573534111));
#1646=CARTESIAN_POINT('',(24.6838914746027,0.,35.0005418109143));
#1647=B_SPLINE_CURVE_WITH_KNOTS('',3,(#1625,#1626,#1627,#1628,#1629,#1630,#1631,#1632,#1633,
#1634,#1635,#1636,#1637,#1638,#1639,#1640,#1641,#1642,#1643,#1644,#1645,#1646),.UNSPECIFIED.,
.F.,.F.,(4,2,2,2,2,2,2,2,2,2,4),(0.,0.415057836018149,0.829564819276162,1.24365647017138,
1.65746827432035,2.07113671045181,2.48481835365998,2.89863516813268,3.31272683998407,
3.7272370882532,4.14231503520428),.UNSPECIFIED.);
#1648=CARTESIAN_POINT('',(24.6838914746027,0.,35.0005418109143));
#1649=VERTEX_POINT('',#1648);
#1650=EDGE_CURVE('E537',#1622,#1649,#1647,.T.);
#1651=ORIENTED_EDGE('',*,*,#1650,.T.);
#1652=CARTESIAN_POINT('',(-2.,0.,39.12));
#1653=DIRECTION('',(0.,-1.,0.));
#1654=DIRECTION('',(1.,0.,0.));
#1655=AXIS2_PLACEMENT_3D('',#1652,#1653,#1654);
#1656=CIRCLE('',#1655,27.);
#1657=CARTESIAN_POINT('',(21.9697549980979,0.,26.6921745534));
#1658=VERTEX_POINT('',#1657);
#1659=EDGE_CURVE('E767',#1658,#1649,#1656,.T.);
#1660=ORIENTED_EDGE('',*,*,#1659,.F.);
#1661=CARTESIAN_POINT('',(0.,0.,26.6921745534));
#1662=DIRECTION('',(0.,0.,1.));
#1663=DIRECTION('',(0.,1.,0.));
#1664=AXIS2_PLACEMENT_3D('',#1661,#1662,#1663);
#1665=CIRCLE('',#1664,21.9697549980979);
#1666=EDGE_CURVE('E302',#1542,#1658,#1665,.F.);
#1667=ORIENTED_EDGE('',*,*,#1666,.F.);
#1668=ORIENTED_EDGE('',*,*,#1543,.T.);
#1669=ORIENTED_EDGE('',*,*,#1504,.T.);
#1670=ORIENTED_EDGE('',*,*,#384,.T.);
#1671=ORIENTED_EDGE('',*,*,#506,.T.);
#1672=EDGE_LOOP('',(#1624,#1651,#1660,#1667,#1668,#1669,#1670,#1671));
#1673=FACE_BOUND('',#1672,.T.);
#1674=ADVANCED_FACE('F311',(#1673),#1597,.F.);
#1675=CARTESIAN_POINT('',(2.,0.,39.12));
#1676=DIRECTION('',(0.,1.,0.));
#1677=DIRECTION('',(-1.,0.,0.));
#1678=AXIS2_PLACEMENT_3D('',#1675,#1676,#1677);
#1679=CIRCLE('',#1678,27.);
#1680=TRIMMED_CURVE('',#1679,(PARAMETER_VALUE(-1.49665434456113)),
(PARAMETER_VALUE(1.49665434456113)),.T.,.PARAMETER.);
#1681=CARTESIAN_POINT('',(0.,0.,39.12));
#1682=DIRECTION('',(0.,0.,-1.));
#1683=AXIS1_PLACEMENT('',#1681,#1682);
#1684=SURFACE_OF_REVOLUTION('',#1680,#1683);
#1685=CARTESIAN_POINT('',(24.6838914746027,0.,35.0005418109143));
#1686=CARTESIAN_POINT('',(24.6431112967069,-0.0273663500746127,34.7363741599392));
#1687=CARTESIAN_POINT('',(24.5984036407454,-0.0576792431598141,34.4731035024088));
#1688=CARTESIAN_POINT('',(24.5010611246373,-0.124795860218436,33.9479947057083));
#1689=CARTESIAN_POINT('',(24.4484017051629,-0.161619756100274,33.6861637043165));
#1690=CARTESIAN_POINT('',(24.3352425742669,-0.24226035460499,33.1647887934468));
#1691=CARTESIAN_POINT('',(24.274729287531,-0.286089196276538,32.9052496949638));
#1692=CARTESIAN_POINT('',(24.1460080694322,-0.381344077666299,32.3893252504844));
#1693=CARTESIAN_POINT('',(24.0777957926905,-0.432774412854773,32.1329417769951));
#1694=CARTESIAN_POINT('',(23.9362161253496,-0.542111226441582,31.6324918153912));
#1695=CARTESIAN_POINT('',(23.8630925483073,-0.599748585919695,31.3882977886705));
#1696=CARTESIAN_POINT('',(23.7100268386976,-0.723515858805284,30.9044413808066));
#1697=CARTESIAN_POINT('',(23.6300899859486,-0.789639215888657,30.6647756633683));
#1698=CARTESIAN_POINT('',(23.4636337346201,-0.931235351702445,30.1907905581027));
#1699=CARTESIAN_POINT('',(23.3771201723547,-1.0066998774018,29.9564666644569));
#1700=CARTESIAN_POINT('',(23.197753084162,-1.16800902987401,29.4939914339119));
#1701=CARTESIAN_POINT('',(23.1049025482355,-1.25384877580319,29.2658372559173));
#1702=CARTESIAN_POINT('',(22.9640320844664,-1.38849765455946,28.9358646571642));
#1703=CARTESIAN_POINT('',(22.9183426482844,-1.43281156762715,28.8311961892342));
#1704=CARTESIAN_POINT('',(22.8256883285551,-1.52412139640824,28.6236126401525));
#1705=CARTESIAN_POINT('',(22.7787235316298,-1.57111713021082,28.5206974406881));
#1706=CARTESIAN_POINT('',(22.6835815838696,-1.66791789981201,28.3168000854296));
#1707=CARTESIAN_POINT('',(22.6354047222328,-1.71772226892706,28.2158174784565));
#1708=CARTESIAN_POINT('',(22.5379030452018,-1.8202814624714,28.015965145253));
#1709=CARTESIAN_POINT('',(22.4885785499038,-1.87303546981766,27.917094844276));
#1710=CARTESIAN_POINT('',(22.3880709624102,-1.98249520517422,27.7201292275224));
#1711=CARTESIAN_POINT('',(22.3368709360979,-2.03924934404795,27.6220694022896));
#1712=CARTESIAN_POINT('',(22.233427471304,-2.15614071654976,27.4285223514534));
#1713=CARTESIAN_POINT('',(22.1811838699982,-2.21627848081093,27.3330355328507));
#1714=CARTESIAN_POINT('',(22.0757270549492,-2.34013756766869,27.1448482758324));
#1715=CARTESIAN_POINT('',(22.0225132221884,-2.40386123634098,27.0521497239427));
#1716=CARTESIAN_POINT('',(21.9151971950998,-2.53511791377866,26.8697779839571));
#1717=CARTESIAN_POINT('',(21.861093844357,-2.60265621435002,26.7801092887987));
#1718=CARTESIAN_POINT('',(21.8066455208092,-2.67214254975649,26.6921745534));
#1719=B_SPLINE_CURVE_WITH_KNOTS('',3,(#1685,#1686,#1687,#1688,#1689,#1690,#1691,#1692,#1693,
#1694,#1695,#1696,#1697,#1698,#1699,#1700,#1701,#1702,#1703,#1704,#1705,#1706,#1707,#1708,#1709,
#1710,#1711,#1712,#1713,#1714,#1715,#1716,#1717,#1718),.UNSPECIFIED.,.F.,.F.,(4,2,2,2,2,2,2,2,2,
2,2,2,2,2,2,2,4),(0.,0.806057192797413,1.61465686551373,2.42467328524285,3.23514919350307,
4.01892879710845,4.80210645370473,5.58459703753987,6.36672093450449,6.73418787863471,
7.10162992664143,7.46898511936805,7.83623904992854,8.20915903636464,8.58213766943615,
8.95536322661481,9.32911989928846),.UNSPECIFIED.);
#1720=CARTESIAN_POINT('',(21.8066455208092,-2.67214254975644,26.6921745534));
#1721=VERTEX_POINT('',#1720);
#1722=EDGE_CURVE('E562',#1649,#1721,#1719,.T.);
#1723=ORIENTED_EDGE('',*,*,#1722,.T.);
#1724=CARTESIAN_POINT('',(0.,0.,26.6921745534));
#1725=DIRECTION('',(0.,0.,1.));
#1726=DIRECTION('',(0.,1.,0.));
#1727=AXIS2_PLACEMENT_3D('',#1724,#1725,#1726);
#1728=CIRCLE('',#1727,21.9697549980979);
#1729=EDGE_CURVE('E772',#1658,#1721,#1728,.F.);
#1730=ORIENTED_EDGE('',*,*,#1729,.F.);
#1731=ORIENTED_EDGE('',*,*,#1659,.T.);
#1732=EDGE_LOOP('',(#1723,#1730,#1731));
#1733=FACE_BOUND('',#1732,.T.);
#1734=ADVANCED_FACE('F775',(#1733),#1684,.F.);
#1735=CARTESIAN_POINT('',(31.6460332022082,-10.3816464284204,0.));
#1736=DIRECTION('',(0.,0.,-1.));
#1737=DIRECTION('',(-1.,0.,0.));
#1738=AXIS2_PLACEMENT_3D('',#1735,#1736,#1737);
#1739=CYLINDRICAL_SURFACE('',#1738,12.5);
#1740=ORIENTED_EDGE('',*,*,#1623,.F.);
#1741=ORIENTED_EDGE('',*,*,#499,.F.);
#1742=ORIENTED_EDGE('',*,*,#668,.F.);
#1743=CARTESIAN_POINT('',(20.0199407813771,-14.9733754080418,39.12));
#1744=CARTESIAN_POINT('',(20.0199487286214,-14.9733672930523,39.3814510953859));
#1745=CARTESIAN_POINT('',(20.0183022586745,-14.9692256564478,39.6429036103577));
#1746=CARTESIAN_POINT('',(20.0117548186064,-14.9526108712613,40.1657037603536));
#1747=CARTESIAN_POINT('',(20.0068513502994,-14.940131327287,40.4270511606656));
#1748=CARTESIAN_POINT('',(19.9938414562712,-14.9067685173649,40.9492493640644));
#1749=CARTESIAN_POINT('',(19.985733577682,-14.8858814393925,41.2100998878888));
#1750=CARTESIAN_POINT('',(19.9664277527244,-14.8355826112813,41.7309098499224));
#1751=CARTESIAN_POINT('',(19.9552292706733,-14.8061693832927,41.9908691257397));
#1752=CARTESIAN_POINT('',(19.9296857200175,-14.7380837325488,42.5139352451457));
#1753=CARTESIAN_POINT('',(19.915290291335,-14.699262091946,42.7770202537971));
#1754=CARTESIAN_POINT('',(19.8836919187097,-14.6124221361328,43.3014519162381));
#1755=CARTESIAN_POINT('',(19.8664894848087,-14.5644054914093,43.5627988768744));
#1756=CARTESIAN_POINT('',(19.8295585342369,-14.4589065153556,44.0833343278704));
#1757=CARTESIAN_POINT('',(19.8098306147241,-14.4014264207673,44.3425233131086));
#1758=CARTESIAN_POINT('',(19.7681908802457,-14.2766673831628,44.8583166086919));
#1759=CARTESIAN_POINT('',(19.746279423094,-14.2093900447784,45.1149213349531));
#1760=CARTESIAN_POINT('',(19.7025779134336,-14.0706455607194,45.6038935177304));
#1761=CARTESIAN_POINT('',(19.6809289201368,-13.9999904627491,45.8365039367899));
#1762=CARTESIAN_POINT('',(19.6365218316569,-13.8497545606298,46.2986990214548));
#1763=CARTESIAN_POINT('',(19.6137638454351,-13.7701746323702,46.528283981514));
#1764=CARTESIAN_POINT('',(19.567580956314,-13.6016811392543,46.9839413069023));
#1765=CARTESIAN_POINT('',(19.5441560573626,-13.5127676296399,47.2100136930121));
#1766=CARTESIAN_POINT('',(19.4973598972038,-13.3259514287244,47.656145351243));
#1767=CARTESIAN_POINT('',(19.4739898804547,-13.2281318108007,47.8762394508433));
#1768=CARTESIAN_POINT('',(19.4276990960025,-13.0223724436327,48.31171737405));
#1769=CARTESIAN_POINT('',(19.4047783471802,-12.9144322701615,48.5271009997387));
#1770=CARTESIAN_POINT('',(19.3600782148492,-12.6878664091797,48.9523754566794));
#1771=CARTESIAN_POINT('',(19.3382990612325,-12.5692385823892,49.1622651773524));
#1772=CARTESIAN_POINT('',(19.3000959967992,-12.3409703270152,49.5418451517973));
#1773=CARTESIAN_POINT('',(19.2833775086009,-12.2330112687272,49.7125165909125));
#1774=CARTESIAN_POINT('',(19.2518854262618,-12.0088850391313,50.0485027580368));
#1775=CARTESIAN_POINT('',(19.2371111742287,-11.8927206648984,50.2138192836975));
#1776=CARTESIAN_POINT('',(19.2101514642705,-11.6518894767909,50.5381701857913));
#1777=CARTESIAN_POINT('',(19.1979639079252,-11.527229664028,50.697209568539));
#1778=CARTESIAN_POINT('',(19.176755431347,-11.2672741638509,51.0101766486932));
#1779=CARTESIAN_POINT('',(19.1677785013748,-11.1318596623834,51.1640089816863));
#1780=CARTESIAN_POINT('',(19.1540734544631,-10.8514292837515,51.4631714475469));
#1781=CARTESIAN_POINT('',(19.1493489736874,-10.7064053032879,51.6084942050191));
#1782=CARTESIAN_POINT('',(19.1451576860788,-10.4061814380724,51.8893521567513));
#1783=CARTESIAN_POINT('',(19.1457091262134,-10.2509480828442,52.0248517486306));
#1784=CARTESIAN_POINT('',(19.1494179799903,-10.0907719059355,52.154357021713));
#1785=B_SPLINE_CURVE_WITH_KNOTS('',3,(#1743,#1744,#1745,#1746,#1747,#1748,#1749,#1750,#1751,
#1752,#1753,#1754,#1755,#1756,#1757,#1758,#1759,#1760,#1761,#1762,#1763,#1764,#1765,#1766,#1767,
#1768,#1769,#1770,#1771,#1772,#1773,#1774,#1775,#1776,#1777,#1778,#1779,#1780,#1781,#1782,#1783,
#1784),.UNSPECIFIED.,.F.,.F.,(4,2,2,2,2,2,2,2,2,2,2,2,2,2,2,2,2,2,2,2,4),(0.,0.784317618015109,
1.56923751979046,2.35451371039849,3.13992609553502,3.93872016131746,4.73736924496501,
5.53582983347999,6.33415979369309,7.06618574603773,7.7981399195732,8.53008976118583,
9.25580121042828,9.98154309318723,10.7074305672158,11.3151331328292,11.922629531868,
12.529631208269,13.1446569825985,13.7602081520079,14.377888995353),.UNSPECIFIED.);
#1786=CARTESIAN_POINT('',(20.0199407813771,-14.9733754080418,39.12));
#1787=VERTEX_POINT('',#1786);
#1788=EDGE_CURVE('E519',#1787,#626,#1785,.T.);
#1789=ORIENTED_EDGE('',*,*,#1788,.F.);
#1790=CARTESIAN_POINT('',(19.1518983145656,-10.7645216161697,26.6921745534));
#1791=CARTESIAN_POINT('',(19.1546666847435,-10.8547794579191,26.7821243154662));
#1792=CARTESIAN_POINT('',(19.1583517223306,-10.9431744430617,26.8738806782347));
#1793=CARTESIAN_POINT('',(19.1673389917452,-11.1162992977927,27.0606740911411));
#1794=CARTESIAN_POINT('',(19.1726408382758,-11.2010300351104,27.1557103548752));
#1795=CARTESIAN_POINT('',(19.1906031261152,-11.4492287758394,27.4445484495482));
#1796=CARTESIAN_POINT('',(19.2053454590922,-11.6074101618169,27.6427903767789));
#1797=CARTESIAN_POINT('',(19.2388956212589,-11.9100752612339,28.0487629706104));
#1798=CARTESIAN_POINT('',(19.2576996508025,-12.0545715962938,28.2564846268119));
#1799=CARTESIAN_POINT('',(19.2979521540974,-12.329466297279,28.6779738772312));
#1800=CARTESIAN_POINT('',(19.319373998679,-12.4599848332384,28.89166592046));
#1801=CARTESIAN_POINT('',(19.3640028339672,-12.7092582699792,29.3258636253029));
#1802=CARTESIAN_POINT('',(19.3872114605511,-12.8280021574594,29.5463754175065));
#1803=CARTESIAN_POINT('',(19.4345465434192,-13.0542756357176,29.9930811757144));
#1804=CARTESIAN_POINT('',(19.4586734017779,-13.1618002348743,30.2192776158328));
#1805=CARTESIAN_POINT('',(19.5171202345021,-13.4084535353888,30.7709959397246));
#1806=CARTESIAN_POINT('',(19.5515279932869,-13.5422551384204,31.0988970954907));
#1807=CARTESIAN_POINT('',(19.6189863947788,-13.7899591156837,31.7622021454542));
#1808=CARTESIAN_POINT('',(19.6520370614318,-13.9038618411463,32.0976059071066));
#1809=CARTESIAN_POINT('',(19.715451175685,-14.113020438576,32.7744623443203));
#1810=CARTESIAN_POINT('',(19.7458142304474,-14.2082735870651,33.1159158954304));
#1811=CARTESIAN_POINT('',(19.802923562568,-14.3815348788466,33.8052091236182));
#1812=CARTESIAN_POINT('',(19.8296517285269,-14.4594578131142,34.1530716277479));
#1813=CARTESIAN_POINT('',(19.8784755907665,-14.5982800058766,34.8524215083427));
#1814=CARTESIAN_POINT('',(19.9005721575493,-14.6591824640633,35.2039081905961));
#1815=CARTESIAN_POINT('',(19.939500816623,-14.7645956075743,35.9094862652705));
#1816=CARTESIAN_POINT('',(19.9563345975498,-14.8091115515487,36.263576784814));
#1817=CARTESIAN_POINT('',(19.986712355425,-14.8885725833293,37.0351158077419));
#1818=CARTESIAN_POINT('',(19.9991823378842,-14.9205267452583,37.4529209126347));
#1819=CARTESIAN_POINT('',(20.0116382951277,-14.9523092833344,38.0792235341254));
#1820=CARTESIAN_POINT('',(20.0147487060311,-14.9602122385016,38.2872875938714));
#1821=CARTESIAN_POINT('',(20.0189008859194,-14.9707437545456,38.7035637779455));
#1822=CARTESIAN_POINT('',(20.019942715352,-14.9733724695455,38.911775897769));
#1823=CARTESIAN_POINT('',(20.0199407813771,-14.9733754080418,39.12));
#1824=B_SPLINE_CURVE_WITH_KNOTS('',3,(#1790,#1791,#1792,#1793,#1794,#1795,#1796,#1797,#1798,
#1799,#1800,#1801,#1802,#1803,#1804,#1805,#1806,#1807,#1808,#1809,#1810,#1811,#1812,#1813,#1814,
#1815,#1816,#1817,#1818,#1819,#1820,#1821,#1822,#1823),.UNSPECIFIED.,.F.,.F.,(4,2,2,2,2,2,2,2,2,
2,2,2,2,2,2,2,4),(0.,0.382298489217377,0.7645059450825,1.52592099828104,2.28662682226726,
3.04015413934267,3.79437974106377,4.54893949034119,5.61564914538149,6.68233997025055,
7.74918645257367,8.82116780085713,9.89294749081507,10.96438293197,12.2212989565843,
12.8459461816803,13.4705751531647),.UNSPECIFIED.);
#1825=CARTESIAN_POINT('',(19.1518983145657,-10.7645216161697,26.6921745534));
#1826=VERTEX_POINT('',#1825);
#1827=EDGE_CURVE('E525',#1826,#1787,#1824,.T.);
#1828=ORIENTED_EDGE('',*,*,#1827,.F.);
#1829=CARTESIAN_POINT('',(21.8066455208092,-2.67214254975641,26.6921745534));
#1830=CARTESIAN_POINT('',(21.7125503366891,-2.79228966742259,26.540275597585));
#1831=CARTESIAN_POINT('',(21.6184844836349,-2.91682113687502,26.391610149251));
#1832=CARTESIAN_POINT('',(21.4303456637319,-3.17638691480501,26.1024499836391));
#1833=CARTESIAN_POINT('',(21.3362742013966,-3.31146159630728,25.9619906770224));
#1834=CARTESIAN_POINT('',(21.1469180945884,-3.59575794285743,25.6894683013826));
#1835=CARTESIAN_POINT('',(21.051647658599,-3.74521136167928,25.5576339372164));
#1836=CARTESIAN_POINT('',(20.8626701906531,-4.05691384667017,25.3093271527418));
#1837=CARTESIAN_POINT('',(20.7689607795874,-4.21914076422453,25.1928290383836));
#1838=CARTESIAN_POINT('',(20.5721830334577,-4.57930312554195,24.9657889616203));
#1839=CARTESIAN_POINT('',(20.4694543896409,-4.77915041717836,24.8579237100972));
#1840=CARTESIAN_POINT('',(20.2703178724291,-5.19553575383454,24.6759106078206));
#1841=CARTESIAN_POINT('',(20.1738773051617,-5.41197215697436,24.6015740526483));
#1842=CARTESIAN_POINT('',(20.0358104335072,-5.74831272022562,24.5204308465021));
#1843=CARTESIAN_POINT('',(19.9906046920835,-5.86319040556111,24.4983999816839));
#1844=CARTESIAN_POINT('',(19.9031484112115,-6.09561866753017,24.4655517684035));
#1845=CARTESIAN_POINT('',(19.8608964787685,-6.21316794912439,24.4547291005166));
#1846=CARTESIAN_POINT('',(19.7797804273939,-6.45001535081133,24.4447055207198));
#1847=CARTESIAN_POINT('',(19.7409186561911,-6.56931461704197,24.4455125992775));
#1848=CARTESIAN_POINT('',(19.6669828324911,-6.80840674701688,24.4587107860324));
#1849=CARTESIAN_POINT('',(19.6319085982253,-6.92819958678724,24.471101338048));
#1850=CARTESIAN_POINT('',(19.5407023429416,-7.25781876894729,24.5207084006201));
#1851=CARTESIAN_POINT('',(19.4887372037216,-7.46712944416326,24.5696193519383));
#1852=CARTESIAN_POINT('',(19.3972853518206,-7.87905865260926,24.6971774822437));
#1853=CARTESIAN_POINT('',(19.3578072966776,-8.0816724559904,24.7758452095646));
#1854=CARTESIAN_POINT('',(19.2688919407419,-8.60292365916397,25.0141503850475));
#1855=CARTESIAN_POINT('',(19.2288799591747,-8.91413063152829,25.1935614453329));
#1856=CARTESIAN_POINT('',(19.1868436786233,-9.36126412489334,25.4934960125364));
#1857=CARTESIAN_POINT('',(19.1758244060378,-9.50731705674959,25.5988662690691));
#1858=CARTESIAN_POINT('',(19.1590677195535,-9.79328921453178,25.8180348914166));
#1859=CARTESIAN_POINT('',(19.1533286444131,-9.93321035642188,25.9318305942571));
#1860=CARTESIAN_POINT('',(19.1469139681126,-10.1905380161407,26.1518782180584));
#1861=CARTESIAN_POINT('',(19.1457052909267,-10.3086063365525,26.257352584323));
#1862=CARTESIAN_POINT('',(19.1465062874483,-10.5398931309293,26.4720318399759));
#1863=CARTESIAN_POINT('',(19.1484953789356,-10.653137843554,26.581208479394));
#1864=CARTESIAN_POINT('',(19.1518983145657,-10.7645216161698,26.6921745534));
#1865=B_SPLINE_CURVE_WITH_KNOTS('',3,(#1829,#1830,#1831,#1832,#1833,#1834,#1835,#1836,#1837,
#1838,#1839,#1840,#1841,#1842,#1843,#1844,#1845,#1846,#1847,#1848,#1849,#1850,#1851,#1852,#1853,
#1854,#1855,#1856,#1857,#1858,#1859,#1860,#1861,#1862,#1863,#1864),.UNSPECIFIED.,.F.,.F.,(4,2,2,
2,2,2,2,2,2,2,2,2,2,2,2,2,2,4),(0.,0.646116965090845,1.29484248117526,1.95675457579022,
2.6175432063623,3.36301648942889,4.10424012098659,4.47996302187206,4.85550752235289,
5.23131006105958,5.60709455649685,6.26744605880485,6.92825439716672,8.00588325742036,
8.54699156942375,9.0879295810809,9.5627619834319,10.0345503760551),.UNSPECIFIED.);
#1866=EDGE_CURVE('E271',#1721,#1826,#1865,.T.);
#1867=ORIENTED_EDGE('',*,*,#1866,.F.);
#1868=ORIENTED_EDGE('',*,*,#1722,.F.);
#1869=ORIENTED_EDGE('',*,*,#1650,.F.);
#1870=EDGE_LOOP('',(#1740,#1741,#1742,#1789,#1828,#1867,#1868,#1869));
#1871=FACE_BOUND('',#1870,.T.);
#1872=ADVANCED_FACE('F497',(#1871),#1739,.F.);
#1873=CARTESIAN_POINT('',(2.,0.,39.12));
#1874=DIRECTION('',(0.,1.,0.));
#1875=DIRECTION('',(-1.,0.,0.));
#1876=AXIS2_PLACEMENT_3D('',#1873,#1874,#1875);
#1877=CIRCLE('',#1876,27.);
#1878=TRIMMED_CURVE('',#1877,(PARAMETER_VALUE(-1.49665434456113)),
(PARAMETER_VALUE(1.49665434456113)),.T.,.PARAMETER.);
#1879=CARTESIAN_POINT('',(0.,0.,39.12));
#1880=DIRECTION('',(0.,0.,-1.));
#1881=AXIS1_PLACEMENT('',#1879,#1880);
#1882=SURFACE_OF_REVOLUTION('',#1878,#1881);
#1883=ORIENTED_EDGE('',*,*,#1788,.T.);
#1884=ORIENTED_EDGE('',*,*,#627,.T.);
#1885=CARTESIAN_POINT('',(3.55846138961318,-21.3509072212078,52.154357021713));
#1886=CARTESIAN_POINT('',(3.72785232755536,-21.4026978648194,52.011169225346));
#1887=CARTESIAN_POINT('',(3.89028373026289,-21.4562372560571,51.8606855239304));
#1888=CARTESIAN_POINT('',(4.20120816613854,-21.5653726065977,51.5479752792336));
#1889=CARTESIAN_POINT('',(4.34975875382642,-21.6209586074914,51.385802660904));
#1890=CARTESIAN_POINT('',(4.63421151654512,-21.7331574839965,51.051459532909));
#1891=CARTESIAN_POINT('',(4.77012709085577,-21.789769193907,50.8792999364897));
#1892=CARTESIAN_POINT('',(5.02847981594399,-21.9023770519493,50.5288764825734));
#1893=CARTESIAN_POINT('',(5.15107660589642,-21.9583709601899,50.3507291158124));
#1894=CARTESIAN_POINT('',(5.3857655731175,-22.0698362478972,49.9872342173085));
#1895=CARTESIAN_POINT('',(5.49784670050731,-22.1253070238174,49.8018793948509));
#1896=CARTESIAN_POINT('',(5.71212431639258,-22.2350811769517,49.4251071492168));
#1897=CARTESIAN_POINT('',(5.81431597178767,-22.289383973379,49.2336868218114));
#1898=CARTESIAN_POINT('',(6.04904089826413,-22.4179852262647,48.7669664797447));
#1899=CARTESIAN_POINT('',(6.17705249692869,-22.4914529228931,48.4891581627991));
#1900=CARTESIAN_POINT('',(6.41640501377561,-22.6338526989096,47.9253991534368));
#1901=CARTESIAN_POINT('',(6.52774679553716,-22.7027850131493,47.6394488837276));
#1902=CARTESIAN_POINT('',(6.73522800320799,-22.8352316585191,47.0608511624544));
#1903=CARTESIAN_POINT('',(6.83136614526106,-22.898745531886,46.7682031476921));
#1904=CARTESIAN_POINT('',(7.01047959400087,-23.0201890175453,46.1747261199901));
#1905=CARTESIAN_POINT('',(7.09332534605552,-23.0780617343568,45.8738465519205));
#1906=CARTESIAN_POINT('',(7.24582664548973,-23.1869572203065,45.2676000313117));
#1907=CARTESIAN_POINT('',(7.3154839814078,-23.2379809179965,44.9622336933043));
#1908=CARTESIAN_POINT('',(7.44250055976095,-23.3327163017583,44.3478630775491));
#1909=CARTESIAN_POINT('',(7.49986077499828,-23.3764285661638,44.0388590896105));
#1910=CARTESIAN_POINT('',(7.59365109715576,-23.4489453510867,43.4742558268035));
#1911=CARTESIAN_POINT('',(7.63199042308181,-23.479015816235,43.2191324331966));
#1912=CARTESIAN_POINT('',(7.70122344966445,-23.5338502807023,42.7073361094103));
#1913=CARTESIAN_POINT('',(7.73211791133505,-23.5586148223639,42.4506633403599));
#1914=CARTESIAN_POINT('',(7.78672052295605,-23.6027129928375,41.936096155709));
#1915=CARTESIAN_POINT('',(7.81042877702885,-23.6220467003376,41.6782017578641));
#1916=CARTESIAN_POINT('',(7.85056619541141,-23.6549530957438,41.1651789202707));
#1917=CARTESIAN_POINT('',(7.86709387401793,-23.6686036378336,40.910063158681));
#1918=CARTESIAN_POINT('',(7.89348793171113,-23.6904686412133,40.3992576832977));
#1919=CARTESIAN_POINT('',(7.90335436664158,-23.6986831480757,40.1435679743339));
#1920=CARTESIAN_POINT('',(7.91649279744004,-23.7096431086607,39.6319183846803));
#1921=CARTESIAN_POINT('',(7.91976521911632,-23.7123889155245,39.3759585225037));
#1922=CARTESIAN_POINT('',(7.9197745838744,-23.7123843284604,39.12));
#1923=B_SPLINE_CURVE_WITH_KNOTS('',3,(#1885,#1886,#1887,#1888,#1889,#1890,#1891,#1892,#1893,
#1894,#1895,#1896,#1897,#1898,#1899,#1900,#1901,#1902,#1903,#1904,#1905,#1906,#1907,#1908,#1909,
#1910,#1911,#1912,#1913,#1914,#1915,#1916,#1917,#1918,#1919,#1920,#1921,#1922),.UNSPECIFIED.,
.F.,.F.,(4,2,2,2,2,2,2,2,2,2,2,2,2,2,2,2,2,2,4),(0.,0.682797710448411,1.36262545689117,
2.04172382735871,2.71148408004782,3.38194041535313,4.05272277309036,4.99578547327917,
5.93879930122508,6.88189271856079,7.83368276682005,8.78534364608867,9.73692921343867,
10.515971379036,11.2949338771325,12.0738850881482,12.8417832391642,13.6096749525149,
14.377517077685),.UNSPECIFIED.);
#1924=CARTESIAN_POINT('',(7.91977458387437,-23.7123843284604,39.12));
#1925=VERTEX_POINT('',#1924);
#1926=EDGE_CURVE('E512',#617,#1925,#1923,.T.);
#1927=ORIENTED_EDGE('',*,*,#1926,.T.);
#1928=CARTESIAN_POINT('',(7.91977458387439,-23.7123843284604,39.12));
#1929=CARTESIAN_POINT('',(7.91976437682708,-23.7123893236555,38.8585181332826));
#1930=CARTESIAN_POINT('',(7.91634961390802,-23.7095235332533,38.5970348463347));
#1931=CARTESIAN_POINT('',(7.90263261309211,-23.6980816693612,38.0741715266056));
#1932=CARTESIAN_POINT('',(7.89232504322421,-23.6895011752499,37.8127917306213));
#1933=CARTESIAN_POINT('',(7.86473753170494,-23.6666560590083,37.2905278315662));
#1934=CARTESIAN_POINT('',(7.84745439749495,-23.6523888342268,37.0296440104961));
#1935=CARTESIAN_POINT('',(7.80576532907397,-23.6182393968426,36.5087672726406));
#1936=CARTESIAN_POINT('',(7.78135814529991,-23.5983561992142,36.2487745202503));
#1937=CARTESIAN_POINT('',(7.72474829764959,-23.5526958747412,35.725706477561));
#1938=CARTESIAN_POINT('',(7.69242165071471,-23.526825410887,35.4626527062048));
#1939=CARTESIAN_POINT('',(7.61992255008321,-23.4695293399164,34.9382840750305));
#1940=CARTESIAN_POINT('',(7.57975154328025,-23.4381047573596,34.6769689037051));
#1941=CARTESIAN_POINT('',(7.49122010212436,-23.3698830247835,34.1564977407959));
#1942=CARTESIAN_POINT('',(7.44286164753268,-23.3330871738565,33.897341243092));
#1943=CARTESIAN_POINT('',(7.33753208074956,-23.2543434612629,33.3816156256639));
#1944=CARTESIAN_POINT('',(7.28056244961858,-23.212396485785,33.1250460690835));
#1945=CARTESIAN_POINT('',(7.15864931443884,-23.1244437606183,32.6197243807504));
#1946=CARTESIAN_POINT('',(7.09387488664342,-23.0785286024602,32.3709157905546));
#1947=CARTESIAN_POINT('',(6.95498068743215,-22.9822974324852,31.8767835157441));
#1948=CARTESIAN_POINT('',(6.88086124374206,-22.9319815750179,31.6314597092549));
#1949=CARTESIAN_POINT('',(6.72261154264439,-22.8273057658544,31.1448750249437));
#1950=CARTESIAN_POINT('',(6.63847943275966,-22.7729450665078,30.9036149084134));
#1951=CARTESIAN_POINT('',(6.46017791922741,-22.6610762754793,30.4278433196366));
#1952=CARTESIAN_POINT('',(6.366093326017,-22.6035965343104,30.1932935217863));
#1953=CARTESIAN_POINT('',(6.16653442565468,-22.485636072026,29.7298883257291));
#1954=CARTESIAN_POINT('',(6.06106167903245,-22.4251557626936,29.5010321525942));
#1955=CARTESIAN_POINT('',(5.83781515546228,-22.3018427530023,29.0501184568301));
#1956=CARTESIAN_POINT('',(5.72004615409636,-22.2390109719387,28.8280583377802));
#1957=CARTESIAN_POINT('',(5.53024263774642,-22.1419785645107,28.4955302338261));
#1958=CARTESIAN_POINT('',(5.46303350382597,-22.1083440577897,28.382124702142));
#1959=CARTESIAN_POINT('',(5.32478059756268,-22.0407817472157,28.1577918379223));
#1960=CARTESIAN_POINT('',(5.25373763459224,-22.0068540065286,28.0468639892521));
#1961=CARTESIAN_POINT('',(5.10766305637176,-21.9388586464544,27.8277555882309));
#1962=CARTESIAN_POINT('',(5.03263257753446,-21.9047910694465,27.7195742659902));
#1963=CARTESIAN_POINT('',(4.87791049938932,-21.8364606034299,27.5055474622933));
#1964=CARTESIAN_POINT('',(4.79819252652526,-21.8021978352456,27.3997209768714));
#1965=CARTESIAN_POINT('',(4.63433217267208,-21.7338728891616,27.1914185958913));
#1966=CARTESIAN_POINT('',(4.5501884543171,-21.6998107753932,27.0889437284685));
#1967=CARTESIAN_POINT('',(4.37724482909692,-21.6320855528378,26.8876702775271));
#1968=CARTESIAN_POINT('',(4.28844015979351,-21.5984228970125,26.7888756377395));
#1969=CARTESIAN_POINT('',(4.19726547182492,-21.5650897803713,26.6921745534));
#1970=B_SPLINE_CURVE_WITH_KNOTS('',3,(#1928,#1929,#1930,#1931,#1932,#1933,#1934,#1935,#1936,
#1937,#1938,#1939,#1940,#1941,#1942,#1943,#1944,#1945,#1946,#1947,#1948,#1949,#1950,#1951,#1952,
#1953,#1954,#1955,#1956,#1957,#1958,#1959,#1960,#1961,#1962,#1963,#1964,#1965,#1966,#1967,#1968,
#1969),.UNSPECIFIED.,.F.,.F.,(4,2,2,2,2,2,2,2,2,2,2,2,2,2,2,2,2,2,2,2,4),(0.,0.784409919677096,
1.56942732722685,2.35480442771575,3.14031936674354,3.9390205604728,4.73757457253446,
5.53593576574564,6.33415980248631,7.11745364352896,7.90072002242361,8.68413154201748,
9.46133584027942,10.2384337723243,11.0152310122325,11.4233124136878,11.831307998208,
12.2391879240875,12.6496360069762,13.0602088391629,13.471209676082),.UNSPECIFIED.);
#1971=CARTESIAN_POINT('',(4.19726547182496,-21.5650897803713,26.6921745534));
#1972=VERTEX_POINT('',#1971);
#1973=EDGE_CURVE('E503',#1925,#1972,#1970,.T.);
#1974=ORIENTED_EDGE('',*,*,#1973,.T.);
#1975=CARTESIAN_POINT('',(0.,0.,26.6921745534));
#1976=DIRECTION('',(0.,0.,1.));
#1977=DIRECTION('',(0.,1.,0.));
#1978=AXIS2_PLACEMENT_3D('',#1975,#1976,#1977);
#1979=CIRCLE('',#1978,21.9697549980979);
#1980=EDGE_CURVE('E270',#1826,#1972,#1979,.F.);
#1981=ORIENTED_EDGE('',*,*,#1980,.F.);
#1982=ORIENTED_EDGE('',*,*,#1827,.T.);
#1983=EDGE_LOOP('',(#1883,#1884,#1927,#1974,#1981,#1982));
#1984=FACE_BOUND('',#1983,.T.);
#1985=ADVANCED_FACE('F494',(#1984),#1882,.F.);
#1986=CARTESIAN_POINT('',(-0.094370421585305,-33.3052712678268,0.));
#1987=DIRECTION('',(0.,0.,-1.));
#1988=DIRECTION('',(-1.,0.,0.));
#1989=AXIS2_PLACEMENT_3D('',#1986,#1987,#1988);
#1990=CYLINDRICAL_SURFACE('',#1989,12.5);
#1991=ORIENTED_EDGE('',*,*,#733,.F.);
#1992=CARTESIAN_POINT('',(0.,-20.8056275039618,24.4469023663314));
#1993=CARTESIAN_POINT('',(-0.120637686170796,-20.8046979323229,24.4450833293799));
#1994=CARTESIAN_POINT('',(-0.241336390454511,-20.8055513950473,24.4487784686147));
#1995=CARTESIAN_POINT('',(-0.481708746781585,-20.8107014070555,24.4667791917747));
#1996=CARTESIAN_POINT('',(-0.601383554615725,-20.8149933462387,24.4810705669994));
#1997=CARTESIAN_POINT('',(-0.836973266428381,-20.8267994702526,24.5195303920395));
#1998=CARTESIAN_POINT('',(-0.952917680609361,-20.8342605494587,24.5435357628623));
#1999=CARTESIAN_POINT('',(-1.18230658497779,-20.8521731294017,24.600668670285));
#2000=CARTESIAN_POINT('',(-1.29575015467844,-20.8626257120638,24.6337995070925));
#2001=CARTESIAN_POINT('',(-1.69595036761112,-20.904917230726,24.7671286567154));
#2002=CARTESIAN_POINT('',(-1.9742514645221,-20.9445099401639,24.8907704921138));
#2003=CARTESIAN_POINT('',(-2.50909815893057,-21.0376677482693,25.1788496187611));
#2004=CARTESIAN_POINT('',(-2.76538101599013,-21.0913769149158,25.3437066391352));
#2005=CARTESIAN_POINT('',(-3.13024153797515,-21.1789089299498,25.6100169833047));
#2006=CARTESIAN_POINT('',(-3.24761105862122,-21.2089413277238,25.7010387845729));
#2007=CARTESIAN_POINT('',(-3.47720320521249,-21.2711278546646,25.8887394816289));
#2008=CARTESIAN_POINT('',(-3.58942493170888,-21.30328235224,25.9854193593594));
#2009=CARTESIAN_POINT('',(-3.80705692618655,-21.368829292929,26.1816871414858));
#2010=CARTESIAN_POINT('',(-3.91255367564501,-21.4021888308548,26.2811908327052));
#2011=CARTESIAN_POINT('',(-4.119160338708,-21.4704563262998,26.4839897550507));
#2012=CARTESIAN_POINT('',(-4.22027348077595,-21.5053631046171,26.5872820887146));
#2013=CARTESIAN_POINT('',(-4.31940637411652,-21.5409578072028,26.6921745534));
#2014=B_SPLINE_CURVE_WITH_KNOTS('',3,(#1992,#1993,#1994,#1995,#1996,#1997,#1998,#1999,#2000,
#2001,#2002,#2003,#2004,#2005,#2006,#2007,#2008,#2009,#2010,#2011,#2012,#2013),.UNSPECIFIED.,
.F.,.F.,(4,2,2,2,2,2,2,2,2,2,4),(0.,0.361775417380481,0.723066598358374,1.07852863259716,
1.4341193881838,2.34979008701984,3.27519543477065,3.72963431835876,4.18415230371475,
4.63045028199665,5.07641378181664),.UNSPECIFIED.);
#2015=CARTESIAN_POINT('',(0.,-20.8056275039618,24.4469023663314));
#2016=VERTEX_POINT('',#2015);
#2017=EDGE_CURVE('E678',#2016,#691,#2014,.T.);
#2018=ORIENTED_EDGE('',*,*,#2017,.F.);
#2019=CARTESIAN_POINT('',(4.19726547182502,-21.5650897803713,26.6921745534));
#2020=CARTESIAN_POINT('',(4.08390255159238,-21.5236640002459,26.5719954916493));
#2021=CARTESIAN_POINT('',(3.96793680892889,-21.4831204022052,26.4538963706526));
#2022=CARTESIAN_POINT('',(3.73010692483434,-21.4040448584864,26.2227286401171));
#2023=CARTESIAN_POINT('',(3.6082345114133,-21.3655159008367,26.1096675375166));
#2024=CARTESIAN_POINT('',(3.35561609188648,-21.290059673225,25.8875070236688));
#2025=CARTESIAN_POINT('',(3.22473804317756,-21.2531825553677,25.7785393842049));
#2026=CARTESIAN_POINT('',(2.9560000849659,-21.1823783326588,25.568700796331));
#2027=CARTESIAN_POINT('',(2.8181436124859,-21.148449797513,25.4678259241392));
#2028=CARTESIAN_POINT('',(2.43729827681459,-21.0618681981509,25.2097850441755));
#2029=CARTESIAN_POINT('',(2.18724544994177,-21.0123970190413,25.0616525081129));
#2030=CARTESIAN_POINT('',(1.66734046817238,-20.9272816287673,24.8065096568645));
#2031=CARTESIAN_POINT('',(1.3977232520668,-20.8914979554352,24.6990846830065));
#2032=CARTESIAN_POINT('',(0.939251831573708,-20.8467623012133,24.565546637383));
#2033=CARTESIAN_POINT('',(0.755384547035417,-20.8327991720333,24.5241216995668));
#2034=CARTESIAN_POINT('',(0.475328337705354,-20.8179040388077,24.480635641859));
#2035=CARTESIAN_POINT('',(0.380698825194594,-20.8139421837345,24.4692380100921));
#2036=CARTESIAN_POINT('',(0.190743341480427,-20.8081605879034,24.4530545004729));
#2037=CARTESIAN_POINT('',(0.0954169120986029,-20.8063424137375,24.4482734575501));
#2038=CARTESIAN_POINT('',(0.,-20.8056275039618,24.4469023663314));
#2039=B_SPLINE_CURVE_WITH_KNOTS('',3,(#2019,#2020,#2021,#2022,#2023,#2024,#2025,#2026,#2027,
#2028,#2029,#2030,#2031,#2032,#2033,#2034,#2035,#2036,#2037,#2038),.UNSPECIFIED.,.F.,.F.,(4,2,2,
2,2,2,2,2,2,4),(0.,0.51100910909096,1.02275579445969,1.54517359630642,2.06733655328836,
2.94883150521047,3.82108914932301,4.38624133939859,4.67219460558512,4.95835671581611),.UNSPECIFIED.);
#2040=EDGE_CURVE('E260',#1972,#2016,#2039,.T.);
#2041=ORIENTED_EDGE('',*,*,#2040,.F.);
#2042=ORIENTED_EDGE('',*,*,#1973,.F.);
#2043=ORIENTED_EDGE('',*,*,#1926,.F.);
#2044=ORIENTED_EDGE('',*,*,#618,.F.);
#2045=ORIENTED_EDGE('',*,*,#778,.F.);
#2046=EDGE_LOOP('',(#1991,#2018,#2041,#2042,#2043,#2044,#2045));
#2047=FACE_BOUND('',#2046,.T.);
#2048=ADVANCED_FACE('F278',(#2047),#1990,.F.);
#2049=CARTESIAN_POINT('',(0.,0.,26.6921745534));
#2050=DIRECTION('',(0.,0.,1.));
#2051=DIRECTION('',(1.,0.,0.));
#2052=AXIS2_PLACEMENT_3D('',#2049,#2050,#2051);
#2053=CONICAL_SURFACE('',#2052,21.9697549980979,0.478321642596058);
#2054=ORIENTED_EDGE('',*,*,#1240,.T.);
#2055=ORIENTED_EDGE('',*,*,#1446,.T.);
#2056=DIRECTION('',(0.,-0.460289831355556,-0.887768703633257));
#2057=VECTOR('',#2056,1.);
#2058=CARTESIAN_POINT('',(0.,20.234877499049,23.3460872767));
#2059=LINE('',#2058,#2057);
#2060=CARTESIAN_POINT('',(0.,18.5,20.));
#2061=VERTEX_POINT('',#2060);
#2062=EDGE_CURVE('E480',#2061,#1438,#2059,.F.);
#2063=ORIENTED_EDGE('',*,*,#2062,.F.);
#2064=CARTESIAN_POINT('',(0.,0.,20.));
#2065=DIRECTION('',(0.,0.,1.));
#2066=DIRECTION('',(1.,0.,0.));
#2067=AXIS2_PLACEMENT_3D('',#2064,#2065,#2066);
#2068=CIRCLE('',#2067,18.5);
#2069=CARTESIAN_POINT('',(0.,-18.5,20.));
#2070=VERTEX_POINT('',#2069);
#2071=EDGE_CURVE('E259',#2070,#2061,#2068,.F.);
#2072=ORIENTED_EDGE('',*,*,#2071,.F.);
#2073=DIRECTION('',(0.,0.460289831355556,-0.887768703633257));
#2074=VECTOR('',#2073,1.);
#2075=CARTESIAN_POINT('',(0.,-20.234877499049,23.3460872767));
#2076=LINE('',#2075,#2074);
#2077=EDGE_CURVE('E269',#2016,#2070,#2076,.T.);
#2078=ORIENTED_EDGE('',*,*,#2077,.F.);
#2079=ORIENTED_EDGE('',*,*,#2017,.T.);
#2080=ORIENTED_EDGE('',*,*,#694,.T.);
#2081=ORIENTED_EDGE('',*,*,#978,.T.);
#2082=ORIENTED_EDGE('',*,*,#1029,.T.);
#2083=ORIENTED_EDGE('',*,*,#1151,.T.);
#2084=EDGE_LOOP('',(#2054,#2055,#2063,#2072,#2078,#2079,#2080,#2081,#2082,#2083));
#2085=FACE_BOUND('',#2084,.T.);
#2086=ADVANCED_FACE('F696',(#2085),#2053,.T.);
#2087=CARTESIAN_POINT('',(0.,0.,0.15));
#2088=DIRECTION('',(0.,0.,1.));
#2089=DIRECTION('',(1.,0.,0.));
#2090=AXIS2_PLACEMENT_3D('',#2087,#2088,#2089);
#2091=CYLINDRICAL_SURFACE('',#2090,7.75);
#2092=DIRECTION('',(0.,0.,1.));
#2093=VECTOR('',#2092,1.);
#2094=CARTESIAN_POINT('',(0.,-7.75,0.15));
#2095=LINE('',#2094,#2093);
#2096=CARTESIAN_POINT('',(0.,-7.75,0.3));
#2097=VERTEX_POINT('',#2096);
#2098=EDGE_CURVE('E474',#1315,#2097,#2095,.T.);
#2099=ORIENTED_EDGE('',*,*,#2098,.F.);
#2100=ORIENTED_EDGE('',*,*,#1318,.T.);
#2101=DIRECTION('',(0.,0.,1.));
#2102=VECTOR('',#2101,1.);
#2103=CARTESIAN_POINT('',(0.,7.75,0.15));
#2104=LINE('',#2103,#2102);
#2105=CARTESIAN_POINT('',(0.,7.75,0.3));
#2106=VERTEX_POINT('',#2105);
#2107=EDGE_CURVE('E477',#2106,#1317,#2104,.F.);
#2108=ORIENTED_EDGE('',*,*,#2107,.F.);
#2109=CARTESIAN_POINT('',(0.,0.,0.3));
#2110=DIRECTION('',(0.,0.,1.));
#2111=DIRECTION('',(1.,0.,0.));
#2112=AXIS2_PLACEMENT_3D('',#2109,#2110,#2111);
#2113=CIRCLE('',#2112,7.75);
#2114=EDGE_CURVE('E256',#2097,#2106,#2113,.T.);
#2115=ORIENTED_EDGE('',*,*,#2114,.F.);
#2116=EDGE_LOOP('',(#2099,#2100,#2108,#2115));
#2117=FACE_BOUND('',#2116,.T.);
#2118=ADVANCED_FACE('F473',(#2117),#2091,.T.);
#2119=CARTESIAN_POINT('',(0.,0.,0.15));
#2120=DIRECTION('',(0.,0.,1.));
#2121=DIRECTION('',(1.,0.,0.));
#2122=AXIS2_PLACEMENT_3D('',#2119,#2120,#2121);
#2123=CYLINDRICAL_SURFACE('',#2122,7.75);
#2124=ORIENTED_EDGE('',*,*,#2098,.T.);
#2125=CARTESIAN_POINT('',(0.,0.,0.3));
#2126=DIRECTION('',(0.,0.,1.));
#2127=DIRECTION('',(1.,0.,0.));
#2128=AXIS2_PLACEMENT_3D('',#2125,#2126,#2127);
#2129=CIRCLE('',#2128,7.75);
#2130=EDGE_CURVE('E253',#2106,#2097,#2129,.T.);
#2131=ORIENTED_EDGE('',*,*,#2130,.F.);
#2132=ORIENTED_EDGE('',*,*,#2107,.T.);
#2133=ORIENTED_EDGE('',*,*,#1325,.T.);
#2134=EDGE_LOOP('',(#2124,#2131,#2132,#2133));
#2135=FACE_BOUND('',#2134,.T.);
#2136=ADVANCED_FACE('F288',(#2135),#2123,.T.);
#2137=CARTESIAN_POINT('',(0.,0.,26.6921745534));
#2138=DIRECTION('',(0.,0.,1.));
#2139=DIRECTION('',(1.,0.,0.));
#2140=AXIS2_PLACEMENT_3D('',#2137,#2138,#2139);
#2141=CONICAL_SURFACE('',#2140,21.9697549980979,0.478321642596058);
#2142=ORIENTED_EDGE('',*,*,#2077,.T.);
#2143=CARTESIAN_POINT('',(0.,0.,20.));
#2144=DIRECTION('',(0.,0.,1.));
#2145=DIRECTION('',(1.,0.,0.));
#2146=AXIS2_PLACEMENT_3D('',#2143,#2144,#2145);
#2147=CIRCLE('',#2146,18.5);
#2148=EDGE_CURVE('E244',#2061,#2070,#2147,.F.);
#2149=ORIENTED_EDGE('',*,*,#2148,.F.);
#2150=ORIENTED_EDGE('',*,*,#2062,.T.);
#2151=ORIENTED_EDGE('',*,*,#1439,.T.);
#2152=ORIENTED_EDGE('',*,*,#1582,.T.);
#2153=ORIENTED_EDGE('',*,*,#1666,.T.);
#2154=ORIENTED_EDGE('',*,*,#1729,.T.);
#2155=ORIENTED_EDGE('',*,*,#1866,.T.);
#2156=ORIENTED_EDGE('',*,*,#1980,.T.);
#2157=ORIENTED_EDGE('',*,*,#2040,.T.);
#2158=EDGE_LOOP('',(#2142,#2149,#2150,#2151,#2152,#2153,#2154,#2155,#2156,#2157));
#2159=FACE_BOUND('',#2158,.T.);
#2160=ADVANCED_FACE('F282',(#2159),#2141,.T.);
#2161=CARTESIAN_POINT('',(0.,0.,10.15));
#2162=DIRECTION('',(0.,0.,1.));
#2163=DIRECTION('',(1.,0.,0.));
#2164=AXIS2_PLACEMENT_3D('',#2161,#2162,#2163);
#2165=CYLINDRICAL_SURFACE('',#2164,18.5);
#2166=DIRECTION('',(0.,0.,1.));
#2167=VECTOR('',#2166,1.);
#2168=CARTESIAN_POINT('',(0.,-18.5,10.15));
#2169=LINE('',#2168,#2167);
#2170=CARTESIAN_POINT('',(0.,-18.5,0.3));
#2171=VERTEX_POINT('',#2170);
#2172=EDGE_CURVE('E239',#2070,#2171,#2169,.F.);
#2173=ORIENTED_EDGE('',*,*,#2172,.F.);
#2174=ORIENTED_EDGE('',*,*,#2071,.T.);
#2175=DIRECTION('',(0.,0.,1.));
#2176=VECTOR('',#2175,1.);
#2177=CARTESIAN_POINT('',(0.,18.5,10.15));
#2178=LINE('',#2177,#2176);
#2179=CARTESIAN_POINT('',(0.,18.5,0.3));
#2180=VERTEX_POINT('',#2179);
#2181=EDGE_CURVE('E252',#2180,#2061,#2178,.T.);
#2182=ORIENTED_EDGE('',*,*,#2181,.F.);
#2183=CARTESIAN_POINT('',(0.,0.,0.3));
#2184=DIRECTION('',(0.,0.,1.));
#2185=DIRECTION('',(1.,0.,0.));
#2186=AXIS2_PLACEMENT_3D('',#2183,#2184,#2185);
#2187=CIRCLE('',#2186,18.5);
#2188=EDGE_CURVE('E31',#2171,#2180,#2187,.F.);
#2189=ORIENTED_EDGE('',*,*,#2188,.F.);
#2190=EDGE_LOOP('',(#2173,#2174,#2182,#2189));
#2191=FACE_BOUND('',#2190,.T.);
#2192=ADVANCED_FACE('F287',(#2191),#2165,.T.);
#2193=CARTESIAN_POINT('',(0.,13.125,0.3));
#2194=DIRECTION('',(0.,0.,-1.));
#2195=DIRECTION('',(0.,-1.,0.));
#2196=AXIS2_PLACEMENT_3D('',#2193,#2194,#2195);
#2197=PLANE('',#2196);
#2198=CARTESIAN_POINT('',(0.,0.,0.3));
#2199=DIRECTION('',(0.,0.,1.));
#2200=DIRECTION('',(1.,0.,0.));
#2201=AXIS2_PLACEMENT_3D('',#2198,#2199,#2200);
#2202=CIRCLE('',#2201,18.5);
#2203=EDGE_CURVE('E235',#2171,#2180,#2202,.T.);
#2204=ORIENTED_EDGE('',*,*,#2203,.F.);
#2205=ORIENTED_EDGE('',*,*,#2188,.T.);
#2206=EDGE_LOOP('',(#2204,#2205));
#2207=FACE_BOUND('',#2206,.T.);
#2208=ORIENTED_EDGE('',*,*,#2114,.T.);
#2209=ORIENTED_EDGE('',*,*,#2130,.T.);
#2210=EDGE_LOOP('',(#2208,#2209));
#2211=FACE_BOUND('',#2210,.T.);
#2212=ADVANCED_FACE('F461',(#2207,#2211),#2197,.T.);
#2213=CARTESIAN_POINT('',(0.,0.,10.15));
#2214=DIRECTION('',(0.,0.,1.));
#2215=DIRECTION('',(1.,0.,0.));
#2216=AXIS2_PLACEMENT_3D('',#2213,#2214,#2215);
#2217=CYLINDRICAL_SURFACE('',#2216,18.5);
#2218=ORIENTED_EDGE('',*,*,#2172,.T.);
#2219=ORIENTED_EDGE('',*,*,#2203,.T.);
#2220=ORIENTED_EDGE('',*,*,#2181,.T.);
#2221=ORIENTED_EDGE('',*,*,#2148,.T.);
#2222=EDGE_LOOP('',(#2218,#2219,#2220,#2221));
#2223=FACE_BOUND('',#2222,.T.);
#2224=ADVANCED_FACE('F453',(#2223),#2217,.T.);
#2225=CARTESIAN_POINT('',(0.,0.,20.));
#2226=DIRECTION('',(0.,0.,-1.));
#2227=DIRECTION('',(-1.,0.,0.));
#2228=AXIS2_PLACEMENT_3D('',#2225,#2226,#2227);
#2229=CYLINDRICAL_SURFACE('',#2228,4.);
#2230=CARTESIAN_POINT('',(0.,0.,0.500000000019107));
#2231=DIRECTION('',(0.,0.,-1.));
#2232=DIRECTION('',(-1.,0.,0.));
#2233=AXIS2_PLACEMENT_3D('',#2230,#2231,#2232);
#2234=CIRCLE('',#2233,4.);
#2235=CARTESIAN_POINT('',(-4.,0.,0.500000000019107));
#2236=VERTEX_POINT('',#2235);
#2237=EDGE_CURVE('E9',#2236,#2236,#2234,.T.);
#2238=ORIENTED_EDGE('',*,*,#2237,.T.);
#2239=EDGE_LOOP('',(#2238));
#2240=FACE_BOUND('',#2239,.T.);
#2241=CARTESIAN_POINT('',(0.,0.,20.0000000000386));
#2242=DIRECTION('',(0.,0.,1.));
#2243=DIRECTION('',(1.,0.,0.));
#2244=AXIS2_PLACEMENT_3D('',#2241,#2242,#2243);
#2245=CIRCLE('',#2244,4.0000000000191);
#2246=CARTESIAN_POINT('',(4.0000000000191,0.,20.0000000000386));
#2247=VERTEX_POINT('',#2246);
#2248=EDGE_CURVE('E222',#2247,#2247,#2245,.F.);
#2249=ORIENTED_EDGE('',*,*,#2248,.F.);
#2250=EDGE_LOOP('',(#2249));
#2251=FACE_BOUND('',#2250,.T.);
#2252=ADVANCED_FACE('F434',(#2240,#2251),#2229,.F.);
#2253=CARTESIAN_POINT('',(0.,2.,20.));
#2254=DIRECTION('',(0.,0.,1.));
#2255=DIRECTION('',(1.,0.,0.));
#2256=AXIS2_PLACEMENT_3D('',#2253,#2254,#2255);
#2257=PLANE('',#2256);
#2258=ORIENTED_EDGE('',*,*,#2248,.T.);
#2259=EDGE_LOOP('',(#2258));
#2260=FACE_BOUND('',#2259,.T.);
#2261=ADVANCED_FACE('F435',(#2260),#2257,.F.);
#2262=CARTESIAN_POINT('',(0.,0.,0.));
#2263=DIRECTION('',(0.,0.,-1.));
#2264=DIRECTION('',(-1.,0.,0.));
#2265=AXIS2_PLACEMENT_3D('',#2262,#2263,#2264);
#2266=CONICAL_SURFACE('',#2265,4.5000000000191,0.785398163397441);
#2267=ORIENTED_EDGE('',*,*,#2237,.F.);
#2268=EDGE_LOOP('',(#2267));
#2269=FACE_BOUND('',#2268,.T.);
#2270=ORIENTED_EDGE('',*,*,#1305,.F.);
#2271=EDGE_LOOP('',(#2270));
#2272=FACE_BOUND('',#2271,.T.);
#2273=ADVANCED_FACE('F16',(#2269,#2272),#2266,.F.);
#2274=CLOSED_SHELL('',(#76,#102,#135,#154,#195,#222,#296,#438,#510,#674,#871,#1011,#1041,#1156,
#1292,#1329,#1451,#1587,#1674,#1734,#1872,#1985,#2048,#2086,#2118,#2136,#2160,#2192,#2212,#2224,
#2252,#2261,#2273));
#2275=MANIFOLD_SOLID_BREP('B1',#2274);
#2276=ADVANCED_BREP_SHAPE_REPRESENTATION('',(#18,#2275),#14);
#2277=SHAPE_DEFINITION_REPRESENTATION(#9,#2276);
ENDSEC;
END-ISO-10303-21;
